VERSION 5.8 ;
BUSBITCHARS "[]" ;
DIVIDERCHAR "/" ;
UNITS
    DATABASE MICRONS 1000 ;
END UNITS

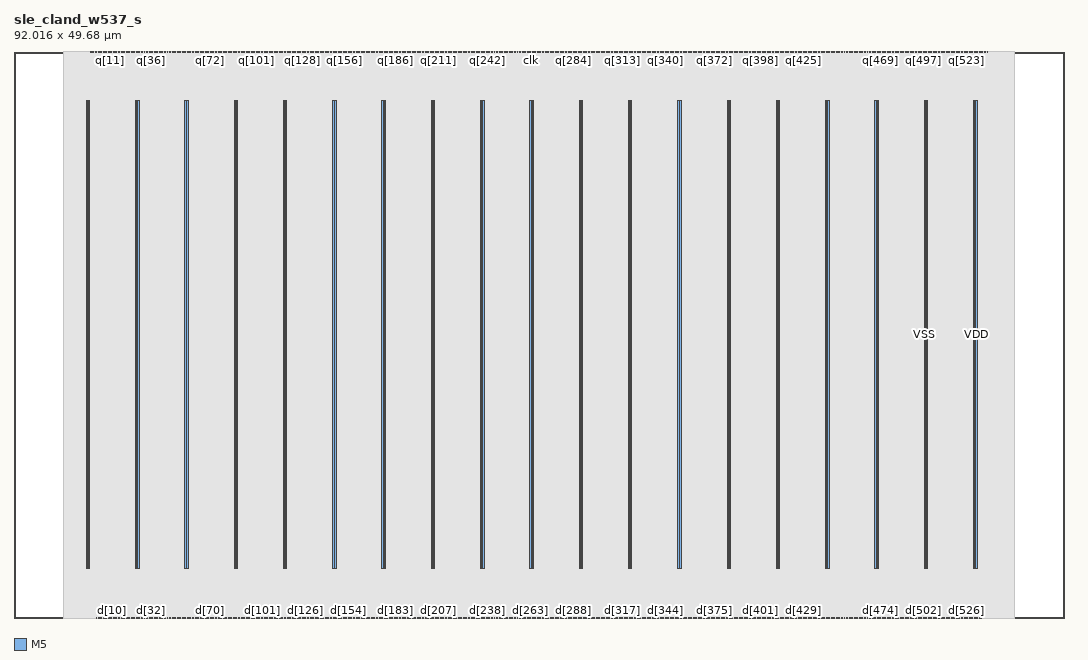
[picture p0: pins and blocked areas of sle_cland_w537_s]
MACRO sle_cland_w537_s
  FOREIGN sle_cland_w537_s 0 0 ;
  CLASS BLOCK ;
  SIZE 92.016 BY 49.68 ;
  PIN clk
    DIRECTION INPUT ;
    USE SIGNAL ;
    PORT
      LAYER M5 ;
        RECT  45.264 49.596 45.288 49.68 ;
    END
  END clk
  PIN d[0]
    DIRECTION INPUT ;
    USE SIGNAL ;
    PORT
      LAYER M5 ;
        RECT  7.248 0 7.272 0.084 ;
    END
  END d[0]
  PIN d[100]
    DIRECTION INPUT ;
    USE SIGNAL ;
    PORT
      LAYER M5 ;
        RECT  21.648 0 21.672 0.084 ;
    END
  END d[100]
  PIN d[101]
    DIRECTION INPUT ;
    USE SIGNAL ;
    PORT
      LAYER M5 ;
        RECT  21.792 0 21.816 0.084 ;
    END
  END d[101]
  PIN d[102]
    DIRECTION INPUT ;
    USE SIGNAL ;
    PORT
      LAYER M5 ;
        RECT  21.936 0 21.96 0.084 ;
    END
  END d[102]
  PIN d[103]
    DIRECTION INPUT ;
    USE SIGNAL ;
    PORT
      LAYER M5 ;
        RECT  22.224 0 22.248 0.084 ;
    END
  END d[103]
  PIN d[104]
    DIRECTION INPUT ;
    USE SIGNAL ;
    PORT
      LAYER M5 ;
        RECT  22.08 0 22.104 0.084 ;
    END
  END d[104]
  PIN d[105]
    DIRECTION INPUT ;
    USE SIGNAL ;
    PORT
      LAYER M5 ;
        RECT  22.512 0 22.536 0.084 ;
    END
  END d[105]
  PIN d[106]
    DIRECTION INPUT ;
    USE SIGNAL ;
    PORT
      LAYER M5 ;
        RECT  22.368 0 22.392 0.084 ;
    END
  END d[106]
  PIN d[107]
    DIRECTION INPUT ;
    USE SIGNAL ;
    PORT
      LAYER M5 ;
        RECT  22.8 0 22.824 0.084 ;
    END
  END d[107]
  PIN d[108]
    DIRECTION INPUT ;
    USE SIGNAL ;
    PORT
      LAYER M5 ;
        RECT  22.656 0 22.68 0.084 ;
    END
  END d[108]
  PIN d[109]
    DIRECTION INPUT ;
    USE SIGNAL ;
    PORT
      LAYER M5 ;
        RECT  23.232 0 23.256 0.084 ;
    END
  END d[109]
  PIN d[10]
    DIRECTION INPUT ;
    USE SIGNAL ;
    PORT
      LAYER M5 ;
        RECT  8.544 0 8.568 0.084 ;
    END
  END d[10]
  PIN d[110]
    DIRECTION INPUT ;
    USE SIGNAL ;
    PORT
      LAYER M5 ;
        RECT  22.944 0 22.968 0.084 ;
    END
  END d[110]
  PIN d[111]
    DIRECTION INPUT ;
    USE SIGNAL ;
    PORT
      LAYER M5 ;
        RECT  23.376 0 23.4 0.084 ;
    END
  END d[111]
  PIN d[112]
    DIRECTION INPUT ;
    USE SIGNAL ;
    PORT
      LAYER M5 ;
        RECT  23.088 0 23.112 0.084 ;
    END
  END d[112]
  PIN d[113]
    DIRECTION INPUT ;
    USE SIGNAL ;
    PORT
      LAYER M5 ;
        RECT  23.664 0 23.688 0.084 ;
    END
  END d[113]
  PIN d[114]
    DIRECTION INPUT ;
    USE SIGNAL ;
    PORT
      LAYER M5 ;
        RECT  23.52 0 23.544 0.084 ;
    END
  END d[114]
  PIN d[115]
    DIRECTION INPUT ;
    USE SIGNAL ;
    PORT
      LAYER M5 ;
        RECT  23.952 0 23.976 0.084 ;
    END
  END d[115]
  PIN d[116]
    DIRECTION INPUT ;
    USE SIGNAL ;
    PORT
      LAYER M5 ;
        RECT  23.808 0 23.832 0.084 ;
    END
  END d[116]
  PIN d[117]
    DIRECTION INPUT ;
    USE SIGNAL ;
    PORT
      LAYER M5 ;
        RECT  24.24 0 24.264 0.084 ;
    END
  END d[117]
  PIN d[118]
    DIRECTION INPUT ;
    USE SIGNAL ;
    PORT
      LAYER M5 ;
        RECT  24.096 0 24.12 0.084 ;
    END
  END d[118]
  PIN d[119]
    DIRECTION INPUT ;
    USE SIGNAL ;
    PORT
      LAYER M5 ;
        RECT  24.528 0 24.552 0.084 ;
    END
  END d[119]
  PIN d[11]
    DIRECTION INPUT ;
    USE SIGNAL ;
    PORT
      LAYER M5 ;
        RECT  8.976 0 9 0.084 ;
    END
  END d[11]
  PIN d[120]
    DIRECTION INPUT ;
    USE SIGNAL ;
    PORT
      LAYER M5 ;
        RECT  24.384 0 24.408 0.084 ;
    END
  END d[120]
  PIN d[121]
    DIRECTION INPUT ;
    USE SIGNAL ;
    PORT
      LAYER M5 ;
        RECT  24.672 0 24.696 0.084 ;
    END
  END d[121]
  PIN d[122]
    DIRECTION INPUT ;
    USE SIGNAL ;
    PORT
      LAYER M5 ;
        RECT  24.96 0 24.984 0.084 ;
    END
  END d[122]
  PIN d[123]
    DIRECTION INPUT ;
    USE SIGNAL ;
    PORT
      LAYER M5 ;
        RECT  24.816 0 24.84 0.084 ;
    END
  END d[123]
  PIN d[124]
    DIRECTION INPUT ;
    USE SIGNAL ;
    PORT
      LAYER M5 ;
        RECT  25.248 0 25.272 0.084 ;
    END
  END d[124]
  PIN d[125]
    DIRECTION INPUT ;
    USE SIGNAL ;
    PORT
      LAYER M5 ;
        RECT  25.104 0 25.128 0.084 ;
    END
  END d[125]
  PIN d[126]
    DIRECTION INPUT ;
    USE SIGNAL ;
    PORT
      LAYER M5 ;
        RECT  25.536 0 25.56 0.084 ;
    END
  END d[126]
  PIN d[127]
    DIRECTION INPUT ;
    USE SIGNAL ;
    PORT
      LAYER M5 ;
        RECT  25.392 0 25.416 0.084 ;
    END
  END d[127]
  PIN d[128]
    DIRECTION INPUT ;
    USE SIGNAL ;
    PORT
      LAYER M5 ;
        RECT  25.824 0 25.848 0.084 ;
    END
  END d[128]
  PIN d[129]
    DIRECTION INPUT ;
    USE SIGNAL ;
    PORT
      LAYER M5 ;
        RECT  25.68 0 25.704 0.084 ;
    END
  END d[129]
  PIN d[12]
    DIRECTION INPUT ;
    USE SIGNAL ;
    PORT
      LAYER M5 ;
        RECT  8.688 0 8.712 0.084 ;
    END
  END d[12]
  PIN d[130]
    DIRECTION INPUT ;
    USE SIGNAL ;
    PORT
      LAYER M5 ;
        RECT  26.112 0 26.136 0.084 ;
    END
  END d[130]
  PIN d[131]
    DIRECTION INPUT ;
    USE SIGNAL ;
    PORT
      LAYER M5 ;
        RECT  25.968 0 25.992 0.084 ;
    END
  END d[131]
  PIN d[132]
    DIRECTION INPUT ;
    USE SIGNAL ;
    PORT
      LAYER M5 ;
        RECT  26.4 0 26.424 0.084 ;
    END
  END d[132]
  PIN d[133]
    DIRECTION INPUT ;
    USE SIGNAL ;
    PORT
      LAYER M5 ;
        RECT  26.256 0 26.28 0.084 ;
    END
  END d[133]
  PIN d[134]
    DIRECTION INPUT ;
    USE SIGNAL ;
    PORT
      LAYER M5 ;
        RECT  26.544 0 26.568 0.084 ;
    END
  END d[134]
  PIN d[135]
    DIRECTION INPUT ;
    USE SIGNAL ;
    PORT
      LAYER M5 ;
        RECT  26.688 0 26.712 0.084 ;
    END
  END d[135]
  PIN d[136]
    DIRECTION INPUT ;
    USE SIGNAL ;
    PORT
      LAYER M5 ;
        RECT  26.976 0 27 0.084 ;
    END
  END d[136]
  PIN d[137]
    DIRECTION INPUT ;
    USE SIGNAL ;
    PORT
      LAYER M5 ;
        RECT  26.832 0 26.856 0.084 ;
    END
  END d[137]
  PIN d[138]
    DIRECTION INPUT ;
    USE SIGNAL ;
    PORT
      LAYER M5 ;
        RECT  27.12 0 27.144 0.084 ;
    END
  END d[138]
  PIN d[139]
    DIRECTION INPUT ;
    USE SIGNAL ;
    PORT
      LAYER M5 ;
        RECT  27.264 0 27.288 0.084 ;
    END
  END d[139]
  PIN d[13]
    DIRECTION INPUT ;
    USE SIGNAL ;
    PORT
      LAYER M5 ;
        RECT  9.264 0 9.288 0.084 ;
    END
  END d[13]
  PIN d[140]
    DIRECTION INPUT ;
    USE SIGNAL ;
    PORT
      LAYER M5 ;
        RECT  27.408 0 27.432 0.084 ;
    END
  END d[140]
  PIN d[141]
    DIRECTION INPUT ;
    USE SIGNAL ;
    PORT
      LAYER M5 ;
        RECT  27.552 0 27.576 0.084 ;
    END
  END d[141]
  PIN d[142]
    DIRECTION INPUT ;
    USE SIGNAL ;
    PORT
      LAYER M5 ;
        RECT  27.696 0 27.72 0.084 ;
    END
  END d[142]
  PIN d[143]
    DIRECTION INPUT ;
    USE SIGNAL ;
    PORT
      LAYER M5 ;
        RECT  27.84 0 27.864 0.084 ;
    END
  END d[143]
  PIN d[144]
    DIRECTION INPUT ;
    USE SIGNAL ;
    PORT
      LAYER M5 ;
        RECT  27.984 0 28.008 0.084 ;
    END
  END d[144]
  PIN d[145]
    DIRECTION INPUT ;
    USE SIGNAL ;
    PORT
      LAYER M5 ;
        RECT  28.128 0 28.152 0.084 ;
    END
  END d[145]
  PIN d[146]
    DIRECTION INPUT ;
    USE SIGNAL ;
    PORT
      LAYER M5 ;
        RECT  28.272 0 28.296 0.084 ;
    END
  END d[146]
  PIN d[147]
    DIRECTION INPUT ;
    USE SIGNAL ;
    PORT
      LAYER M5 ;
        RECT  28.416 0 28.44 0.084 ;
    END
  END d[147]
  PIN d[148]
    DIRECTION INPUT ;
    USE SIGNAL ;
    PORT
      LAYER M5 ;
        RECT  28.56 0 28.584 0.084 ;
    END
  END d[148]
  PIN d[149]
    DIRECTION INPUT ;
    USE SIGNAL ;
    PORT
      LAYER M5 ;
        RECT  28.704 0 28.728 0.084 ;
    END
  END d[149]
  PIN d[14]
    DIRECTION INPUT ;
    USE SIGNAL ;
    PORT
      LAYER M5 ;
        RECT  9.12 0 9.144 0.084 ;
    END
  END d[14]
  PIN d[150]
    DIRECTION INPUT ;
    USE SIGNAL ;
    PORT
      LAYER M5 ;
        RECT  28.848 0 28.872 0.084 ;
    END
  END d[150]
  PIN d[151]
    DIRECTION INPUT ;
    USE SIGNAL ;
    PORT
      LAYER M5 ;
        RECT  28.992 0 29.016 0.084 ;
    END
  END d[151]
  PIN d[152]
    DIRECTION INPUT ;
    USE SIGNAL ;
    PORT
      LAYER M5 ;
        RECT  29.136 0 29.16 0.084 ;
    END
  END d[152]
  PIN d[153]
    DIRECTION INPUT ;
    USE SIGNAL ;
    PORT
      LAYER M5 ;
        RECT  29.424 0 29.448 0.084 ;
    END
  END d[153]
  PIN d[154]
    DIRECTION INPUT ;
    USE SIGNAL ;
    PORT
      LAYER M5 ;
        RECT  29.28 0 29.304 0.084 ;
    END
  END d[154]
  PIN d[155]
    DIRECTION INPUT ;
    USE SIGNAL ;
    PORT
      LAYER M5 ;
        RECT  29.712 0 29.736 0.084 ;
    END
  END d[155]
  PIN d[156]
    DIRECTION INPUT ;
    USE SIGNAL ;
    PORT
      LAYER M5 ;
        RECT  29.568 0 29.592 0.084 ;
    END
  END d[156]
  PIN d[157]
    DIRECTION INPUT ;
    USE SIGNAL ;
    PORT
      LAYER M5 ;
        RECT  30 0 30.024 0.084 ;
    END
  END d[157]
  PIN d[158]
    DIRECTION INPUT ;
    USE SIGNAL ;
    PORT
      LAYER M5 ;
        RECT  29.856 0 29.88 0.084 ;
    END
  END d[158]
  PIN d[159]
    DIRECTION INPUT ;
    USE SIGNAL ;
    PORT
      LAYER M5 ;
        RECT  30.432 0 30.456 0.084 ;
    END
  END d[159]
  PIN d[15]
    DIRECTION INPUT ;
    USE SIGNAL ;
    PORT
      LAYER M5 ;
        RECT  9.552 0 9.576 0.084 ;
    END
  END d[15]
  PIN d[160]
    DIRECTION INPUT ;
    USE SIGNAL ;
    PORT
      LAYER M5 ;
        RECT  30.144 0 30.168 0.084 ;
    END
  END d[160]
  PIN d[161]
    DIRECTION INPUT ;
    USE SIGNAL ;
    PORT
      LAYER M5 ;
        RECT  30.576 0 30.6 0.084 ;
    END
  END d[161]
  PIN d[162]
    DIRECTION INPUT ;
    USE SIGNAL ;
    PORT
      LAYER M5 ;
        RECT  30.288 0 30.312 0.084 ;
    END
  END d[162]
  PIN d[163]
    DIRECTION INPUT ;
    USE SIGNAL ;
    PORT
      LAYER M5 ;
        RECT  30.864 0 30.888 0.084 ;
    END
  END d[163]
  PIN d[164]
    DIRECTION INPUT ;
    USE SIGNAL ;
    PORT
      LAYER M5 ;
        RECT  30.72 0 30.744 0.084 ;
    END
  END d[164]
  PIN d[165]
    DIRECTION INPUT ;
    USE SIGNAL ;
    PORT
      LAYER M5 ;
        RECT  31.152 0 31.176 0.084 ;
    END
  END d[165]
  PIN d[166]
    DIRECTION INPUT ;
    USE SIGNAL ;
    PORT
      LAYER M5 ;
        RECT  31.008 0 31.032 0.084 ;
    END
  END d[166]
  PIN d[167]
    DIRECTION INPUT ;
    USE SIGNAL ;
    PORT
      LAYER M5 ;
        RECT  31.44 0 31.464 0.084 ;
    END
  END d[167]
  PIN d[168]
    DIRECTION INPUT ;
    USE SIGNAL ;
    PORT
      LAYER M5 ;
        RECT  31.296 0 31.32 0.084 ;
    END
  END d[168]
  PIN d[169]
    DIRECTION INPUT ;
    USE SIGNAL ;
    PORT
      LAYER M5 ;
        RECT  31.728 0 31.752 0.084 ;
    END
  END d[169]
  PIN d[16]
    DIRECTION INPUT ;
    USE SIGNAL ;
    PORT
      LAYER M5 ;
        RECT  9.408 0 9.432 0.084 ;
    END
  END d[16]
  PIN d[170]
    DIRECTION INPUT ;
    USE SIGNAL ;
    PORT
      LAYER M5 ;
        RECT  31.584 0 31.608 0.084 ;
    END
  END d[170]
  PIN d[171]
    DIRECTION INPUT ;
    USE SIGNAL ;
    PORT
      LAYER M5 ;
        RECT  31.872 0 31.896 0.084 ;
    END
  END d[171]
  PIN d[172]
    DIRECTION INPUT ;
    USE SIGNAL ;
    PORT
      LAYER M5 ;
        RECT  32.16 0 32.184 0.084 ;
    END
  END d[172]
  PIN d[173]
    DIRECTION INPUT ;
    USE SIGNAL ;
    PORT
      LAYER M5 ;
        RECT  32.016 0 32.04 0.084 ;
    END
  END d[173]
  PIN d[174]
    DIRECTION INPUT ;
    USE SIGNAL ;
    PORT
      LAYER M5 ;
        RECT  32.448 0 32.472 0.084 ;
    END
  END d[174]
  PIN d[175]
    DIRECTION INPUT ;
    USE SIGNAL ;
    PORT
      LAYER M5 ;
        RECT  32.304 0 32.328 0.084 ;
    END
  END d[175]
  PIN d[176]
    DIRECTION INPUT ;
    USE SIGNAL ;
    PORT
      LAYER M5 ;
        RECT  32.736 0 32.76 0.084 ;
    END
  END d[176]
  PIN d[177]
    DIRECTION INPUT ;
    USE SIGNAL ;
    PORT
      LAYER M5 ;
        RECT  32.592 0 32.616 0.084 ;
    END
  END d[177]
  PIN d[178]
    DIRECTION INPUT ;
    USE SIGNAL ;
    PORT
      LAYER M5 ;
        RECT  33.024 0 33.048 0.084 ;
    END
  END d[178]
  PIN d[179]
    DIRECTION INPUT ;
    USE SIGNAL ;
    PORT
      LAYER M5 ;
        RECT  32.88 0 32.904 0.084 ;
    END
  END d[179]
  PIN d[17]
    DIRECTION INPUT ;
    USE SIGNAL ;
    PORT
      LAYER M5 ;
        RECT  9.84 0 9.864 0.084 ;
    END
  END d[17]
  PIN d[180]
    DIRECTION INPUT ;
    USE SIGNAL ;
    PORT
      LAYER M5 ;
        RECT  33.312 0 33.336 0.084 ;
    END
  END d[180]
  PIN d[181]
    DIRECTION INPUT ;
    USE SIGNAL ;
    PORT
      LAYER M5 ;
        RECT  33.168 0 33.192 0.084 ;
    END
  END d[181]
  PIN d[182]
    DIRECTION INPUT ;
    USE SIGNAL ;
    PORT
      LAYER M5 ;
        RECT  33.6 0 33.624 0.084 ;
    END
  END d[182]
  PIN d[183]
    DIRECTION INPUT ;
    USE SIGNAL ;
    PORT
      LAYER M5 ;
        RECT  33.456 0 33.48 0.084 ;
    END
  END d[183]
  PIN d[184]
    DIRECTION INPUT ;
    USE SIGNAL ;
    PORT
      LAYER M5 ;
        RECT  33.744 0 33.768 0.084 ;
    END
  END d[184]
  PIN d[185]
    DIRECTION INPUT ;
    USE SIGNAL ;
    PORT
      LAYER M5 ;
        RECT  33.888 0 33.912 0.084 ;
    END
  END d[185]
  PIN d[186]
    DIRECTION INPUT ;
    USE SIGNAL ;
    PORT
      LAYER M5 ;
        RECT  34.032 0 34.056 0.084 ;
    END
  END d[186]
  PIN d[187]
    DIRECTION INPUT ;
    USE SIGNAL ;
    PORT
      LAYER M5 ;
        RECT  34.176 0 34.2 0.084 ;
    END
  END d[187]
  PIN d[188]
    DIRECTION INPUT ;
    USE SIGNAL ;
    PORT
      LAYER M5 ;
        RECT  34.32 0 34.344 0.084 ;
    END
  END d[188]
  PIN d[189]
    DIRECTION INPUT ;
    USE SIGNAL ;
    PORT
      LAYER M5 ;
        RECT  34.464 0 34.488 0.084 ;
    END
  END d[189]
  PIN d[18]
    DIRECTION INPUT ;
    USE SIGNAL ;
    PORT
      LAYER M5 ;
        RECT  9.696 0 9.72 0.084 ;
    END
  END d[18]
  PIN d[190]
    DIRECTION INPUT ;
    USE SIGNAL ;
    PORT
      LAYER M5 ;
        RECT  34.608 0 34.632 0.084 ;
    END
  END d[190]
  PIN d[191]
    DIRECTION INPUT ;
    USE SIGNAL ;
    PORT
      LAYER M5 ;
        RECT  34.752 0 34.776 0.084 ;
    END
  END d[191]
  PIN d[192]
    DIRECTION INPUT ;
    USE SIGNAL ;
    PORT
      LAYER M5 ;
        RECT  34.896 0 34.92 0.084 ;
    END
  END d[192]
  PIN d[193]
    DIRECTION INPUT ;
    USE SIGNAL ;
    PORT
      LAYER M5 ;
        RECT  35.04 0 35.064 0.084 ;
    END
  END d[193]
  PIN d[194]
    DIRECTION INPUT ;
    USE SIGNAL ;
    PORT
      LAYER M5 ;
        RECT  35.184 0 35.208 0.084 ;
    END
  END d[194]
  PIN d[195]
    DIRECTION INPUT ;
    USE SIGNAL ;
    PORT
      LAYER M5 ;
        RECT  35.328 0 35.352 0.084 ;
    END
  END d[195]
  PIN d[196]
    DIRECTION INPUT ;
    USE SIGNAL ;
    PORT
      LAYER M5 ;
        RECT  35.472 0 35.496 0.084 ;
    END
  END d[196]
  PIN d[197]
    DIRECTION INPUT ;
    USE SIGNAL ;
    PORT
      LAYER M5 ;
        RECT  35.616 0 35.64 0.084 ;
    END
  END d[197]
  PIN d[198]
    DIRECTION INPUT ;
    USE SIGNAL ;
    PORT
      LAYER M5 ;
        RECT  35.76 0 35.784 0.084 ;
    END
  END d[198]
  PIN d[199]
    DIRECTION INPUT ;
    USE SIGNAL ;
    PORT
      LAYER M5 ;
        RECT  35.904 0 35.928 0.084 ;
    END
  END d[199]
  PIN d[19]
    DIRECTION INPUT ;
    USE SIGNAL ;
    PORT
      LAYER M5 ;
        RECT  10.128 0 10.152 0.084 ;
    END
  END d[19]
  PIN d[1]
    DIRECTION INPUT ;
    USE SIGNAL ;
    PORT
      LAYER M5 ;
        RECT  7.392 0 7.416 0.084 ;
    END
  END d[1]
  PIN d[200]
    DIRECTION INPUT ;
    USE SIGNAL ;
    PORT
      LAYER M5 ;
        RECT  36.048 0 36.072 0.084 ;
    END
  END d[200]
  PIN d[201]
    DIRECTION INPUT ;
    USE SIGNAL ;
    PORT
      LAYER M5 ;
        RECT  36.192 0 36.216 0.084 ;
    END
  END d[201]
  PIN d[202]
    DIRECTION INPUT ;
    USE SIGNAL ;
    PORT
      LAYER M5 ;
        RECT  36.336 0 36.36 0.084 ;
    END
  END d[202]
  PIN d[203]
    DIRECTION INPUT ;
    USE SIGNAL ;
    PORT
      LAYER M5 ;
        RECT  36.624 0 36.648 0.084 ;
    END
  END d[203]
  PIN d[204]
    DIRECTION INPUT ;
    USE SIGNAL ;
    PORT
      LAYER M5 ;
        RECT  36.48 0 36.504 0.084 ;
    END
  END d[204]
  PIN d[205]
    DIRECTION INPUT ;
    USE SIGNAL ;
    PORT
      LAYER M5 ;
        RECT  36.912 0 36.936 0.084 ;
    END
  END d[205]
  PIN d[206]
    DIRECTION INPUT ;
    USE SIGNAL ;
    PORT
      LAYER M5 ;
        RECT  36.768 0 36.792 0.084 ;
    END
  END d[206]
  PIN d[207]
    DIRECTION INPUT ;
    USE SIGNAL ;
    PORT
      LAYER M5 ;
        RECT  37.2 0 37.224 0.084 ;
    END
  END d[207]
  PIN d[208]
    DIRECTION INPUT ;
    USE SIGNAL ;
    PORT
      LAYER M5 ;
        RECT  37.056 0 37.08 0.084 ;
    END
  END d[208]
  PIN d[209]
    DIRECTION INPUT ;
    USE SIGNAL ;
    PORT
      LAYER M5 ;
        RECT  37.632 0 37.656 0.084 ;
    END
  END d[209]
  PIN d[20]
    DIRECTION INPUT ;
    USE SIGNAL ;
    PORT
      LAYER M5 ;
        RECT  9.984 0 10.008 0.084 ;
    END
  END d[20]
  PIN d[210]
    DIRECTION INPUT ;
    USE SIGNAL ;
    PORT
      LAYER M5 ;
        RECT  37.344 0 37.368 0.084 ;
    END
  END d[210]
  PIN d[211]
    DIRECTION INPUT ;
    USE SIGNAL ;
    PORT
      LAYER M5 ;
        RECT  37.776 0 37.8 0.084 ;
    END
  END d[211]
  PIN d[212]
    DIRECTION INPUT ;
    USE SIGNAL ;
    PORT
      LAYER M5 ;
        RECT  37.488 0 37.512 0.084 ;
    END
  END d[212]
  PIN d[213]
    DIRECTION INPUT ;
    USE SIGNAL ;
    PORT
      LAYER M5 ;
        RECT  38.064 0 38.088 0.084 ;
    END
  END d[213]
  PIN d[214]
    DIRECTION INPUT ;
    USE SIGNAL ;
    PORT
      LAYER M5 ;
        RECT  37.92 0 37.944 0.084 ;
    END
  END d[214]
  PIN d[215]
    DIRECTION INPUT ;
    USE SIGNAL ;
    PORT
      LAYER M5 ;
        RECT  38.352 0 38.376 0.084 ;
    END
  END d[215]
  PIN d[216]
    DIRECTION INPUT ;
    USE SIGNAL ;
    PORT
      LAYER M5 ;
        RECT  38.208 0 38.232 0.084 ;
    END
  END d[216]
  PIN d[217]
    DIRECTION INPUT ;
    USE SIGNAL ;
    PORT
      LAYER M5 ;
        RECT  38.64 0 38.664 0.084 ;
    END
  END d[217]
  PIN d[218]
    DIRECTION INPUT ;
    USE SIGNAL ;
    PORT
      LAYER M5 ;
        RECT  38.496 0 38.52 0.084 ;
    END
  END d[218]
  PIN d[219]
    DIRECTION INPUT ;
    USE SIGNAL ;
    PORT
      LAYER M5 ;
        RECT  39.072 0 39.096 0.084 ;
    END
  END d[219]
  PIN d[21]
    DIRECTION INPUT ;
    USE SIGNAL ;
    PORT
      LAYER M5 ;
        RECT  10.272 0 10.296 0.084 ;
    END
  END d[21]
  PIN d[220]
    DIRECTION INPUT ;
    USE SIGNAL ;
    PORT
      LAYER M5 ;
        RECT  38.784 0 38.808 0.084 ;
    END
  END d[220]
  PIN d[221]
    DIRECTION INPUT ;
    USE SIGNAL ;
    PORT
      LAYER M5 ;
        RECT  39.216 0 39.24 0.084 ;
    END
  END d[221]
  PIN d[222]
    DIRECTION INPUT ;
    USE SIGNAL ;
    PORT
      LAYER M5 ;
        RECT  38.928 0 38.952 0.084 ;
    END
  END d[222]
  PIN d[223]
    DIRECTION INPUT ;
    USE SIGNAL ;
    PORT
      LAYER M5 ;
        RECT  39.36 0 39.384 0.084 ;
    END
  END d[223]
  PIN d[224]
    DIRECTION INPUT ;
    USE SIGNAL ;
    PORT
      LAYER M5 ;
        RECT  39.648 0 39.672 0.084 ;
    END
  END d[224]
  PIN d[225]
    DIRECTION INPUT ;
    USE SIGNAL ;
    PORT
      LAYER M5 ;
        RECT  39.504 0 39.528 0.084 ;
    END
  END d[225]
  PIN d[226]
    DIRECTION INPUT ;
    USE SIGNAL ;
    PORT
      LAYER M5 ;
        RECT  39.936 0 39.96 0.084 ;
    END
  END d[226]
  PIN d[227]
    DIRECTION INPUT ;
    USE SIGNAL ;
    PORT
      LAYER M5 ;
        RECT  39.792 0 39.816 0.084 ;
    END
  END d[227]
  PIN d[228]
    DIRECTION INPUT ;
    USE SIGNAL ;
    PORT
      LAYER M5 ;
        RECT  40.224 0 40.248 0.084 ;
    END
  END d[228]
  PIN d[229]
    DIRECTION INPUT ;
    USE SIGNAL ;
    PORT
      LAYER M5 ;
        RECT  40.08 0 40.104 0.084 ;
    END
  END d[229]
  PIN d[22]
    DIRECTION INPUT ;
    USE SIGNAL ;
    PORT
      LAYER M5 ;
        RECT  10.56 0 10.584 0.084 ;
    END
  END d[22]
  PIN d[230]
    DIRECTION INPUT ;
    USE SIGNAL ;
    PORT
      LAYER M5 ;
        RECT  40.512 0 40.536 0.084 ;
    END
  END d[230]
  PIN d[231]
    DIRECTION INPUT ;
    USE SIGNAL ;
    PORT
      LAYER M5 ;
        RECT  40.368 0 40.392 0.084 ;
    END
  END d[231]
  PIN d[232]
    DIRECTION INPUT ;
    USE SIGNAL ;
    PORT
      LAYER M5 ;
        RECT  40.8 0 40.824 0.084 ;
    END
  END d[232]
  PIN d[233]
    DIRECTION INPUT ;
    USE SIGNAL ;
    PORT
      LAYER M5 ;
        RECT  40.656 0 40.68 0.084 ;
    END
  END d[233]
  PIN d[234]
    DIRECTION INPUT ;
    USE SIGNAL ;
    PORT
      LAYER M5 ;
        RECT  40.944 0 40.968 0.084 ;
    END
  END d[234]
  PIN d[235]
    DIRECTION INPUT ;
    USE SIGNAL ;
    PORT
      LAYER M5 ;
        RECT  41.088 0 41.112 0.084 ;
    END
  END d[235]
  PIN d[236]
    DIRECTION INPUT ;
    USE SIGNAL ;
    PORT
      LAYER M5 ;
        RECT  41.232 0 41.256 0.084 ;
    END
  END d[236]
  PIN d[237]
    DIRECTION INPUT ;
    USE SIGNAL ;
    PORT
      LAYER M5 ;
        RECT  41.376 0 41.4 0.084 ;
    END
  END d[237]
  PIN d[238]
    DIRECTION INPUT ;
    USE SIGNAL ;
    PORT
      LAYER M5 ;
        RECT  41.52 0 41.544 0.084 ;
    END
  END d[238]
  PIN d[239]
    DIRECTION INPUT ;
    USE SIGNAL ;
    PORT
      LAYER M5 ;
        RECT  41.664 0 41.688 0.084 ;
    END
  END d[239]
  PIN d[23]
    DIRECTION INPUT ;
    USE SIGNAL ;
    PORT
      LAYER M5 ;
        RECT  10.416 0 10.44 0.084 ;
    END
  END d[23]
  PIN d[240]
    DIRECTION INPUT ;
    USE SIGNAL ;
    PORT
      LAYER M5 ;
        RECT  41.808 0 41.832 0.084 ;
    END
  END d[240]
  PIN d[241]
    DIRECTION INPUT ;
    USE SIGNAL ;
    PORT
      LAYER M5 ;
        RECT  41.952 0 41.976 0.084 ;
    END
  END d[241]
  PIN d[242]
    DIRECTION INPUT ;
    USE SIGNAL ;
    PORT
      LAYER M5 ;
        RECT  42.096 0 42.12 0.084 ;
    END
  END d[242]
  PIN d[243]
    DIRECTION INPUT ;
    USE SIGNAL ;
    PORT
      LAYER M5 ;
        RECT  42.24 0 42.264 0.084 ;
    END
  END d[243]
  PIN d[244]
    DIRECTION INPUT ;
    USE SIGNAL ;
    PORT
      LAYER M5 ;
        RECT  42.384 0 42.408 0.084 ;
    END
  END d[244]
  PIN d[245]
    DIRECTION INPUT ;
    USE SIGNAL ;
    PORT
      LAYER M5 ;
        RECT  42.528 0 42.552 0.084 ;
    END
  END d[245]
  PIN d[246]
    DIRECTION INPUT ;
    USE SIGNAL ;
    PORT
      LAYER M5 ;
        RECT  42.672 0 42.696 0.084 ;
    END
  END d[246]
  PIN d[247]
    DIRECTION INPUT ;
    USE SIGNAL ;
    PORT
      LAYER M5 ;
        RECT  42.816 0 42.84 0.084 ;
    END
  END d[247]
  PIN d[248]
    DIRECTION INPUT ;
    USE SIGNAL ;
    PORT
      LAYER M5 ;
        RECT  42.96 0 42.984 0.084 ;
    END
  END d[248]
  PIN d[249]
    DIRECTION INPUT ;
    USE SIGNAL ;
    PORT
      LAYER M5 ;
        RECT  43.248 0 43.272 0.084 ;
    END
  END d[249]
  PIN d[24]
    DIRECTION INPUT ;
    USE SIGNAL ;
    PORT
      LAYER M5 ;
        RECT  10.848 0 10.872 0.084 ;
    END
  END d[24]
  PIN d[250]
    DIRECTION INPUT ;
    USE SIGNAL ;
    PORT
      LAYER M5 ;
        RECT  43.104 0 43.128 0.084 ;
    END
  END d[250]
  PIN d[251]
    DIRECTION INPUT ;
    USE SIGNAL ;
    PORT
      LAYER M5 ;
        RECT  43.536 0 43.56 0.084 ;
    END
  END d[251]
  PIN d[252]
    DIRECTION INPUT ;
    USE SIGNAL ;
    PORT
      LAYER M5 ;
        RECT  43.392 0 43.416 0.084 ;
    END
  END d[252]
  PIN d[253]
    DIRECTION INPUT ;
    USE SIGNAL ;
    PORT
      LAYER M5 ;
        RECT  43.824 0 43.848 0.084 ;
    END
  END d[253]
  PIN d[254]
    DIRECTION INPUT ;
    USE SIGNAL ;
    PORT
      LAYER M5 ;
        RECT  43.68 0 43.704 0.084 ;
    END
  END d[254]
  PIN d[255]
    DIRECTION INPUT ;
    USE SIGNAL ;
    PORT
      LAYER M5 ;
        RECT  44.112 0 44.136 0.084 ;
    END
  END d[255]
  PIN d[256]
    DIRECTION INPUT ;
    USE SIGNAL ;
    PORT
      LAYER M5 ;
        RECT  43.968 0 43.992 0.084 ;
    END
  END d[256]
  PIN d[257]
    DIRECTION INPUT ;
    USE SIGNAL ;
    PORT
      LAYER M5 ;
        RECT  44.4 0 44.424 0.084 ;
    END
  END d[257]
  PIN d[258]
    DIRECTION INPUT ;
    USE SIGNAL ;
    PORT
      LAYER M5 ;
        RECT  44.256 0 44.28 0.084 ;
    END
  END d[258]
  PIN d[259]
    DIRECTION INPUT ;
    USE SIGNAL ;
    PORT
      LAYER M5 ;
        RECT  44.832 0 44.856 0.084 ;
    END
  END d[259]
  PIN d[25]
    DIRECTION INPUT ;
    USE SIGNAL ;
    PORT
      LAYER M5 ;
        RECT  10.704 0 10.728 0.084 ;
    END
  END d[25]
  PIN d[260]
    DIRECTION INPUT ;
    USE SIGNAL ;
    PORT
      LAYER M5 ;
        RECT  44.544 0 44.568 0.084 ;
    END
  END d[260]
  PIN d[261]
    DIRECTION INPUT ;
    USE SIGNAL ;
    PORT
      LAYER M5 ;
        RECT  44.976 0 45 0.084 ;
    END
  END d[261]
  PIN d[262]
    DIRECTION INPUT ;
    USE SIGNAL ;
    PORT
      LAYER M5 ;
        RECT  44.688 0 44.712 0.084 ;
    END
  END d[262]
  PIN d[263]
    DIRECTION INPUT ;
    USE SIGNAL ;
    PORT
      LAYER M5 ;
        RECT  45.264 0 45.288 0.084 ;
    END
  END d[263]
  PIN d[264]
    DIRECTION INPUT ;
    USE SIGNAL ;
    PORT
      LAYER M5 ;
        RECT  45.12 0 45.144 0.084 ;
    END
  END d[264]
  PIN d[265]
    DIRECTION INPUT ;
    USE SIGNAL ;
    PORT
      LAYER M5 ;
        RECT  45.552 0 45.576 0.084 ;
    END
  END d[265]
  PIN d[266]
    DIRECTION INPUT ;
    USE SIGNAL ;
    PORT
      LAYER M5 ;
        RECT  45.408 0 45.432 0.084 ;
    END
  END d[266]
  PIN d[267]
    DIRECTION INPUT ;
    USE SIGNAL ;
    PORT
      LAYER M5 ;
        RECT  46.128 0 46.152 0.084 ;
    END
  END d[267]
  PIN d[268]
    DIRECTION INPUT ;
    USE SIGNAL ;
    PORT
      LAYER M5 ;
        RECT  45.696 0 45.72 0.084 ;
    END
  END d[268]
  PIN d[269]
    DIRECTION INPUT ;
    USE SIGNAL ;
    PORT
      LAYER M5 ;
        RECT  46.416 0 46.44 0.084 ;
    END
  END d[269]
  PIN d[26]
    DIRECTION INPUT ;
    USE SIGNAL ;
    PORT
      LAYER M5 ;
        RECT  11.136 0 11.16 0.084 ;
    END
  END d[26]
  PIN d[270]
    DIRECTION INPUT ;
    USE SIGNAL ;
    PORT
      LAYER M5 ;
        RECT  46.272 0 46.296 0.084 ;
    END
  END d[270]
  PIN d[271]
    DIRECTION INPUT ;
    USE SIGNAL ;
    PORT
      LAYER M5 ;
        RECT  46.56 0 46.584 0.084 ;
    END
  END d[271]
  PIN d[272]
    DIRECTION INPUT ;
    USE SIGNAL ;
    PORT
      LAYER M5 ;
        RECT  46.848 0 46.872 0.084 ;
    END
  END d[272]
  PIN d[273]
    DIRECTION INPUT ;
    USE SIGNAL ;
    PORT
      LAYER M5 ;
        RECT  46.704 0 46.728 0.084 ;
    END
  END d[273]
  PIN d[274]
    DIRECTION INPUT ;
    USE SIGNAL ;
    PORT
      LAYER M5 ;
        RECT  47.136 0 47.16 0.084 ;
    END
  END d[274]
  PIN d[275]
    DIRECTION INPUT ;
    USE SIGNAL ;
    PORT
      LAYER M5 ;
        RECT  46.992 0 47.016 0.084 ;
    END
  END d[275]
  PIN d[276]
    DIRECTION INPUT ;
    USE SIGNAL ;
    PORT
      LAYER M5 ;
        RECT  47.424 0 47.448 0.084 ;
    END
  END d[276]
  PIN d[277]
    DIRECTION INPUT ;
    USE SIGNAL ;
    PORT
      LAYER M5 ;
        RECT  47.28 0 47.304 0.084 ;
    END
  END d[277]
  PIN d[278]
    DIRECTION INPUT ;
    USE SIGNAL ;
    PORT
      LAYER M5 ;
        RECT  47.712 0 47.736 0.084 ;
    END
  END d[278]
  PIN d[279]
    DIRECTION INPUT ;
    USE SIGNAL ;
    PORT
      LAYER M5 ;
        RECT  47.568 0 47.592 0.084 ;
    END
  END d[279]
  PIN d[27]
    DIRECTION INPUT ;
    USE SIGNAL ;
    PORT
      LAYER M5 ;
        RECT  10.992 0 11.016 0.084 ;
    END
  END d[27]
  PIN d[280]
    DIRECTION INPUT ;
    USE SIGNAL ;
    PORT
      LAYER M5 ;
        RECT  48 0 48.024 0.084 ;
    END
  END d[280]
  PIN d[281]
    DIRECTION INPUT ;
    USE SIGNAL ;
    PORT
      LAYER M5 ;
        RECT  47.856 0 47.88 0.084 ;
    END
  END d[281]
  PIN d[282]
    DIRECTION INPUT ;
    USE SIGNAL ;
    PORT
      LAYER M5 ;
        RECT  48.288 0 48.312 0.084 ;
    END
  END d[282]
  PIN d[283]
    DIRECTION INPUT ;
    USE SIGNAL ;
    PORT
      LAYER M5 ;
        RECT  48.144 0 48.168 0.084 ;
    END
  END d[283]
  PIN d[284]
    DIRECTION INPUT ;
    USE SIGNAL ;
    PORT
      LAYER M5 ;
        RECT  48.432 0 48.456 0.084 ;
    END
  END d[284]
  PIN d[285]
    DIRECTION INPUT ;
    USE SIGNAL ;
    PORT
      LAYER M5 ;
        RECT  48.576 0 48.6 0.084 ;
    END
  END d[285]
  PIN d[286]
    DIRECTION INPUT ;
    USE SIGNAL ;
    PORT
      LAYER M5 ;
        RECT  48.864 0 48.888 0.084 ;
    END
  END d[286]
  PIN d[287]
    DIRECTION INPUT ;
    USE SIGNAL ;
    PORT
      LAYER M5 ;
        RECT  48.72 0 48.744 0.084 ;
    END
  END d[287]
  PIN d[288]
    DIRECTION INPUT ;
    USE SIGNAL ;
    PORT
      LAYER M5 ;
        RECT  49.008 0 49.032 0.084 ;
    END
  END d[288]
  PIN d[289]
    DIRECTION INPUT ;
    USE SIGNAL ;
    PORT
      LAYER M5 ;
        RECT  49.152 0 49.176 0.084 ;
    END
  END d[289]
  PIN d[28]
    DIRECTION INPUT ;
    USE SIGNAL ;
    PORT
      LAYER M5 ;
        RECT  11.424 0 11.448 0.084 ;
    END
  END d[28]
  PIN d[290]
    DIRECTION INPUT ;
    USE SIGNAL ;
    PORT
      LAYER M5 ;
        RECT  49.296 0 49.32 0.084 ;
    END
  END d[290]
  PIN d[291]
    DIRECTION INPUT ;
    USE SIGNAL ;
    PORT
      LAYER M5 ;
        RECT  49.44 0 49.464 0.084 ;
    END
  END d[291]
  PIN d[292]
    DIRECTION INPUT ;
    USE SIGNAL ;
    PORT
      LAYER M5 ;
        RECT  49.584 0 49.608 0.084 ;
    END
  END d[292]
  PIN d[293]
    DIRECTION INPUT ;
    USE SIGNAL ;
    PORT
      LAYER M5 ;
        RECT  49.728 0 49.752 0.084 ;
    END
  END d[293]
  PIN d[294]
    DIRECTION INPUT ;
    USE SIGNAL ;
    PORT
      LAYER M5 ;
        RECT  49.872 0 49.896 0.084 ;
    END
  END d[294]
  PIN d[295]
    DIRECTION INPUT ;
    USE SIGNAL ;
    PORT
      LAYER M5 ;
        RECT  50.016 0 50.04 0.084 ;
    END
  END d[295]
  PIN d[296]
    DIRECTION INPUT ;
    USE SIGNAL ;
    PORT
      LAYER M5 ;
        RECT  50.16 0 50.184 0.084 ;
    END
  END d[296]
  PIN d[297]
    DIRECTION INPUT ;
    USE SIGNAL ;
    PORT
      LAYER M5 ;
        RECT  50.304 0 50.328 0.084 ;
    END
  END d[297]
  PIN d[298]
    DIRECTION INPUT ;
    USE SIGNAL ;
    PORT
      LAYER M5 ;
        RECT  50.448 0 50.472 0.084 ;
    END
  END d[298]
  PIN d[299]
    DIRECTION INPUT ;
    USE SIGNAL ;
    PORT
      LAYER M5 ;
        RECT  50.592 0 50.616 0.084 ;
    END
  END d[299]
  PIN d[29]
    DIRECTION INPUT ;
    USE SIGNAL ;
    PORT
      LAYER M5 ;
        RECT  11.28 0 11.304 0.084 ;
    END
  END d[29]
  PIN d[2]
    DIRECTION INPUT ;
    USE SIGNAL ;
    PORT
      LAYER M5 ;
        RECT  7.536 0 7.56 0.084 ;
    END
  END d[2]
  PIN d[300]
    DIRECTION INPUT ;
    USE SIGNAL ;
    PORT
      LAYER M5 ;
        RECT  50.736 0 50.76 0.084 ;
    END
  END d[300]
  PIN d[301]
    DIRECTION INPUT ;
    USE SIGNAL ;
    PORT
      LAYER M5 ;
        RECT  50.88 0 50.904 0.084 ;
    END
  END d[301]
  PIN d[302]
    DIRECTION INPUT ;
    USE SIGNAL ;
    PORT
      LAYER M5 ;
        RECT  51.024 0 51.048 0.084 ;
    END
  END d[302]
  PIN d[303]
    DIRECTION INPUT ;
    USE SIGNAL ;
    PORT
      LAYER M5 ;
        RECT  51.312 0 51.336 0.084 ;
    END
  END d[303]
  PIN d[304]
    DIRECTION INPUT ;
    USE SIGNAL ;
    PORT
      LAYER M5 ;
        RECT  51.168 0 51.192 0.084 ;
    END
  END d[304]
  PIN d[305]
    DIRECTION INPUT ;
    USE SIGNAL ;
    PORT
      LAYER M5 ;
        RECT  51.6 0 51.624 0.084 ;
    END
  END d[305]
  PIN d[306]
    DIRECTION INPUT ;
    USE SIGNAL ;
    PORT
      LAYER M5 ;
        RECT  51.456 0 51.48 0.084 ;
    END
  END d[306]
  PIN d[307]
    DIRECTION INPUT ;
    USE SIGNAL ;
    PORT
      LAYER M5 ;
        RECT  51.888 0 51.912 0.084 ;
    END
  END d[307]
  PIN d[308]
    DIRECTION INPUT ;
    USE SIGNAL ;
    PORT
      LAYER M5 ;
        RECT  51.744 0 51.768 0.084 ;
    END
  END d[308]
  PIN d[309]
    DIRECTION INPUT ;
    USE SIGNAL ;
    PORT
      LAYER M5 ;
        RECT  52.32 0 52.344 0.084 ;
    END
  END d[309]
  PIN d[30]
    DIRECTION INPUT ;
    USE SIGNAL ;
    PORT
      LAYER M5 ;
        RECT  11.712 0 11.736 0.084 ;
    END
  END d[30]
  PIN d[310]
    DIRECTION INPUT ;
    USE SIGNAL ;
    PORT
      LAYER M5 ;
        RECT  52.032 0 52.056 0.084 ;
    END
  END d[310]
  PIN d[311]
    DIRECTION INPUT ;
    USE SIGNAL ;
    PORT
      LAYER M5 ;
        RECT  52.464 0 52.488 0.084 ;
    END
  END d[311]
  PIN d[312]
    DIRECTION INPUT ;
    USE SIGNAL ;
    PORT
      LAYER M5 ;
        RECT  52.176 0 52.2 0.084 ;
    END
  END d[312]
  PIN d[313]
    DIRECTION INPUT ;
    USE SIGNAL ;
    PORT
      LAYER M5 ;
        RECT  52.752 0 52.776 0.084 ;
    END
  END d[313]
  PIN d[314]
    DIRECTION INPUT ;
    USE SIGNAL ;
    PORT
      LAYER M5 ;
        RECT  52.608 0 52.632 0.084 ;
    END
  END d[314]
  PIN d[315]
    DIRECTION INPUT ;
    USE SIGNAL ;
    PORT
      LAYER M5 ;
        RECT  53.04 0 53.064 0.084 ;
    END
  END d[315]
  PIN d[316]
    DIRECTION INPUT ;
    USE SIGNAL ;
    PORT
      LAYER M5 ;
        RECT  52.896 0 52.92 0.084 ;
    END
  END d[316]
  PIN d[317]
    DIRECTION INPUT ;
    USE SIGNAL ;
    PORT
      LAYER M5 ;
        RECT  53.328 0 53.352 0.084 ;
    END
  END d[317]
  PIN d[318]
    DIRECTION INPUT ;
    USE SIGNAL ;
    PORT
      LAYER M5 ;
        RECT  53.184 0 53.208 0.084 ;
    END
  END d[318]
  PIN d[319]
    DIRECTION INPUT ;
    USE SIGNAL ;
    PORT
      LAYER M5 ;
        RECT  53.616 0 53.64 0.084 ;
    END
  END d[319]
  PIN d[31]
    DIRECTION INPUT ;
    USE SIGNAL ;
    PORT
      LAYER M5 ;
        RECT  11.568 0 11.592 0.084 ;
    END
  END d[31]
  PIN d[320]
    DIRECTION INPUT ;
    USE SIGNAL ;
    PORT
      LAYER M5 ;
        RECT  53.472 0 53.496 0.084 ;
    END
  END d[320]
  PIN d[321]
    DIRECTION INPUT ;
    USE SIGNAL ;
    PORT
      LAYER M5 ;
        RECT  53.76 0 53.784 0.084 ;
    END
  END d[321]
  PIN d[322]
    DIRECTION INPUT ;
    USE SIGNAL ;
    PORT
      LAYER M5 ;
        RECT  54.048 0 54.072 0.084 ;
    END
  END d[322]
  PIN d[323]
    DIRECTION INPUT ;
    USE SIGNAL ;
    PORT
      LAYER M5 ;
        RECT  53.904 0 53.928 0.084 ;
    END
  END d[323]
  PIN d[324]
    DIRECTION INPUT ;
    USE SIGNAL ;
    PORT
      LAYER M5 ;
        RECT  54.336 0 54.36 0.084 ;
    END
  END d[324]
  PIN d[325]
    DIRECTION INPUT ;
    USE SIGNAL ;
    PORT
      LAYER M5 ;
        RECT  54.192 0 54.216 0.084 ;
    END
  END d[325]
  PIN d[326]
    DIRECTION INPUT ;
    USE SIGNAL ;
    PORT
      LAYER M5 ;
        RECT  54.624 0 54.648 0.084 ;
    END
  END d[326]
  PIN d[327]
    DIRECTION INPUT ;
    USE SIGNAL ;
    PORT
      LAYER M5 ;
        RECT  54.48 0 54.504 0.084 ;
    END
  END d[327]
  PIN d[328]
    DIRECTION INPUT ;
    USE SIGNAL ;
    PORT
      LAYER M5 ;
        RECT  54.912 0 54.936 0.084 ;
    END
  END d[328]
  PIN d[329]
    DIRECTION INPUT ;
    USE SIGNAL ;
    PORT
      LAYER M5 ;
        RECT  54.768 0 54.792 0.084 ;
    END
  END d[329]
  PIN d[32]
    DIRECTION INPUT ;
    USE SIGNAL ;
    PORT
      LAYER M5 ;
        RECT  12 0 12.024 0.084 ;
    END
  END d[32]
  PIN d[330]
    DIRECTION INPUT ;
    USE SIGNAL ;
    PORT
      LAYER M5 ;
        RECT  55.2 0 55.224 0.084 ;
    END
  END d[330]
  PIN d[331]
    DIRECTION INPUT ;
    USE SIGNAL ;
    PORT
      LAYER M5 ;
        RECT  55.056 0 55.08 0.084 ;
    END
  END d[331]
  PIN d[332]
    DIRECTION INPUT ;
    USE SIGNAL ;
    PORT
      LAYER M5 ;
        RECT  55.488 0 55.512 0.084 ;
    END
  END d[332]
  PIN d[333]
    DIRECTION INPUT ;
    USE SIGNAL ;
    PORT
      LAYER M5 ;
        RECT  55.344 0 55.368 0.084 ;
    END
  END d[333]
  PIN d[334]
    DIRECTION INPUT ;
    USE SIGNAL ;
    PORT
      LAYER M5 ;
        RECT  55.632 0 55.656 0.084 ;
    END
  END d[334]
  PIN d[335]
    DIRECTION INPUT ;
    USE SIGNAL ;
    PORT
      LAYER M5 ;
        RECT  55.776 0 55.8 0.084 ;
    END
  END d[335]
  PIN d[336]
    DIRECTION INPUT ;
    USE SIGNAL ;
    PORT
      LAYER M5 ;
        RECT  55.92 0 55.944 0.084 ;
    END
  END d[336]
  PIN d[337]
    DIRECTION INPUT ;
    USE SIGNAL ;
    PORT
      LAYER M5 ;
        RECT  56.064 0 56.088 0.084 ;
    END
  END d[337]
  PIN d[338]
    DIRECTION INPUT ;
    USE SIGNAL ;
    PORT
      LAYER M5 ;
        RECT  56.208 0 56.232 0.084 ;
    END
  END d[338]
  PIN d[339]
    DIRECTION INPUT ;
    USE SIGNAL ;
    PORT
      LAYER M5 ;
        RECT  56.352 0 56.376 0.084 ;
    END
  END d[339]
  PIN d[33]
    DIRECTION INPUT ;
    USE SIGNAL ;
    PORT
      LAYER M5 ;
        RECT  11.856 0 11.88 0.084 ;
    END
  END d[33]
  PIN d[340]
    DIRECTION INPUT ;
    USE SIGNAL ;
    PORT
      LAYER M5 ;
        RECT  56.496 0 56.52 0.084 ;
    END
  END d[340]
  PIN d[341]
    DIRECTION INPUT ;
    USE SIGNAL ;
    PORT
      LAYER M5 ;
        RECT  56.64 0 56.664 0.084 ;
    END
  END d[341]
  PIN d[342]
    DIRECTION INPUT ;
    USE SIGNAL ;
    PORT
      LAYER M5 ;
        RECT  56.784 0 56.808 0.084 ;
    END
  END d[342]
  PIN d[343]
    DIRECTION INPUT ;
    USE SIGNAL ;
    PORT
      LAYER M5 ;
        RECT  56.928 0 56.952 0.084 ;
    END
  END d[343]
  PIN d[344]
    DIRECTION INPUT ;
    USE SIGNAL ;
    PORT
      LAYER M5 ;
        RECT  57.072 0 57.096 0.084 ;
    END
  END d[344]
  PIN d[345]
    DIRECTION INPUT ;
    USE SIGNAL ;
    PORT
      LAYER M5 ;
        RECT  57.216 0 57.24 0.084 ;
    END
  END d[345]
  PIN d[346]
    DIRECTION INPUT ;
    USE SIGNAL ;
    PORT
      LAYER M5 ;
        RECT  57.36 0 57.384 0.084 ;
    END
  END d[346]
  PIN d[347]
    DIRECTION INPUT ;
    USE SIGNAL ;
    PORT
      LAYER M5 ;
        RECT  57.504 0 57.528 0.084 ;
    END
  END d[347]
  PIN d[348]
    DIRECTION INPUT ;
    USE SIGNAL ;
    PORT
      LAYER M5 ;
        RECT  57.648 0 57.672 0.084 ;
    END
  END d[348]
  PIN d[349]
    DIRECTION INPUT ;
    USE SIGNAL ;
    PORT
      LAYER M5 ;
        RECT  57.792 0 57.816 0.084 ;
    END
  END d[349]
  PIN d[34]
    DIRECTION INPUT ;
    USE SIGNAL ;
    PORT
      LAYER M5 ;
        RECT  12.288 0 12.312 0.084 ;
    END
  END d[34]
  PIN d[350]
    DIRECTION INPUT ;
    USE SIGNAL ;
    PORT
      LAYER M5 ;
        RECT  57.936 0 57.96 0.084 ;
    END
  END d[350]
  PIN d[351]
    DIRECTION INPUT ;
    USE SIGNAL ;
    PORT
      LAYER M5 ;
        RECT  58.224 0 58.248 0.084 ;
    END
  END d[351]
  PIN d[352]
    DIRECTION INPUT ;
    USE SIGNAL ;
    PORT
      LAYER M5 ;
        RECT  58.08 0 58.104 0.084 ;
    END
  END d[352]
  PIN d[353]
    DIRECTION INPUT ;
    USE SIGNAL ;
    PORT
      LAYER M5 ;
        RECT  58.512 0 58.536 0.084 ;
    END
  END d[353]
  PIN d[354]
    DIRECTION INPUT ;
    USE SIGNAL ;
    PORT
      LAYER M5 ;
        RECT  58.368 0 58.392 0.084 ;
    END
  END d[354]
  PIN d[355]
    DIRECTION INPUT ;
    USE SIGNAL ;
    PORT
      LAYER M5 ;
        RECT  58.8 0 58.824 0.084 ;
    END
  END d[355]
  PIN d[356]
    DIRECTION INPUT ;
    USE SIGNAL ;
    PORT
      LAYER M5 ;
        RECT  58.656 0 58.68 0.084 ;
    END
  END d[356]
  PIN d[357]
    DIRECTION INPUT ;
    USE SIGNAL ;
    PORT
      LAYER M5 ;
        RECT  59.088 0 59.112 0.084 ;
    END
  END d[357]
  PIN d[358]
    DIRECTION INPUT ;
    USE SIGNAL ;
    PORT
      LAYER M5 ;
        RECT  58.944 0 58.968 0.084 ;
    END
  END d[358]
  PIN d[359]
    DIRECTION INPUT ;
    USE SIGNAL ;
    PORT
      LAYER M5 ;
        RECT  59.52 0 59.544 0.084 ;
    END
  END d[359]
  PIN d[35]
    DIRECTION INPUT ;
    USE SIGNAL ;
    PORT
      LAYER M5 ;
        RECT  12.144 0 12.168 0.084 ;
    END
  END d[35]
  PIN d[360]
    DIRECTION INPUT ;
    USE SIGNAL ;
    PORT
      LAYER M5 ;
        RECT  59.232 0 59.256 0.084 ;
    END
  END d[360]
  PIN d[361]
    DIRECTION INPUT ;
    USE SIGNAL ;
    PORT
      LAYER M5 ;
        RECT  59.664 0 59.688 0.084 ;
    END
  END d[361]
  PIN d[362]
    DIRECTION INPUT ;
    USE SIGNAL ;
    PORT
      LAYER M5 ;
        RECT  59.376 0 59.4 0.084 ;
    END
  END d[362]
  PIN d[363]
    DIRECTION INPUT ;
    USE SIGNAL ;
    PORT
      LAYER M5 ;
        RECT  59.952 0 59.976 0.084 ;
    END
  END d[363]
  PIN d[364]
    DIRECTION INPUT ;
    USE SIGNAL ;
    PORT
      LAYER M5 ;
        RECT  59.808 0 59.832 0.084 ;
    END
  END d[364]
  PIN d[365]
    DIRECTION INPUT ;
    USE SIGNAL ;
    PORT
      LAYER M5 ;
        RECT  60.24 0 60.264 0.084 ;
    END
  END d[365]
  PIN d[366]
    DIRECTION INPUT ;
    USE SIGNAL ;
    PORT
      LAYER M5 ;
        RECT  60.096 0 60.12 0.084 ;
    END
  END d[366]
  PIN d[367]
    DIRECTION INPUT ;
    USE SIGNAL ;
    PORT
      LAYER M5 ;
        RECT  60.672 0 60.696 0.084 ;
    END
  END d[367]
  PIN d[368]
    DIRECTION INPUT ;
    USE SIGNAL ;
    PORT
      LAYER M5 ;
        RECT  60.384 0 60.408 0.084 ;
    END
  END d[368]
  PIN d[369]
    DIRECTION INPUT ;
    USE SIGNAL ;
    PORT
      LAYER M5 ;
        RECT  60.96 0 60.984 0.084 ;
    END
  END d[369]
  PIN d[36]
    DIRECTION INPUT ;
    USE SIGNAL ;
    PORT
      LAYER M5 ;
        RECT  12.576 0 12.6 0.084 ;
    END
  END d[36]
  PIN d[370]
    DIRECTION INPUT ;
    USE SIGNAL ;
    PORT
      LAYER M5 ;
        RECT  60.528 0 60.552 0.084 ;
    END
  END d[370]
  PIN d[371]
    DIRECTION INPUT ;
    USE SIGNAL ;
    PORT
      LAYER M5 ;
        RECT  61.104 0 61.128 0.084 ;
    END
  END d[371]
  PIN d[372]
    DIRECTION INPUT ;
    USE SIGNAL ;
    PORT
      LAYER M5 ;
        RECT  60.816 0 60.84 0.084 ;
    END
  END d[372]
  PIN d[373]
    DIRECTION INPUT ;
    USE SIGNAL ;
    PORT
      LAYER M5 ;
        RECT  61.248 0 61.272 0.084 ;
    END
  END d[373]
  PIN d[374]
    DIRECTION INPUT ;
    USE SIGNAL ;
    PORT
      LAYER M5 ;
        RECT  61.536 0 61.56 0.084 ;
    END
  END d[374]
  PIN d[375]
    DIRECTION INPUT ;
    USE SIGNAL ;
    PORT
      LAYER M5 ;
        RECT  61.392 0 61.416 0.084 ;
    END
  END d[375]
  PIN d[376]
    DIRECTION INPUT ;
    USE SIGNAL ;
    PORT
      LAYER M5 ;
        RECT  61.824 0 61.848 0.084 ;
    END
  END d[376]
  PIN d[377]
    DIRECTION INPUT ;
    USE SIGNAL ;
    PORT
      LAYER M5 ;
        RECT  61.68 0 61.704 0.084 ;
    END
  END d[377]
  PIN d[378]
    DIRECTION INPUT ;
    USE SIGNAL ;
    PORT
      LAYER M5 ;
        RECT  62.112 0 62.136 0.084 ;
    END
  END d[378]
  PIN d[379]
    DIRECTION INPUT ;
    USE SIGNAL ;
    PORT
      LAYER M5 ;
        RECT  61.968 0 61.992 0.084 ;
    END
  END d[379]
  PIN d[37]
    DIRECTION INPUT ;
    USE SIGNAL ;
    PORT
      LAYER M5 ;
        RECT  12.432 0 12.456 0.084 ;
    END
  END d[37]
  PIN d[380]
    DIRECTION INPUT ;
    USE SIGNAL ;
    PORT
      LAYER M5 ;
        RECT  62.4 0 62.424 0.084 ;
    END
  END d[380]
  PIN d[381]
    DIRECTION INPUT ;
    USE SIGNAL ;
    PORT
      LAYER M5 ;
        RECT  62.256 0 62.28 0.084 ;
    END
  END d[381]
  PIN d[382]
    DIRECTION INPUT ;
    USE SIGNAL ;
    PORT
      LAYER M5 ;
        RECT  62.688 0 62.712 0.084 ;
    END
  END d[382]
  PIN d[383]
    DIRECTION INPUT ;
    USE SIGNAL ;
    PORT
      LAYER M5 ;
        RECT  62.544 0 62.568 0.084 ;
    END
  END d[383]
  PIN d[384]
    DIRECTION INPUT ;
    USE SIGNAL ;
    PORT
      LAYER M5 ;
        RECT  62.832 0 62.856 0.084 ;
    END
  END d[384]
  PIN d[385]
    DIRECTION INPUT ;
    USE SIGNAL ;
    PORT
      LAYER M5 ;
        RECT  62.976 0 63 0.084 ;
    END
  END d[385]
  PIN d[386]
    DIRECTION INPUT ;
    USE SIGNAL ;
    PORT
      LAYER M5 ;
        RECT  63.12 0 63.144 0.084 ;
    END
  END d[386]
  PIN d[387]
    DIRECTION INPUT ;
    USE SIGNAL ;
    PORT
      LAYER M5 ;
        RECT  63.264 0 63.288 0.084 ;
    END
  END d[387]
  PIN d[388]
    DIRECTION INPUT ;
    USE SIGNAL ;
    PORT
      LAYER M5 ;
        RECT  63.408 0 63.432 0.084 ;
    END
  END d[388]
  PIN d[389]
    DIRECTION INPUT ;
    USE SIGNAL ;
    PORT
      LAYER M5 ;
        RECT  63.552 0 63.576 0.084 ;
    END
  END d[389]
  PIN d[38]
    DIRECTION INPUT ;
    USE SIGNAL ;
    PORT
      LAYER M5 ;
        RECT  12.72 0 12.744 0.084 ;
    END
  END d[38]
  PIN d[390]
    DIRECTION INPUT ;
    USE SIGNAL ;
    PORT
      LAYER M5 ;
        RECT  63.696 0 63.72 0.084 ;
    END
  END d[390]
  PIN d[391]
    DIRECTION INPUT ;
    USE SIGNAL ;
    PORT
      LAYER M5 ;
        RECT  63.84 0 63.864 0.084 ;
    END
  END d[391]
  PIN d[392]
    DIRECTION INPUT ;
    USE SIGNAL ;
    PORT
      LAYER M5 ;
        RECT  63.984 0 64.008 0.084 ;
    END
  END d[392]
  PIN d[393]
    DIRECTION INPUT ;
    USE SIGNAL ;
    PORT
      LAYER M5 ;
        RECT  64.128 0 64.152 0.084 ;
    END
  END d[393]
  PIN d[394]
    DIRECTION INPUT ;
    USE SIGNAL ;
    PORT
      LAYER M5 ;
        RECT  64.272 0 64.296 0.084 ;
    END
  END d[394]
  PIN d[395]
    DIRECTION INPUT ;
    USE SIGNAL ;
    PORT
      LAYER M5 ;
        RECT  64.416 0 64.44 0.084 ;
    END
  END d[395]
  PIN d[396]
    DIRECTION INPUT ;
    USE SIGNAL ;
    PORT
      LAYER M5 ;
        RECT  64.56 0 64.584 0.084 ;
    END
  END d[396]
  PIN d[397]
    DIRECTION INPUT ;
    USE SIGNAL ;
    PORT
      LAYER M5 ;
        RECT  64.704 0 64.728 0.084 ;
    END
  END d[397]
  PIN d[398]
    DIRECTION INPUT ;
    USE SIGNAL ;
    PORT
      LAYER M5 ;
        RECT  64.848 0 64.872 0.084 ;
    END
  END d[398]
  PIN d[399]
    DIRECTION INPUT ;
    USE SIGNAL ;
    PORT
      LAYER M5 ;
        RECT  65.136 0 65.16 0.084 ;
    END
  END d[399]
  PIN d[39]
    DIRECTION INPUT ;
    USE SIGNAL ;
    PORT
      LAYER M5 ;
        RECT  12.864 0 12.888 0.084 ;
    END
  END d[39]
  PIN d[3]
    DIRECTION INPUT ;
    USE SIGNAL ;
    PORT
      LAYER M5 ;
        RECT  7.68 0 7.704 0.084 ;
    END
  END d[3]
  PIN d[400]
    DIRECTION INPUT ;
    USE SIGNAL ;
    PORT
      LAYER M5 ;
        RECT  64.992 0 65.016 0.084 ;
    END
  END d[400]
  PIN d[401]
    DIRECTION INPUT ;
    USE SIGNAL ;
    PORT
      LAYER M5 ;
        RECT  65.424 0 65.448 0.084 ;
    END
  END d[401]
  PIN d[402]
    DIRECTION INPUT ;
    USE SIGNAL ;
    PORT
      LAYER M5 ;
        RECT  65.28 0 65.304 0.084 ;
    END
  END d[402]
  PIN d[403]
    DIRECTION INPUT ;
    USE SIGNAL ;
    PORT
      LAYER M5 ;
        RECT  65.712 0 65.736 0.084 ;
    END
  END d[403]
  PIN d[404]
    DIRECTION INPUT ;
    USE SIGNAL ;
    PORT
      LAYER M5 ;
        RECT  65.568 0 65.592 0.084 ;
    END
  END d[404]
  PIN d[405]
    DIRECTION INPUT ;
    USE SIGNAL ;
    PORT
      LAYER M5 ;
        RECT  66 0 66.024 0.084 ;
    END
  END d[405]
  PIN d[406]
    DIRECTION INPUT ;
    USE SIGNAL ;
    PORT
      LAYER M5 ;
        RECT  65.856 0 65.88 0.084 ;
    END
  END d[406]
  PIN d[407]
    DIRECTION INPUT ;
    USE SIGNAL ;
    PORT
      LAYER M5 ;
        RECT  66.288 0 66.312 0.084 ;
    END
  END d[407]
  PIN d[408]
    DIRECTION INPUT ;
    USE SIGNAL ;
    PORT
      LAYER M5 ;
        RECT  66.144 0 66.168 0.084 ;
    END
  END d[408]
  PIN d[409]
    DIRECTION INPUT ;
    USE SIGNAL ;
    PORT
      LAYER M5 ;
        RECT  66.72 0 66.744 0.084 ;
    END
  END d[409]
  PIN d[40]
    DIRECTION INPUT ;
    USE SIGNAL ;
    PORT
      LAYER M5 ;
        RECT  13.008 0 13.032 0.084 ;
    END
  END d[40]
  PIN d[410]
    DIRECTION INPUT ;
    USE SIGNAL ;
    PORT
      LAYER M5 ;
        RECT  66.432 0 66.456 0.084 ;
    END
  END d[410]
  PIN d[411]
    DIRECTION INPUT ;
    USE SIGNAL ;
    PORT
      LAYER M5 ;
        RECT  66.864 0 66.888 0.084 ;
    END
  END d[411]
  PIN d[412]
    DIRECTION INPUT ;
    USE SIGNAL ;
    PORT
      LAYER M5 ;
        RECT  66.576 0 66.6 0.084 ;
    END
  END d[412]
  PIN d[413]
    DIRECTION INPUT ;
    USE SIGNAL ;
    PORT
      LAYER M5 ;
        RECT  67.296 0 67.32 0.084 ;
    END
  END d[413]
  PIN d[414]
    DIRECTION INPUT ;
    USE SIGNAL ;
    PORT
      LAYER M5 ;
        RECT  67.008 0 67.032 0.084 ;
    END
  END d[414]
  PIN d[415]
    DIRECTION INPUT ;
    USE SIGNAL ;
    PORT
      LAYER M5 ;
        RECT  67.584 0 67.608 0.084 ;
    END
  END d[415]
  PIN d[416]
    DIRECTION INPUT ;
    USE SIGNAL ;
    PORT
      LAYER M5 ;
        RECT  67.152 0 67.176 0.084 ;
    END
  END d[416]
  PIN d[417]
    DIRECTION INPUT ;
    USE SIGNAL ;
    PORT
      LAYER M5 ;
        RECT  67.872 0 67.896 0.084 ;
    END
  END d[417]
  PIN d[418]
    DIRECTION INPUT ;
    USE SIGNAL ;
    PORT
      LAYER M5 ;
        RECT  67.44 0 67.464 0.084 ;
    END
  END d[418]
  PIN d[419]
    DIRECTION INPUT ;
    USE SIGNAL ;
    PORT
      LAYER M5 ;
        RECT  68.16 0 68.184 0.084 ;
    END
  END d[419]
  PIN d[41]
    DIRECTION INPUT ;
    USE SIGNAL ;
    PORT
      LAYER M5 ;
        RECT  13.152 0 13.176 0.084 ;
    END
  END d[41]
  PIN d[420]
    DIRECTION INPUT ;
    USE SIGNAL ;
    PORT
      LAYER M5 ;
        RECT  67.728 0 67.752 0.084 ;
    END
  END d[420]
  PIN d[421]
    DIRECTION INPUT ;
    USE SIGNAL ;
    PORT
      LAYER M5 ;
        RECT  68.304 0 68.328 0.084 ;
    END
  END d[421]
  PIN d[422]
    DIRECTION INPUT ;
    USE SIGNAL ;
    PORT
      LAYER M5 ;
        RECT  68.016 0 68.04 0.084 ;
    END
  END d[422]
  PIN d[423]
    DIRECTION INPUT ;
    USE SIGNAL ;
    PORT
      LAYER M5 ;
        RECT  68.448 0 68.472 0.084 ;
    END
  END d[423]
  PIN d[424]
    DIRECTION INPUT ;
    USE SIGNAL ;
    PORT
      LAYER M5 ;
        RECT  68.736 0 68.76 0.084 ;
    END
  END d[424]
  PIN d[425]
    DIRECTION INPUT ;
    USE SIGNAL ;
    PORT
      LAYER M5 ;
        RECT  68.592 0 68.616 0.084 ;
    END
  END d[425]
  PIN d[426]
    DIRECTION INPUT ;
    USE SIGNAL ;
    PORT
      LAYER M5 ;
        RECT  69.024 0 69.048 0.084 ;
    END
  END d[426]
  PIN d[427]
    DIRECTION INPUT ;
    USE SIGNAL ;
    PORT
      LAYER M5 ;
        RECT  68.88 0 68.904 0.084 ;
    END
  END d[427]
  PIN d[428]
    DIRECTION INPUT ;
    USE SIGNAL ;
    PORT
      LAYER M5 ;
        RECT  69.312 0 69.336 0.084 ;
    END
  END d[428]
  PIN d[429]
    DIRECTION INPUT ;
    USE SIGNAL ;
    PORT
      LAYER M5 ;
        RECT  69.168 0 69.192 0.084 ;
    END
  END d[429]
  PIN d[42]
    DIRECTION INPUT ;
    USE SIGNAL ;
    PORT
      LAYER M5 ;
        RECT  13.296 0 13.32 0.084 ;
    END
  END d[42]
  PIN d[430]
    DIRECTION INPUT ;
    USE SIGNAL ;
    PORT
      LAYER M5 ;
        RECT  69.6 0 69.624 0.084 ;
    END
  END d[430]
  PIN d[431]
    DIRECTION INPUT ;
    USE SIGNAL ;
    PORT
      LAYER M5 ;
        RECT  69.456 0 69.48 0.084 ;
    END
  END d[431]
  PIN d[432]
    DIRECTION INPUT ;
    USE SIGNAL ;
    PORT
      LAYER M5 ;
        RECT  69.888 0 69.912 0.084 ;
    END
  END d[432]
  PIN d[433]
    DIRECTION INPUT ;
    USE SIGNAL ;
    PORT
      LAYER M5 ;
        RECT  69.744 0 69.768 0.084 ;
    END
  END d[433]
  PIN d[434]
    DIRECTION INPUT ;
    USE SIGNAL ;
    PORT
      LAYER M5 ;
        RECT  70.032 0 70.056 0.084 ;
    END
  END d[434]
  PIN d[435]
    DIRECTION INPUT ;
    USE SIGNAL ;
    PORT
      LAYER M5 ;
        RECT  70.176 0 70.2 0.084 ;
    END
  END d[435]
  PIN d[436]
    DIRECTION INPUT ;
    USE SIGNAL ;
    PORT
      LAYER M5 ;
        RECT  70.32 0 70.344 0.084 ;
    END
  END d[436]
  PIN d[437]
    DIRECTION INPUT ;
    USE SIGNAL ;
    PORT
      LAYER M5 ;
        RECT  70.464 0 70.488 0.084 ;
    END
  END d[437]
  PIN d[438]
    DIRECTION INPUT ;
    USE SIGNAL ;
    PORT
      LAYER M5 ;
        RECT  70.608 0 70.632 0.084 ;
    END
  END d[438]
  PIN d[439]
    DIRECTION INPUT ;
    USE SIGNAL ;
    PORT
      LAYER M5 ;
        RECT  70.752 0 70.776 0.084 ;
    END
  END d[439]
  PIN d[43]
    DIRECTION INPUT ;
    USE SIGNAL ;
    PORT
      LAYER M5 ;
        RECT  13.44 0 13.464 0.084 ;
    END
  END d[43]
  PIN d[440]
    DIRECTION INPUT ;
    USE SIGNAL ;
    PORT
      LAYER M5 ;
        RECT  70.896 0 70.92 0.084 ;
    END
  END d[440]
  PIN d[441]
    DIRECTION INPUT ;
    USE SIGNAL ;
    PORT
      LAYER M5 ;
        RECT  71.04 0 71.064 0.084 ;
    END
  END d[441]
  PIN d[442]
    DIRECTION INPUT ;
    USE SIGNAL ;
    PORT
      LAYER M5 ;
        RECT  71.184 0 71.208 0.084 ;
    END
  END d[442]
  PIN d[443]
    DIRECTION INPUT ;
    USE SIGNAL ;
    PORT
      LAYER M5 ;
        RECT  71.328 0 71.352 0.084 ;
    END
  END d[443]
  PIN d[444]
    DIRECTION INPUT ;
    USE SIGNAL ;
    PORT
      LAYER M5 ;
        RECT  71.472 0 71.496 0.084 ;
    END
  END d[444]
  PIN d[445]
    DIRECTION INPUT ;
    USE SIGNAL ;
    PORT
      LAYER M5 ;
        RECT  71.616 0 71.64 0.084 ;
    END
  END d[445]
  PIN d[446]
    DIRECTION INPUT ;
    USE SIGNAL ;
    PORT
      LAYER M5 ;
        RECT  71.76 0 71.784 0.084 ;
    END
  END d[446]
  PIN d[447]
    DIRECTION INPUT ;
    USE SIGNAL ;
    PORT
      LAYER M5 ;
        RECT  71.904 0 71.928 0.084 ;
    END
  END d[447]
  PIN d[448]
    DIRECTION INPUT ;
    USE SIGNAL ;
    PORT
      LAYER M5 ;
        RECT  72.048 0 72.072 0.084 ;
    END
  END d[448]
  PIN d[449]
    DIRECTION INPUT ;
    USE SIGNAL ;
    PORT
      LAYER M5 ;
        RECT  72.336 0 72.36 0.084 ;
    END
  END d[449]
  PIN d[44]
    DIRECTION INPUT ;
    USE SIGNAL ;
    PORT
      LAYER M5 ;
        RECT  13.584 0 13.608 0.084 ;
    END
  END d[44]
  PIN d[450]
    DIRECTION INPUT ;
    USE SIGNAL ;
    PORT
      LAYER M5 ;
        RECT  72.192 0 72.216 0.084 ;
    END
  END d[450]
  PIN d[451]
    DIRECTION INPUT ;
    USE SIGNAL ;
    PORT
      LAYER M5 ;
        RECT  72.624 0 72.648 0.084 ;
    END
  END d[451]
  PIN d[452]
    DIRECTION INPUT ;
    USE SIGNAL ;
    PORT
      LAYER M5 ;
        RECT  72.48 0 72.504 0.084 ;
    END
  END d[452]
  PIN d[453]
    DIRECTION INPUT ;
    USE SIGNAL ;
    PORT
      LAYER M5 ;
        RECT  72.912 0 72.936 0.084 ;
    END
  END d[453]
  PIN d[454]
    DIRECTION INPUT ;
    USE SIGNAL ;
    PORT
      LAYER M5 ;
        RECT  72.768 0 72.792 0.084 ;
    END
  END d[454]
  PIN d[455]
    DIRECTION INPUT ;
    USE SIGNAL ;
    PORT
      LAYER M5 ;
        RECT  73.2 0 73.224 0.084 ;
    END
  END d[455]
  PIN d[456]
    DIRECTION INPUT ;
    USE SIGNAL ;
    PORT
      LAYER M5 ;
        RECT  73.056 0 73.08 0.084 ;
    END
  END d[456]
  PIN d[457]
    DIRECTION INPUT ;
    USE SIGNAL ;
    PORT
      LAYER M5 ;
        RECT  73.488 0 73.512 0.084 ;
    END
  END d[457]
  PIN d[458]
    DIRECTION INPUT ;
    USE SIGNAL ;
    PORT
      LAYER M5 ;
        RECT  73.344 0 73.368 0.084 ;
    END
  END d[458]
  PIN d[459]
    DIRECTION INPUT ;
    USE SIGNAL ;
    PORT
      LAYER M5 ;
        RECT  73.92 0 73.944 0.084 ;
    END
  END d[459]
  PIN d[45]
    DIRECTION INPUT ;
    USE SIGNAL ;
    PORT
      LAYER M5 ;
        RECT  13.728 0 13.752 0.084 ;
    END
  END d[45]
  PIN d[460]
    DIRECTION INPUT ;
    USE SIGNAL ;
    PORT
      LAYER M5 ;
        RECT  73.632 0 73.656 0.084 ;
    END
  END d[460]
  PIN d[461]
    DIRECTION INPUT ;
    USE SIGNAL ;
    PORT
      LAYER M5 ;
        RECT  74.064 0 74.088 0.084 ;
    END
  END d[461]
  PIN d[462]
    DIRECTION INPUT ;
    USE SIGNAL ;
    PORT
      LAYER M5 ;
        RECT  73.776 0 73.8 0.084 ;
    END
  END d[462]
  PIN d[463]
    DIRECTION INPUT ;
    USE SIGNAL ;
    PORT
      LAYER M5 ;
        RECT  74.496 0 74.52 0.084 ;
    END
  END d[463]
  PIN d[464]
    DIRECTION INPUT ;
    USE SIGNAL ;
    PORT
      LAYER M5 ;
        RECT  74.208 0 74.232 0.084 ;
    END
  END d[464]
  PIN d[465]
    DIRECTION INPUT ;
    USE SIGNAL ;
    PORT
      LAYER M5 ;
        RECT  74.784 0 74.808 0.084 ;
    END
  END d[465]
  PIN d[466]
    DIRECTION INPUT ;
    USE SIGNAL ;
    PORT
      LAYER M5 ;
        RECT  74.352 0 74.376 0.084 ;
    END
  END d[466]
  PIN d[467]
    DIRECTION INPUT ;
    USE SIGNAL ;
    PORT
      LAYER M5 ;
        RECT  75.072 0 75.096 0.084 ;
    END
  END d[467]
  PIN d[468]
    DIRECTION INPUT ;
    USE SIGNAL ;
    PORT
      LAYER M5 ;
        RECT  74.64 0 74.664 0.084 ;
    END
  END d[468]
  PIN d[469]
    DIRECTION INPUT ;
    USE SIGNAL ;
    PORT
      LAYER M5 ;
        RECT  75.36 0 75.384 0.084 ;
    END
  END d[469]
  PIN d[46]
    DIRECTION INPUT ;
    USE SIGNAL ;
    PORT
      LAYER M5 ;
        RECT  13.872 0 13.896 0.084 ;
    END
  END d[46]
  PIN d[470]
    DIRECTION INPUT ;
    USE SIGNAL ;
    PORT
      LAYER M5 ;
        RECT  74.928 0 74.952 0.084 ;
    END
  END d[470]
  PIN d[471]
    DIRECTION INPUT ;
    USE SIGNAL ;
    PORT
      LAYER M5 ;
        RECT  75.504 0 75.528 0.084 ;
    END
  END d[471]
  PIN d[472]
    DIRECTION INPUT ;
    USE SIGNAL ;
    PORT
      LAYER M5 ;
        RECT  75.216 0 75.24 0.084 ;
    END
  END d[472]
  PIN d[473]
    DIRECTION INPUT ;
    USE SIGNAL ;
    PORT
      LAYER M5 ;
        RECT  75.648 0 75.672 0.084 ;
    END
  END d[473]
  PIN d[474]
    DIRECTION INPUT ;
    USE SIGNAL ;
    PORT
      LAYER M5 ;
        RECT  75.936 0 75.96 0.084 ;
    END
  END d[474]
  PIN d[475]
    DIRECTION INPUT ;
    USE SIGNAL ;
    PORT
      LAYER M5 ;
        RECT  75.792 0 75.816 0.084 ;
    END
  END d[475]
  PIN d[476]
    DIRECTION INPUT ;
    USE SIGNAL ;
    PORT
      LAYER M5 ;
        RECT  76.224 0 76.248 0.084 ;
    END
  END d[476]
  PIN d[477]
    DIRECTION INPUT ;
    USE SIGNAL ;
    PORT
      LAYER M5 ;
        RECT  76.08 0 76.104 0.084 ;
    END
  END d[477]
  PIN d[478]
    DIRECTION INPUT ;
    USE SIGNAL ;
    PORT
      LAYER M5 ;
        RECT  76.512 0 76.536 0.084 ;
    END
  END d[478]
  PIN d[479]
    DIRECTION INPUT ;
    USE SIGNAL ;
    PORT
      LAYER M5 ;
        RECT  76.368 0 76.392 0.084 ;
    END
  END d[479]
  PIN d[47]
    DIRECTION INPUT ;
    USE SIGNAL ;
    PORT
      LAYER M5 ;
        RECT  14.016 0 14.04 0.084 ;
    END
  END d[47]
  PIN d[480]
    DIRECTION INPUT ;
    USE SIGNAL ;
    PORT
      LAYER M5 ;
        RECT  76.8 0 76.824 0.084 ;
    END
  END d[480]
  PIN d[481]
    DIRECTION INPUT ;
    USE SIGNAL ;
    PORT
      LAYER M5 ;
        RECT  76.656 0 76.68 0.084 ;
    END
  END d[481]
  PIN d[482]
    DIRECTION INPUT ;
    USE SIGNAL ;
    PORT
      LAYER M5 ;
        RECT  77.088 0 77.112 0.084 ;
    END
  END d[482]
  PIN d[483]
    DIRECTION INPUT ;
    USE SIGNAL ;
    PORT
      LAYER M5 ;
        RECT  76.944 0 76.968 0.084 ;
    END
  END d[483]
  PIN d[484]
    DIRECTION INPUT ;
    USE SIGNAL ;
    PORT
      LAYER M5 ;
        RECT  77.232 0 77.256 0.084 ;
    END
  END d[484]
  PIN d[485]
    DIRECTION INPUT ;
    USE SIGNAL ;
    PORT
      LAYER M5 ;
        RECT  77.376 0 77.4 0.084 ;
    END
  END d[485]
  PIN d[486]
    DIRECTION INPUT ;
    USE SIGNAL ;
    PORT
      LAYER M5 ;
        RECT  77.52 0 77.544 0.084 ;
    END
  END d[486]
  PIN d[487]
    DIRECTION INPUT ;
    USE SIGNAL ;
    PORT
      LAYER M5 ;
        RECT  77.664 0 77.688 0.084 ;
    END
  END d[487]
  PIN d[488]
    DIRECTION INPUT ;
    USE SIGNAL ;
    PORT
      LAYER M5 ;
        RECT  77.808 0 77.832 0.084 ;
    END
  END d[488]
  PIN d[489]
    DIRECTION INPUT ;
    USE SIGNAL ;
    PORT
      LAYER M5 ;
        RECT  77.952 0 77.976 0.084 ;
    END
  END d[489]
  PIN d[48]
    DIRECTION INPUT ;
    USE SIGNAL ;
    PORT
      LAYER M5 ;
        RECT  14.16 0 14.184 0.084 ;
    END
  END d[48]
  PIN d[490]
    DIRECTION INPUT ;
    USE SIGNAL ;
    PORT
      LAYER M5 ;
        RECT  78.096 0 78.12 0.084 ;
    END
  END d[490]
  PIN d[491]
    DIRECTION INPUT ;
    USE SIGNAL ;
    PORT
      LAYER M5 ;
        RECT  78.24 0 78.264 0.084 ;
    END
  END d[491]
  PIN d[492]
    DIRECTION INPUT ;
    USE SIGNAL ;
    PORT
      LAYER M5 ;
        RECT  78.384 0 78.408 0.084 ;
    END
  END d[492]
  PIN d[493]
    DIRECTION INPUT ;
    USE SIGNAL ;
    PORT
      LAYER M5 ;
        RECT  78.528 0 78.552 0.084 ;
    END
  END d[493]
  PIN d[494]
    DIRECTION INPUT ;
    USE SIGNAL ;
    PORT
      LAYER M5 ;
        RECT  78.672 0 78.696 0.084 ;
    END
  END d[494]
  PIN d[495]
    DIRECTION INPUT ;
    USE SIGNAL ;
    PORT
      LAYER M5 ;
        RECT  78.816 0 78.84 0.084 ;
    END
  END d[495]
  PIN d[496]
    DIRECTION INPUT ;
    USE SIGNAL ;
    PORT
      LAYER M5 ;
        RECT  78.96 0 78.984 0.084 ;
    END
  END d[496]
  PIN d[497]
    DIRECTION INPUT ;
    USE SIGNAL ;
    PORT
      LAYER M5 ;
        RECT  79.104 0 79.128 0.084 ;
    END
  END d[497]
  PIN d[498]
    DIRECTION INPUT ;
    USE SIGNAL ;
    PORT
      LAYER M5 ;
        RECT  79.248 0 79.272 0.084 ;
    END
  END d[498]
  PIN d[499]
    DIRECTION INPUT ;
    USE SIGNAL ;
    PORT
      LAYER M5 ;
        RECT  79.536 0 79.56 0.084 ;
    END
  END d[499]
  PIN d[49]
    DIRECTION INPUT ;
    USE SIGNAL ;
    PORT
      LAYER M5 ;
        RECT  14.304 0 14.328 0.084 ;
    END
  END d[49]
  PIN d[4]
    DIRECTION INPUT ;
    USE SIGNAL ;
    PORT
      LAYER M5 ;
        RECT  7.824 0 7.848 0.084 ;
    END
  END d[4]
  PIN d[500]
    DIRECTION INPUT ;
    USE SIGNAL ;
    PORT
      LAYER M5 ;
        RECT  79.392 0 79.416 0.084 ;
    END
  END d[500]
  PIN d[501]
    DIRECTION INPUT ;
    USE SIGNAL ;
    PORT
      LAYER M5 ;
        RECT  79.824 0 79.848 0.084 ;
    END
  END d[501]
  PIN d[502]
    DIRECTION INPUT ;
    USE SIGNAL ;
    PORT
      LAYER M5 ;
        RECT  79.68 0 79.704 0.084 ;
    END
  END d[502]
  PIN d[503]
    DIRECTION INPUT ;
    USE SIGNAL ;
    PORT
      LAYER M5 ;
        RECT  80.112 0 80.136 0.084 ;
    END
  END d[503]
  PIN d[504]
    DIRECTION INPUT ;
    USE SIGNAL ;
    PORT
      LAYER M5 ;
        RECT  79.968 0 79.992 0.084 ;
    END
  END d[504]
  PIN d[505]
    DIRECTION INPUT ;
    USE SIGNAL ;
    PORT
      LAYER M5 ;
        RECT  80.4 0 80.424 0.084 ;
    END
  END d[505]
  PIN d[506]
    DIRECTION INPUT ;
    USE SIGNAL ;
    PORT
      LAYER M5 ;
        RECT  80.256 0 80.28 0.084 ;
    END
  END d[506]
  PIN d[507]
    DIRECTION INPUT ;
    USE SIGNAL ;
    PORT
      LAYER M5 ;
        RECT  80.688 0 80.712 0.084 ;
    END
  END d[507]
  PIN d[508]
    DIRECTION INPUT ;
    USE SIGNAL ;
    PORT
      LAYER M5 ;
        RECT  80.544 0 80.568 0.084 ;
    END
  END d[508]
  PIN d[509]
    DIRECTION INPUT ;
    USE SIGNAL ;
    PORT
      LAYER M5 ;
        RECT  81.12 0 81.144 0.084 ;
    END
  END d[509]
  PIN d[50]
    DIRECTION INPUT ;
    USE SIGNAL ;
    PORT
      LAYER M5 ;
        RECT  14.448 0 14.472 0.084 ;
    END
  END d[50]
  PIN d[510]
    DIRECTION INPUT ;
    USE SIGNAL ;
    PORT
      LAYER M5 ;
        RECT  80.832 0 80.856 0.084 ;
    END
  END d[510]
  PIN d[511]
    DIRECTION INPUT ;
    USE SIGNAL ;
    PORT
      LAYER M5 ;
        RECT  81.264 0 81.288 0.084 ;
    END
  END d[511]
  PIN d[512]
    DIRECTION INPUT ;
    USE SIGNAL ;
    PORT
      LAYER M5 ;
        RECT  80.976 0 81 0.084 ;
    END
  END d[512]
  PIN d[513]
    DIRECTION INPUT ;
    USE SIGNAL ;
    PORT
      LAYER M5 ;
        RECT  81.696 0 81.72 0.084 ;
    END
  END d[513]
  PIN d[514]
    DIRECTION INPUT ;
    USE SIGNAL ;
    PORT
      LAYER M5 ;
        RECT  81.408 0 81.432 0.084 ;
    END
  END d[514]
  PIN d[515]
    DIRECTION INPUT ;
    USE SIGNAL ;
    PORT
      LAYER M5 ;
        RECT  81.984 0 82.008 0.084 ;
    END
  END d[515]
  PIN d[516]
    DIRECTION INPUT ;
    USE SIGNAL ;
    PORT
      LAYER M5 ;
        RECT  81.552 0 81.576 0.084 ;
    END
  END d[516]
  PIN d[517]
    DIRECTION INPUT ;
    USE SIGNAL ;
    PORT
      LAYER M5 ;
        RECT  82.272 0 82.296 0.084 ;
    END
  END d[517]
  PIN d[518]
    DIRECTION INPUT ;
    USE SIGNAL ;
    PORT
      LAYER M5 ;
        RECT  81.84 0 81.864 0.084 ;
    END
  END d[518]
  PIN d[519]
    DIRECTION INPUT ;
    USE SIGNAL ;
    PORT
      LAYER M5 ;
        RECT  82.56 0 82.584 0.084 ;
    END
  END d[519]
  PIN d[51]
    DIRECTION INPUT ;
    USE SIGNAL ;
    PORT
      LAYER M5 ;
        RECT  14.592 0 14.616 0.084 ;
    END
  END d[51]
  PIN d[520]
    DIRECTION INPUT ;
    USE SIGNAL ;
    PORT
      LAYER M5 ;
        RECT  82.128 0 82.152 0.084 ;
    END
  END d[520]
  PIN d[521]
    DIRECTION INPUT ;
    USE SIGNAL ;
    PORT
      LAYER M5 ;
        RECT  82.704 0 82.728 0.084 ;
    END
  END d[521]
  PIN d[522]
    DIRECTION INPUT ;
    USE SIGNAL ;
    PORT
      LAYER M5 ;
        RECT  82.416 0 82.44 0.084 ;
    END
  END d[522]
  PIN d[523]
    DIRECTION INPUT ;
    USE SIGNAL ;
    PORT
      LAYER M5 ;
        RECT  82.848 0 82.872 0.084 ;
    END
  END d[523]
  PIN d[524]
    DIRECTION INPUT ;
    USE SIGNAL ;
    PORT
      LAYER M5 ;
        RECT  83.136 0 83.16 0.084 ;
    END
  END d[524]
  PIN d[525]
    DIRECTION INPUT ;
    USE SIGNAL ;
    PORT
      LAYER M5 ;
        RECT  82.992 0 83.016 0.084 ;
    END
  END d[525]
  PIN d[526]
    DIRECTION INPUT ;
    USE SIGNAL ;
    PORT
      LAYER M5 ;
        RECT  83.424 0 83.448 0.084 ;
    END
  END d[526]
  PIN d[527]
    DIRECTION INPUT ;
    USE SIGNAL ;
    PORT
      LAYER M5 ;
        RECT  83.28 0 83.304 0.084 ;
    END
  END d[527]
  PIN d[528]
    DIRECTION INPUT ;
    USE SIGNAL ;
    PORT
      LAYER M5 ;
        RECT  83.568 0 83.592 0.084 ;
    END
  END d[528]
  PIN d[529]
    DIRECTION INPUT ;
    USE SIGNAL ;
    PORT
      LAYER M5 ;
        RECT  83.712 0 83.736 0.084 ;
    END
  END d[529]
  PIN d[52]
    DIRECTION INPUT ;
    USE SIGNAL ;
    PORT
      LAYER M5 ;
        RECT  14.736 0 14.76 0.084 ;
    END
  END d[52]
  PIN d[530]
    DIRECTION INPUT ;
    USE SIGNAL ;
    PORT
      LAYER M5 ;
        RECT  83.856 0 83.88 0.084 ;
    END
  END d[530]
  PIN d[531]
    DIRECTION INPUT ;
    USE SIGNAL ;
    PORT
      LAYER M5 ;
        RECT  84 0 84.024 0.084 ;
    END
  END d[531]
  PIN d[532]
    DIRECTION INPUT ;
    USE SIGNAL ;
    PORT
      LAYER M5 ;
        RECT  84.288 0 84.312 0.084 ;
    END
  END d[532]
  PIN d[533]
    DIRECTION INPUT ;
    USE SIGNAL ;
    PORT
      LAYER M5 ;
        RECT  84.144 0 84.168 0.084 ;
    END
  END d[533]
  PIN d[534]
    DIRECTION INPUT ;
    USE SIGNAL ;
    PORT
      LAYER M5 ;
        RECT  84.432 0 84.456 0.084 ;
    END
  END d[534]
  PIN d[535]
    DIRECTION INPUT ;
    USE SIGNAL ;
    PORT
      LAYER M5 ;
        RECT  84.576 0 84.6 0.084 ;
    END
  END d[535]
  PIN d[536]
    DIRECTION INPUT ;
    USE SIGNAL ;
    PORT
      LAYER M5 ;
        RECT  84.72 0 84.744 0.084 ;
    END
  END d[536]
  PIN d[53]
    DIRECTION INPUT ;
    USE SIGNAL ;
    PORT
      LAYER M5 ;
        RECT  14.88 0 14.904 0.084 ;
    END
  END d[53]
  PIN d[54]
    DIRECTION INPUT ;
    USE SIGNAL ;
    PORT
      LAYER M5 ;
        RECT  15.024 0 15.048 0.084 ;
    END
  END d[54]
  PIN d[55]
    DIRECTION INPUT ;
    USE SIGNAL ;
    PORT
      LAYER M5 ;
        RECT  15.312 0 15.336 0.084 ;
    END
  END d[55]
  PIN d[56]
    DIRECTION INPUT ;
    USE SIGNAL ;
    PORT
      LAYER M5 ;
        RECT  15.168 0 15.192 0.084 ;
    END
  END d[56]
  PIN d[57]
    DIRECTION INPUT ;
    USE SIGNAL ;
    PORT
      LAYER M5 ;
        RECT  15.6 0 15.624 0.084 ;
    END
  END d[57]
  PIN d[58]
    DIRECTION INPUT ;
    USE SIGNAL ;
    PORT
      LAYER M5 ;
        RECT  15.456 0 15.48 0.084 ;
    END
  END d[58]
  PIN d[59]
    DIRECTION INPUT ;
    USE SIGNAL ;
    PORT
      LAYER M5 ;
        RECT  16.032 0 16.056 0.084 ;
    END
  END d[59]
  PIN d[5]
    DIRECTION INPUT ;
    USE SIGNAL ;
    PORT
      LAYER M5 ;
        RECT  7.968 0 7.992 0.084 ;
    END
  END d[5]
  PIN d[60]
    DIRECTION INPUT ;
    USE SIGNAL ;
    PORT
      LAYER M5 ;
        RECT  15.744 0 15.768 0.084 ;
    END
  END d[60]
  PIN d[61]
    DIRECTION INPUT ;
    USE SIGNAL ;
    PORT
      LAYER M5 ;
        RECT  16.176 0 16.2 0.084 ;
    END
  END d[61]
  PIN d[62]
    DIRECTION INPUT ;
    USE SIGNAL ;
    PORT
      LAYER M5 ;
        RECT  15.888 0 15.912 0.084 ;
    END
  END d[62]
  PIN d[63]
    DIRECTION INPUT ;
    USE SIGNAL ;
    PORT
      LAYER M5 ;
        RECT  16.464 0 16.488 0.084 ;
    END
  END d[63]
  PIN d[64]
    DIRECTION INPUT ;
    USE SIGNAL ;
    PORT
      LAYER M5 ;
        RECT  16.32 0 16.344 0.084 ;
    END
  END d[64]
  PIN d[65]
    DIRECTION INPUT ;
    USE SIGNAL ;
    PORT
      LAYER M5 ;
        RECT  16.752 0 16.776 0.084 ;
    END
  END d[65]
  PIN d[66]
    DIRECTION INPUT ;
    USE SIGNAL ;
    PORT
      LAYER M5 ;
        RECT  16.608 0 16.632 0.084 ;
    END
  END d[66]
  PIN d[67]
    DIRECTION INPUT ;
    USE SIGNAL ;
    PORT
      LAYER M5 ;
        RECT  17.04 0 17.064 0.084 ;
    END
  END d[67]
  PIN d[68]
    DIRECTION INPUT ;
    USE SIGNAL ;
    PORT
      LAYER M5 ;
        RECT  16.896 0 16.92 0.084 ;
    END
  END d[68]
  PIN d[69]
    DIRECTION INPUT ;
    USE SIGNAL ;
    PORT
      LAYER M5 ;
        RECT  17.328 0 17.352 0.084 ;
    END
  END d[69]
  PIN d[6]
    DIRECTION INPUT ;
    USE SIGNAL ;
    PORT
      LAYER M5 ;
        RECT  8.112 0 8.136 0.084 ;
    END
  END d[6]
  PIN d[70]
    DIRECTION INPUT ;
    USE SIGNAL ;
    PORT
      LAYER M5 ;
        RECT  17.184 0 17.208 0.084 ;
    END
  END d[70]
  PIN d[71]
    DIRECTION INPUT ;
    USE SIGNAL ;
    PORT
      LAYER M5 ;
        RECT  17.472 0 17.496 0.084 ;
    END
  END d[71]
  PIN d[72]
    DIRECTION INPUT ;
    USE SIGNAL ;
    PORT
      LAYER M5 ;
        RECT  17.76 0 17.784 0.084 ;
    END
  END d[72]
  PIN d[73]
    DIRECTION INPUT ;
    USE SIGNAL ;
    PORT
      LAYER M5 ;
        RECT  17.616 0 17.64 0.084 ;
    END
  END d[73]
  PIN d[74]
    DIRECTION INPUT ;
    USE SIGNAL ;
    PORT
      LAYER M5 ;
        RECT  18.048 0 18.072 0.084 ;
    END
  END d[74]
  PIN d[75]
    DIRECTION INPUT ;
    USE SIGNAL ;
    PORT
      LAYER M5 ;
        RECT  17.904 0 17.928 0.084 ;
    END
  END d[75]
  PIN d[76]
    DIRECTION INPUT ;
    USE SIGNAL ;
    PORT
      LAYER M5 ;
        RECT  18.336 0 18.36 0.084 ;
    END
  END d[76]
  PIN d[77]
    DIRECTION INPUT ;
    USE SIGNAL ;
    PORT
      LAYER M5 ;
        RECT  18.192 0 18.216 0.084 ;
    END
  END d[77]
  PIN d[78]
    DIRECTION INPUT ;
    USE SIGNAL ;
    PORT
      LAYER M5 ;
        RECT  18.624 0 18.648 0.084 ;
    END
  END d[78]
  PIN d[79]
    DIRECTION INPUT ;
    USE SIGNAL ;
    PORT
      LAYER M5 ;
        RECT  18.48 0 18.504 0.084 ;
    END
  END d[79]
  PIN d[7]
    DIRECTION INPUT ;
    USE SIGNAL ;
    PORT
      LAYER M5 ;
        RECT  8.256 0 8.28 0.084 ;
    END
  END d[7]
  PIN d[80]
    DIRECTION INPUT ;
    USE SIGNAL ;
    PORT
      LAYER M5 ;
        RECT  18.912 0 18.936 0.084 ;
    END
  END d[80]
  PIN d[81]
    DIRECTION INPUT ;
    USE SIGNAL ;
    PORT
      LAYER M5 ;
        RECT  18.768 0 18.792 0.084 ;
    END
  END d[81]
  PIN d[82]
    DIRECTION INPUT ;
    USE SIGNAL ;
    PORT
      LAYER M5 ;
        RECT  19.2 0 19.224 0.084 ;
    END
  END d[82]
  PIN d[83]
    DIRECTION INPUT ;
    USE SIGNAL ;
    PORT
      LAYER M5 ;
        RECT  19.056 0 19.08 0.084 ;
    END
  END d[83]
  PIN d[84]
    DIRECTION INPUT ;
    USE SIGNAL ;
    PORT
      LAYER M5 ;
        RECT  19.344 0 19.368 0.084 ;
    END
  END d[84]
  PIN d[85]
    DIRECTION INPUT ;
    USE SIGNAL ;
    PORT
      LAYER M5 ;
        RECT  19.488 0 19.512 0.084 ;
    END
  END d[85]
  PIN d[86]
    DIRECTION INPUT ;
    USE SIGNAL ;
    PORT
      LAYER M5 ;
        RECT  19.776 0 19.8 0.084 ;
    END
  END d[86]
  PIN d[87]
    DIRECTION INPUT ;
    USE SIGNAL ;
    PORT
      LAYER M5 ;
        RECT  19.632 0 19.656 0.084 ;
    END
  END d[87]
  PIN d[88]
    DIRECTION INPUT ;
    USE SIGNAL ;
    PORT
      LAYER M5 ;
        RECT  19.92 0 19.944 0.084 ;
    END
  END d[88]
  PIN d[89]
    DIRECTION INPUT ;
    USE SIGNAL ;
    PORT
      LAYER M5 ;
        RECT  20.064 0 20.088 0.084 ;
    END
  END d[89]
  PIN d[8]
    DIRECTION INPUT ;
    USE SIGNAL ;
    PORT
      LAYER M5 ;
        RECT  8.4 0 8.424 0.084 ;
    END
  END d[8]
  PIN d[90]
    DIRECTION INPUT ;
    USE SIGNAL ;
    PORT
      LAYER M5 ;
        RECT  20.208 0 20.232 0.084 ;
    END
  END d[90]
  PIN d[91]
    DIRECTION INPUT ;
    USE SIGNAL ;
    PORT
      LAYER M5 ;
        RECT  20.352 0 20.376 0.084 ;
    END
  END d[91]
  PIN d[92]
    DIRECTION INPUT ;
    USE SIGNAL ;
    PORT
      LAYER M5 ;
        RECT  20.496 0 20.52 0.084 ;
    END
  END d[92]
  PIN d[93]
    DIRECTION INPUT ;
    USE SIGNAL ;
    PORT
      LAYER M5 ;
        RECT  20.64 0 20.664 0.084 ;
    END
  END d[93]
  PIN d[94]
    DIRECTION INPUT ;
    USE SIGNAL ;
    PORT
      LAYER M5 ;
        RECT  20.784 0 20.808 0.084 ;
    END
  END d[94]
  PIN d[95]
    DIRECTION INPUT ;
    USE SIGNAL ;
    PORT
      LAYER M5 ;
        RECT  20.928 0 20.952 0.084 ;
    END
  END d[95]
  PIN d[96]
    DIRECTION INPUT ;
    USE SIGNAL ;
    PORT
      LAYER M5 ;
        RECT  21.072 0 21.096 0.084 ;
    END
  END d[96]
  PIN d[97]
    DIRECTION INPUT ;
    USE SIGNAL ;
    PORT
      LAYER M5 ;
        RECT  21.216 0 21.24 0.084 ;
    END
  END d[97]
  PIN d[98]
    DIRECTION INPUT ;
    USE SIGNAL ;
    PORT
      LAYER M5 ;
        RECT  21.36 0 21.384 0.084 ;
    END
  END d[98]
  PIN d[99]
    DIRECTION INPUT ;
    USE SIGNAL ;
    PORT
      LAYER M5 ;
        RECT  21.504 0 21.528 0.084 ;
    END
  END d[99]
  PIN d[9]
    DIRECTION INPUT ;
    USE SIGNAL ;
    PORT
      LAYER M5 ;
        RECT  8.832 0 8.856 0.084 ;
    END
  END d[9]
  PIN fault
    DIRECTION OUTPUT ;
    USE SIGNAL ;
    PORT
      LAYER M5 ;
        RECT  45.696 49.596 45.72 49.68 ;
    END
  END fault
  PIN fclk
    DIRECTION INPUT ;
    USE SIGNAL ;
    PORT
      LAYER M5 ;
        RECT  45.84 0 45.864 0.084 ;
    END
  END fclk
  PIN q[0]
    DIRECTION OUTPUT ;
    USE SIGNAL ;
    PORT
      LAYER M5 ;
        RECT  6.672 49.596 6.696 49.68 ;
    END
  END q[0]
  PIN q[100]
    DIRECTION OUTPUT ;
    USE SIGNAL ;
    PORT
      LAYER M5 ;
        RECT  21.072 49.596 21.096 49.68 ;
    END
  END q[100]
  PIN q[101]
    DIRECTION OUTPUT ;
    USE SIGNAL ;
    PORT
      LAYER M5 ;
        RECT  21.216 49.596 21.24 49.68 ;
    END
  END q[101]
  PIN q[102]
    DIRECTION OUTPUT ;
    USE SIGNAL ;
    PORT
      LAYER M5 ;
        RECT  21.36 49.596 21.384 49.68 ;
    END
  END q[102]
  PIN q[103]
    DIRECTION OUTPUT ;
    USE SIGNAL ;
    PORT
      LAYER M5 ;
        RECT  21.648 49.596 21.672 49.68 ;
    END
  END q[103]
  PIN q[104]
    DIRECTION OUTPUT ;
    USE SIGNAL ;
    PORT
      LAYER M5 ;
        RECT  21.504 49.596 21.528 49.68 ;
    END
  END q[104]
  PIN q[105]
    DIRECTION OUTPUT ;
    USE SIGNAL ;
    PORT
      LAYER M5 ;
        RECT  21.936 49.596 21.96 49.68 ;
    END
  END q[105]
  PIN q[106]
    DIRECTION OUTPUT ;
    USE SIGNAL ;
    PORT
      LAYER M5 ;
        RECT  21.792 49.596 21.816 49.68 ;
    END
  END q[106]
  PIN q[107]
    DIRECTION OUTPUT ;
    USE SIGNAL ;
    PORT
      LAYER M5 ;
        RECT  22.224 49.596 22.248 49.68 ;
    END
  END q[107]
  PIN q[108]
    DIRECTION OUTPUT ;
    USE SIGNAL ;
    PORT
      LAYER M5 ;
        RECT  22.08 49.596 22.104 49.68 ;
    END
  END q[108]
  PIN q[109]
    DIRECTION OUTPUT ;
    USE SIGNAL ;
    PORT
      LAYER M5 ;
        RECT  22.656 49.596 22.68 49.68 ;
    END
  END q[109]
  PIN q[10]
    DIRECTION OUTPUT ;
    USE SIGNAL ;
    PORT
      LAYER M5 ;
        RECT  7.968 49.596 7.992 49.68 ;
    END
  END q[10]
  PIN q[110]
    DIRECTION OUTPUT ;
    USE SIGNAL ;
    PORT
      LAYER M5 ;
        RECT  22.368 49.596 22.392 49.68 ;
    END
  END q[110]
  PIN q[111]
    DIRECTION OUTPUT ;
    USE SIGNAL ;
    PORT
      LAYER M5 ;
        RECT  22.8 49.596 22.824 49.68 ;
    END
  END q[111]
  PIN q[112]
    DIRECTION OUTPUT ;
    USE SIGNAL ;
    PORT
      LAYER M5 ;
        RECT  22.512 49.596 22.536 49.68 ;
    END
  END q[112]
  PIN q[113]
    DIRECTION OUTPUT ;
    USE SIGNAL ;
    PORT
      LAYER M5 ;
        RECT  23.088 49.596 23.112 49.68 ;
    END
  END q[113]
  PIN q[114]
    DIRECTION OUTPUT ;
    USE SIGNAL ;
    PORT
      LAYER M5 ;
        RECT  22.944 49.596 22.968 49.68 ;
    END
  END q[114]
  PIN q[115]
    DIRECTION OUTPUT ;
    USE SIGNAL ;
    PORT
      LAYER M5 ;
        RECT  23.376 49.596 23.4 49.68 ;
    END
  END q[115]
  PIN q[116]
    DIRECTION OUTPUT ;
    USE SIGNAL ;
    PORT
      LAYER M5 ;
        RECT  23.232 49.596 23.256 49.68 ;
    END
  END q[116]
  PIN q[117]
    DIRECTION OUTPUT ;
    USE SIGNAL ;
    PORT
      LAYER M5 ;
        RECT  23.664 49.596 23.688 49.68 ;
    END
  END q[117]
  PIN q[118]
    DIRECTION OUTPUT ;
    USE SIGNAL ;
    PORT
      LAYER M5 ;
        RECT  23.52 49.596 23.544 49.68 ;
    END
  END q[118]
  PIN q[119]
    DIRECTION OUTPUT ;
    USE SIGNAL ;
    PORT
      LAYER M5 ;
        RECT  23.952 49.596 23.976 49.68 ;
    END
  END q[119]
  PIN q[11]
    DIRECTION OUTPUT ;
    USE SIGNAL ;
    PORT
      LAYER M5 ;
        RECT  8.4 49.596 8.424 49.68 ;
    END
  END q[11]
  PIN q[120]
    DIRECTION OUTPUT ;
    USE SIGNAL ;
    PORT
      LAYER M5 ;
        RECT  23.808 49.596 23.832 49.68 ;
    END
  END q[120]
  PIN q[121]
    DIRECTION OUTPUT ;
    USE SIGNAL ;
    PORT
      LAYER M5 ;
        RECT  24.096 49.596 24.12 49.68 ;
    END
  END q[121]
  PIN q[122]
    DIRECTION OUTPUT ;
    USE SIGNAL ;
    PORT
      LAYER M5 ;
        RECT  24.384 49.596 24.408 49.68 ;
    END
  END q[122]
  PIN q[123]
    DIRECTION OUTPUT ;
    USE SIGNAL ;
    PORT
      LAYER M5 ;
        RECT  24.24 49.596 24.264 49.68 ;
    END
  END q[123]
  PIN q[124]
    DIRECTION OUTPUT ;
    USE SIGNAL ;
    PORT
      LAYER M5 ;
        RECT  24.672 49.596 24.696 49.68 ;
    END
  END q[124]
  PIN q[125]
    DIRECTION OUTPUT ;
    USE SIGNAL ;
    PORT
      LAYER M5 ;
        RECT  24.528 49.596 24.552 49.68 ;
    END
  END q[125]
  PIN q[126]
    DIRECTION OUTPUT ;
    USE SIGNAL ;
    PORT
      LAYER M5 ;
        RECT  24.96 49.596 24.984 49.68 ;
    END
  END q[126]
  PIN q[127]
    DIRECTION OUTPUT ;
    USE SIGNAL ;
    PORT
      LAYER M5 ;
        RECT  24.816 49.596 24.84 49.68 ;
    END
  END q[127]
  PIN q[128]
    DIRECTION OUTPUT ;
    USE SIGNAL ;
    PORT
      LAYER M5 ;
        RECT  25.248 49.596 25.272 49.68 ;
    END
  END q[128]
  PIN q[129]
    DIRECTION OUTPUT ;
    USE SIGNAL ;
    PORT
      LAYER M5 ;
        RECT  25.104 49.596 25.128 49.68 ;
    END
  END q[129]
  PIN q[12]
    DIRECTION OUTPUT ;
    USE SIGNAL ;
    PORT
      LAYER M5 ;
        RECT  8.112 49.596 8.136 49.68 ;
    END
  END q[12]
  PIN q[130]
    DIRECTION OUTPUT ;
    USE SIGNAL ;
    PORT
      LAYER M5 ;
        RECT  25.536 49.596 25.56 49.68 ;
    END
  END q[130]
  PIN q[131]
    DIRECTION OUTPUT ;
    USE SIGNAL ;
    PORT
      LAYER M5 ;
        RECT  25.392 49.596 25.416 49.68 ;
    END
  END q[131]
  PIN q[132]
    DIRECTION OUTPUT ;
    USE SIGNAL ;
    PORT
      LAYER M5 ;
        RECT  25.824 49.596 25.848 49.68 ;
    END
  END q[132]
  PIN q[133]
    DIRECTION OUTPUT ;
    USE SIGNAL ;
    PORT
      LAYER M5 ;
        RECT  25.68 49.596 25.704 49.68 ;
    END
  END q[133]
  PIN q[134]
    DIRECTION OUTPUT ;
    USE SIGNAL ;
    PORT
      LAYER M5 ;
        RECT  25.968 49.596 25.992 49.68 ;
    END
  END q[134]
  PIN q[135]
    DIRECTION OUTPUT ;
    USE SIGNAL ;
    PORT
      LAYER M5 ;
        RECT  26.112 49.596 26.136 49.68 ;
    END
  END q[135]
  PIN q[136]
    DIRECTION OUTPUT ;
    USE SIGNAL ;
    PORT
      LAYER M5 ;
        RECT  26.4 49.596 26.424 49.68 ;
    END
  END q[136]
  PIN q[137]
    DIRECTION OUTPUT ;
    USE SIGNAL ;
    PORT
      LAYER M5 ;
        RECT  26.256 49.596 26.28 49.68 ;
    END
  END q[137]
  PIN q[138]
    DIRECTION OUTPUT ;
    USE SIGNAL ;
    PORT
      LAYER M5 ;
        RECT  26.544 49.596 26.568 49.68 ;
    END
  END q[138]
  PIN q[139]
    DIRECTION OUTPUT ;
    USE SIGNAL ;
    PORT
      LAYER M5 ;
        RECT  26.688 49.596 26.712 49.68 ;
    END
  END q[139]
  PIN q[13]
    DIRECTION OUTPUT ;
    USE SIGNAL ;
    PORT
      LAYER M5 ;
        RECT  8.688 49.596 8.712 49.68 ;
    END
  END q[13]
  PIN q[140]
    DIRECTION OUTPUT ;
    USE SIGNAL ;
    PORT
      LAYER M5 ;
        RECT  26.832 49.596 26.856 49.68 ;
    END
  END q[140]
  PIN q[141]
    DIRECTION OUTPUT ;
    USE SIGNAL ;
    PORT
      LAYER M5 ;
        RECT  26.976 49.596 27 49.68 ;
    END
  END q[141]
  PIN q[142]
    DIRECTION OUTPUT ;
    USE SIGNAL ;
    PORT
      LAYER M5 ;
        RECT  27.12 49.596 27.144 49.68 ;
    END
  END q[142]
  PIN q[143]
    DIRECTION OUTPUT ;
    USE SIGNAL ;
    PORT
      LAYER M5 ;
        RECT  27.264 49.596 27.288 49.68 ;
    END
  END q[143]
  PIN q[144]
    DIRECTION OUTPUT ;
    USE SIGNAL ;
    PORT
      LAYER M5 ;
        RECT  27.408 49.596 27.432 49.68 ;
    END
  END q[144]
  PIN q[145]
    DIRECTION OUTPUT ;
    USE SIGNAL ;
    PORT
      LAYER M5 ;
        RECT  27.552 49.596 27.576 49.68 ;
    END
  END q[145]
  PIN q[146]
    DIRECTION OUTPUT ;
    USE SIGNAL ;
    PORT
      LAYER M5 ;
        RECT  27.696 49.596 27.72 49.68 ;
    END
  END q[146]
  PIN q[147]
    DIRECTION OUTPUT ;
    USE SIGNAL ;
    PORT
      LAYER M5 ;
        RECT  27.84 49.596 27.864 49.68 ;
    END
  END q[147]
  PIN q[148]
    DIRECTION OUTPUT ;
    USE SIGNAL ;
    PORT
      LAYER M5 ;
        RECT  27.984 49.596 28.008 49.68 ;
    END
  END q[148]
  PIN q[149]
    DIRECTION OUTPUT ;
    USE SIGNAL ;
    PORT
      LAYER M5 ;
        RECT  28.128 49.596 28.152 49.68 ;
    END
  END q[149]
  PIN q[14]
    DIRECTION OUTPUT ;
    USE SIGNAL ;
    PORT
      LAYER M5 ;
        RECT  8.544 49.596 8.568 49.68 ;
    END
  END q[14]
  PIN q[150]
    DIRECTION OUTPUT ;
    USE SIGNAL ;
    PORT
      LAYER M5 ;
        RECT  28.272 49.596 28.296 49.68 ;
    END
  END q[150]
  PIN q[151]
    DIRECTION OUTPUT ;
    USE SIGNAL ;
    PORT
      LAYER M5 ;
        RECT  28.416 49.596 28.44 49.68 ;
    END
  END q[151]
  PIN q[152]
    DIRECTION OUTPUT ;
    USE SIGNAL ;
    PORT
      LAYER M5 ;
        RECT  28.56 49.596 28.584 49.68 ;
    END
  END q[152]
  PIN q[153]
    DIRECTION OUTPUT ;
    USE SIGNAL ;
    PORT
      LAYER M5 ;
        RECT  28.848 49.596 28.872 49.68 ;
    END
  END q[153]
  PIN q[154]
    DIRECTION OUTPUT ;
    USE SIGNAL ;
    PORT
      LAYER M5 ;
        RECT  28.704 49.596 28.728 49.68 ;
    END
  END q[154]
  PIN q[155]
    DIRECTION OUTPUT ;
    USE SIGNAL ;
    PORT
      LAYER M5 ;
        RECT  29.136 49.596 29.16 49.68 ;
    END
  END q[155]
  PIN q[156]
    DIRECTION OUTPUT ;
    USE SIGNAL ;
    PORT
      LAYER M5 ;
        RECT  28.992 49.596 29.016 49.68 ;
    END
  END q[156]
  PIN q[157]
    DIRECTION OUTPUT ;
    USE SIGNAL ;
    PORT
      LAYER M5 ;
        RECT  29.424 49.596 29.448 49.68 ;
    END
  END q[157]
  PIN q[158]
    DIRECTION OUTPUT ;
    USE SIGNAL ;
    PORT
      LAYER M5 ;
        RECT  29.28 49.596 29.304 49.68 ;
    END
  END q[158]
  PIN q[159]
    DIRECTION OUTPUT ;
    USE SIGNAL ;
    PORT
      LAYER M5 ;
        RECT  29.856 49.596 29.88 49.68 ;
    END
  END q[159]
  PIN q[15]
    DIRECTION OUTPUT ;
    USE SIGNAL ;
    PORT
      LAYER M5 ;
        RECT  8.976 49.596 9 49.68 ;
    END
  END q[15]
  PIN q[160]
    DIRECTION OUTPUT ;
    USE SIGNAL ;
    PORT
      LAYER M5 ;
        RECT  29.568 49.596 29.592 49.68 ;
    END
  END q[160]
  PIN q[161]
    DIRECTION OUTPUT ;
    USE SIGNAL ;
    PORT
      LAYER M5 ;
        RECT  30 49.596 30.024 49.68 ;
    END
  END q[161]
  PIN q[162]
    DIRECTION OUTPUT ;
    USE SIGNAL ;
    PORT
      LAYER M5 ;
        RECT  29.712 49.596 29.736 49.68 ;
    END
  END q[162]
  PIN q[163]
    DIRECTION OUTPUT ;
    USE SIGNAL ;
    PORT
      LAYER M5 ;
        RECT  30.288 49.596 30.312 49.68 ;
    END
  END q[163]
  PIN q[164]
    DIRECTION OUTPUT ;
    USE SIGNAL ;
    PORT
      LAYER M5 ;
        RECT  30.144 49.596 30.168 49.68 ;
    END
  END q[164]
  PIN q[165]
    DIRECTION OUTPUT ;
    USE SIGNAL ;
    PORT
      LAYER M5 ;
        RECT  30.576 49.596 30.6 49.68 ;
    END
  END q[165]
  PIN q[166]
    DIRECTION OUTPUT ;
    USE SIGNAL ;
    PORT
      LAYER M5 ;
        RECT  30.432 49.596 30.456 49.68 ;
    END
  END q[166]
  PIN q[167]
    DIRECTION OUTPUT ;
    USE SIGNAL ;
    PORT
      LAYER M5 ;
        RECT  30.864 49.596 30.888 49.68 ;
    END
  END q[167]
  PIN q[168]
    DIRECTION OUTPUT ;
    USE SIGNAL ;
    PORT
      LAYER M5 ;
        RECT  30.72 49.596 30.744 49.68 ;
    END
  END q[168]
  PIN q[169]
    DIRECTION OUTPUT ;
    USE SIGNAL ;
    PORT
      LAYER M5 ;
        RECT  31.152 49.596 31.176 49.68 ;
    END
  END q[169]
  PIN q[16]
    DIRECTION OUTPUT ;
    USE SIGNAL ;
    PORT
      LAYER M5 ;
        RECT  8.832 49.596 8.856 49.68 ;
    END
  END q[16]
  PIN q[170]
    DIRECTION OUTPUT ;
    USE SIGNAL ;
    PORT
      LAYER M5 ;
        RECT  31.008 49.596 31.032 49.68 ;
    END
  END q[170]
  PIN q[171]
    DIRECTION OUTPUT ;
    USE SIGNAL ;
    PORT
      LAYER M5 ;
        RECT  31.296 49.596 31.32 49.68 ;
    END
  END q[171]
  PIN q[172]
    DIRECTION OUTPUT ;
    USE SIGNAL ;
    PORT
      LAYER M5 ;
        RECT  31.584 49.596 31.608 49.68 ;
    END
  END q[172]
  PIN q[173]
    DIRECTION OUTPUT ;
    USE SIGNAL ;
    PORT
      LAYER M5 ;
        RECT  31.44 49.596 31.464 49.68 ;
    END
  END q[173]
  PIN q[174]
    DIRECTION OUTPUT ;
    USE SIGNAL ;
    PORT
      LAYER M5 ;
        RECT  31.872 49.596 31.896 49.68 ;
    END
  END q[174]
  PIN q[175]
    DIRECTION OUTPUT ;
    USE SIGNAL ;
    PORT
      LAYER M5 ;
        RECT  31.728 49.596 31.752 49.68 ;
    END
  END q[175]
  PIN q[176]
    DIRECTION OUTPUT ;
    USE SIGNAL ;
    PORT
      LAYER M5 ;
        RECT  32.16 49.596 32.184 49.68 ;
    END
  END q[176]
  PIN q[177]
    DIRECTION OUTPUT ;
    USE SIGNAL ;
    PORT
      LAYER M5 ;
        RECT  32.016 49.596 32.04 49.68 ;
    END
  END q[177]
  PIN q[178]
    DIRECTION OUTPUT ;
    USE SIGNAL ;
    PORT
      LAYER M5 ;
        RECT  32.448 49.596 32.472 49.68 ;
    END
  END q[178]
  PIN q[179]
    DIRECTION OUTPUT ;
    USE SIGNAL ;
    PORT
      LAYER M5 ;
        RECT  32.304 49.596 32.328 49.68 ;
    END
  END q[179]
  PIN q[17]
    DIRECTION OUTPUT ;
    USE SIGNAL ;
    PORT
      LAYER M5 ;
        RECT  9.264 49.596 9.288 49.68 ;
    END
  END q[17]
  PIN q[180]
    DIRECTION OUTPUT ;
    USE SIGNAL ;
    PORT
      LAYER M5 ;
        RECT  32.736 49.596 32.76 49.68 ;
    END
  END q[180]
  PIN q[181]
    DIRECTION OUTPUT ;
    USE SIGNAL ;
    PORT
      LAYER M5 ;
        RECT  32.592 49.596 32.616 49.68 ;
    END
  END q[181]
  PIN q[182]
    DIRECTION OUTPUT ;
    USE SIGNAL ;
    PORT
      LAYER M5 ;
        RECT  33.024 49.596 33.048 49.68 ;
    END
  END q[182]
  PIN q[183]
    DIRECTION OUTPUT ;
    USE SIGNAL ;
    PORT
      LAYER M5 ;
        RECT  32.88 49.596 32.904 49.68 ;
    END
  END q[183]
  PIN q[184]
    DIRECTION OUTPUT ;
    USE SIGNAL ;
    PORT
      LAYER M5 ;
        RECT  33.168 49.596 33.192 49.68 ;
    END
  END q[184]
  PIN q[185]
    DIRECTION OUTPUT ;
    USE SIGNAL ;
    PORT
      LAYER M5 ;
        RECT  33.312 49.596 33.336 49.68 ;
    END
  END q[185]
  PIN q[186]
    DIRECTION OUTPUT ;
    USE SIGNAL ;
    PORT
      LAYER M5 ;
        RECT  33.456 49.596 33.48 49.68 ;
    END
  END q[186]
  PIN q[187]
    DIRECTION OUTPUT ;
    USE SIGNAL ;
    PORT
      LAYER M5 ;
        RECT  33.6 49.596 33.624 49.68 ;
    END
  END q[187]
  PIN q[188]
    DIRECTION OUTPUT ;
    USE SIGNAL ;
    PORT
      LAYER M5 ;
        RECT  33.744 49.596 33.768 49.68 ;
    END
  END q[188]
  PIN q[189]
    DIRECTION OUTPUT ;
    USE SIGNAL ;
    PORT
      LAYER M5 ;
        RECT  33.888 49.596 33.912 49.68 ;
    END
  END q[189]
  PIN q[18]
    DIRECTION OUTPUT ;
    USE SIGNAL ;
    PORT
      LAYER M5 ;
        RECT  9.12 49.596 9.144 49.68 ;
    END
  END q[18]
  PIN q[190]
    DIRECTION OUTPUT ;
    USE SIGNAL ;
    PORT
      LAYER M5 ;
        RECT  34.032 49.596 34.056 49.68 ;
    END
  END q[190]
  PIN q[191]
    DIRECTION OUTPUT ;
    USE SIGNAL ;
    PORT
      LAYER M5 ;
        RECT  34.176 49.596 34.2 49.68 ;
    END
  END q[191]
  PIN q[192]
    DIRECTION OUTPUT ;
    USE SIGNAL ;
    PORT
      LAYER M5 ;
        RECT  34.32 49.596 34.344 49.68 ;
    END
  END q[192]
  PIN q[193]
    DIRECTION OUTPUT ;
    USE SIGNAL ;
    PORT
      LAYER M5 ;
        RECT  34.464 49.596 34.488 49.68 ;
    END
  END q[193]
  PIN q[194]
    DIRECTION OUTPUT ;
    USE SIGNAL ;
    PORT
      LAYER M5 ;
        RECT  34.608 49.596 34.632 49.68 ;
    END
  END q[194]
  PIN q[195]
    DIRECTION OUTPUT ;
    USE SIGNAL ;
    PORT
      LAYER M5 ;
        RECT  34.752 49.596 34.776 49.68 ;
    END
  END q[195]
  PIN q[196]
    DIRECTION OUTPUT ;
    USE SIGNAL ;
    PORT
      LAYER M5 ;
        RECT  34.896 49.596 34.92 49.68 ;
    END
  END q[196]
  PIN q[197]
    DIRECTION OUTPUT ;
    USE SIGNAL ;
    PORT
      LAYER M5 ;
        RECT  35.04 49.596 35.064 49.68 ;
    END
  END q[197]
  PIN q[198]
    DIRECTION OUTPUT ;
    USE SIGNAL ;
    PORT
      LAYER M5 ;
        RECT  35.184 49.596 35.208 49.68 ;
    END
  END q[198]
  PIN q[199]
    DIRECTION OUTPUT ;
    USE SIGNAL ;
    PORT
      LAYER M5 ;
        RECT  35.328 49.596 35.352 49.68 ;
    END
  END q[199]
  PIN q[19]
    DIRECTION OUTPUT ;
    USE SIGNAL ;
    PORT
      LAYER M5 ;
        RECT  9.552 49.596 9.576 49.68 ;
    END
  END q[19]
  PIN q[1]
    DIRECTION OUTPUT ;
    USE SIGNAL ;
    PORT
      LAYER M5 ;
        RECT  6.816 49.596 6.84 49.68 ;
    END
  END q[1]
  PIN q[200]
    DIRECTION OUTPUT ;
    USE SIGNAL ;
    PORT
      LAYER M5 ;
        RECT  35.472 49.596 35.496 49.68 ;
    END
  END q[200]
  PIN q[201]
    DIRECTION OUTPUT ;
    USE SIGNAL ;
    PORT
      LAYER M5 ;
        RECT  35.616 49.596 35.64 49.68 ;
    END
  END q[201]
  PIN q[202]
    DIRECTION OUTPUT ;
    USE SIGNAL ;
    PORT
      LAYER M5 ;
        RECT  35.76 49.596 35.784 49.68 ;
    END
  END q[202]
  PIN q[203]
    DIRECTION OUTPUT ;
    USE SIGNAL ;
    PORT
      LAYER M5 ;
        RECT  36.048 49.596 36.072 49.68 ;
    END
  END q[203]
  PIN q[204]
    DIRECTION OUTPUT ;
    USE SIGNAL ;
    PORT
      LAYER M5 ;
        RECT  35.904 49.596 35.928 49.68 ;
    END
  END q[204]
  PIN q[205]
    DIRECTION OUTPUT ;
    USE SIGNAL ;
    PORT
      LAYER M5 ;
        RECT  36.336 49.596 36.36 49.68 ;
    END
  END q[205]
  PIN q[206]
    DIRECTION OUTPUT ;
    USE SIGNAL ;
    PORT
      LAYER M5 ;
        RECT  36.192 49.596 36.216 49.68 ;
    END
  END q[206]
  PIN q[207]
    DIRECTION OUTPUT ;
    USE SIGNAL ;
    PORT
      LAYER M5 ;
        RECT  36.624 49.596 36.648 49.68 ;
    END
  END q[207]
  PIN q[208]
    DIRECTION OUTPUT ;
    USE SIGNAL ;
    PORT
      LAYER M5 ;
        RECT  36.48 49.596 36.504 49.68 ;
    END
  END q[208]
  PIN q[209]
    DIRECTION OUTPUT ;
    USE SIGNAL ;
    PORT
      LAYER M5 ;
        RECT  37.056 49.596 37.08 49.68 ;
    END
  END q[209]
  PIN q[20]
    DIRECTION OUTPUT ;
    USE SIGNAL ;
    PORT
      LAYER M5 ;
        RECT  9.408 49.596 9.432 49.68 ;
    END
  END q[20]
  PIN q[210]
    DIRECTION OUTPUT ;
    USE SIGNAL ;
    PORT
      LAYER M5 ;
        RECT  36.768 49.596 36.792 49.68 ;
    END
  END q[210]
  PIN q[211]
    DIRECTION OUTPUT ;
    USE SIGNAL ;
    PORT
      LAYER M5 ;
        RECT  37.2 49.596 37.224 49.68 ;
    END
  END q[211]
  PIN q[212]
    DIRECTION OUTPUT ;
    USE SIGNAL ;
    PORT
      LAYER M5 ;
        RECT  36.912 49.596 36.936 49.68 ;
    END
  END q[212]
  PIN q[213]
    DIRECTION OUTPUT ;
    USE SIGNAL ;
    PORT
      LAYER M5 ;
        RECT  37.488 49.596 37.512 49.68 ;
    END
  END q[213]
  PIN q[214]
    DIRECTION OUTPUT ;
    USE SIGNAL ;
    PORT
      LAYER M5 ;
        RECT  37.344 49.596 37.368 49.68 ;
    END
  END q[214]
  PIN q[215]
    DIRECTION OUTPUT ;
    USE SIGNAL ;
    PORT
      LAYER M5 ;
        RECT  37.776 49.596 37.8 49.68 ;
    END
  END q[215]
  PIN q[216]
    DIRECTION OUTPUT ;
    USE SIGNAL ;
    PORT
      LAYER M5 ;
        RECT  37.632 49.596 37.656 49.68 ;
    END
  END q[216]
  PIN q[217]
    DIRECTION OUTPUT ;
    USE SIGNAL ;
    PORT
      LAYER M5 ;
        RECT  38.064 49.596 38.088 49.68 ;
    END
  END q[217]
  PIN q[218]
    DIRECTION OUTPUT ;
    USE SIGNAL ;
    PORT
      LAYER M5 ;
        RECT  37.92 49.596 37.944 49.68 ;
    END
  END q[218]
  PIN q[219]
    DIRECTION OUTPUT ;
    USE SIGNAL ;
    PORT
      LAYER M5 ;
        RECT  38.496 49.596 38.52 49.68 ;
    END
  END q[219]
  PIN q[21]
    DIRECTION OUTPUT ;
    USE SIGNAL ;
    PORT
      LAYER M5 ;
        RECT  9.696 49.596 9.72 49.68 ;
    END
  END q[21]
  PIN q[220]
    DIRECTION OUTPUT ;
    USE SIGNAL ;
    PORT
      LAYER M5 ;
        RECT  38.208 49.596 38.232 49.68 ;
    END
  END q[220]
  PIN q[221]
    DIRECTION OUTPUT ;
    USE SIGNAL ;
    PORT
      LAYER M5 ;
        RECT  38.64 49.596 38.664 49.68 ;
    END
  END q[221]
  PIN q[222]
    DIRECTION OUTPUT ;
    USE SIGNAL ;
    PORT
      LAYER M5 ;
        RECT  38.352 49.596 38.376 49.68 ;
    END
  END q[222]
  PIN q[223]
    DIRECTION OUTPUT ;
    USE SIGNAL ;
    PORT
      LAYER M5 ;
        RECT  38.784 49.596 38.808 49.68 ;
    END
  END q[223]
  PIN q[224]
    DIRECTION OUTPUT ;
    USE SIGNAL ;
    PORT
      LAYER M5 ;
        RECT  39.072 49.596 39.096 49.68 ;
    END
  END q[224]
  PIN q[225]
    DIRECTION OUTPUT ;
    USE SIGNAL ;
    PORT
      LAYER M5 ;
        RECT  38.928 49.596 38.952 49.68 ;
    END
  END q[225]
  PIN q[226]
    DIRECTION OUTPUT ;
    USE SIGNAL ;
    PORT
      LAYER M5 ;
        RECT  39.36 49.596 39.384 49.68 ;
    END
  END q[226]
  PIN q[227]
    DIRECTION OUTPUT ;
    USE SIGNAL ;
    PORT
      LAYER M5 ;
        RECT  39.216 49.596 39.24 49.68 ;
    END
  END q[227]
  PIN q[228]
    DIRECTION OUTPUT ;
    USE SIGNAL ;
    PORT
      LAYER M5 ;
        RECT  39.648 49.596 39.672 49.68 ;
    END
  END q[228]
  PIN q[229]
    DIRECTION OUTPUT ;
    USE SIGNAL ;
    PORT
      LAYER M5 ;
        RECT  39.504 49.596 39.528 49.68 ;
    END
  END q[229]
  PIN q[22]
    DIRECTION OUTPUT ;
    USE SIGNAL ;
    PORT
      LAYER M5 ;
        RECT  9.984 49.596 10.008 49.68 ;
    END
  END q[22]
  PIN q[230]
    DIRECTION OUTPUT ;
    USE SIGNAL ;
    PORT
      LAYER M5 ;
        RECT  39.936 49.596 39.96 49.68 ;
    END
  END q[230]
  PIN q[231]
    DIRECTION OUTPUT ;
    USE SIGNAL ;
    PORT
      LAYER M5 ;
        RECT  39.792 49.596 39.816 49.68 ;
    END
  END q[231]
  PIN q[232]
    DIRECTION OUTPUT ;
    USE SIGNAL ;
    PORT
      LAYER M5 ;
        RECT  40.224 49.596 40.248 49.68 ;
    END
  END q[232]
  PIN q[233]
    DIRECTION OUTPUT ;
    USE SIGNAL ;
    PORT
      LAYER M5 ;
        RECT  40.08 49.596 40.104 49.68 ;
    END
  END q[233]
  PIN q[234]
    DIRECTION OUTPUT ;
    USE SIGNAL ;
    PORT
      LAYER M5 ;
        RECT  40.368 49.596 40.392 49.68 ;
    END
  END q[234]
  PIN q[235]
    DIRECTION OUTPUT ;
    USE SIGNAL ;
    PORT
      LAYER M5 ;
        RECT  40.512 49.596 40.536 49.68 ;
    END
  END q[235]
  PIN q[236]
    DIRECTION OUTPUT ;
    USE SIGNAL ;
    PORT
      LAYER M5 ;
        RECT  40.656 49.596 40.68 49.68 ;
    END
  END q[236]
  PIN q[237]
    DIRECTION OUTPUT ;
    USE SIGNAL ;
    PORT
      LAYER M5 ;
        RECT  40.8 49.596 40.824 49.68 ;
    END
  END q[237]
  PIN q[238]
    DIRECTION OUTPUT ;
    USE SIGNAL ;
    PORT
      LAYER M5 ;
        RECT  40.944 49.596 40.968 49.68 ;
    END
  END q[238]
  PIN q[239]
    DIRECTION OUTPUT ;
    USE SIGNAL ;
    PORT
      LAYER M5 ;
        RECT  41.088 49.596 41.112 49.68 ;
    END
  END q[239]
  PIN q[23]
    DIRECTION OUTPUT ;
    USE SIGNAL ;
    PORT
      LAYER M5 ;
        RECT  9.84 49.596 9.864 49.68 ;
    END
  END q[23]
  PIN q[240]
    DIRECTION OUTPUT ;
    USE SIGNAL ;
    PORT
      LAYER M5 ;
        RECT  41.232 49.596 41.256 49.68 ;
    END
  END q[240]
  PIN q[241]
    DIRECTION OUTPUT ;
    USE SIGNAL ;
    PORT
      LAYER M5 ;
        RECT  41.376 49.596 41.4 49.68 ;
    END
  END q[241]
  PIN q[242]
    DIRECTION OUTPUT ;
    USE SIGNAL ;
    PORT
      LAYER M5 ;
        RECT  41.52 49.596 41.544 49.68 ;
    END
  END q[242]
  PIN q[243]
    DIRECTION OUTPUT ;
    USE SIGNAL ;
    PORT
      LAYER M5 ;
        RECT  41.664 49.596 41.688 49.68 ;
    END
  END q[243]
  PIN q[244]
    DIRECTION OUTPUT ;
    USE SIGNAL ;
    PORT
      LAYER M5 ;
        RECT  41.808 49.596 41.832 49.68 ;
    END
  END q[244]
  PIN q[245]
    DIRECTION OUTPUT ;
    USE SIGNAL ;
    PORT
      LAYER M5 ;
        RECT  41.952 49.596 41.976 49.68 ;
    END
  END q[245]
  PIN q[246]
    DIRECTION OUTPUT ;
    USE SIGNAL ;
    PORT
      LAYER M5 ;
        RECT  42.096 49.596 42.12 49.68 ;
    END
  END q[246]
  PIN q[247]
    DIRECTION OUTPUT ;
    USE SIGNAL ;
    PORT
      LAYER M5 ;
        RECT  42.24 49.596 42.264 49.68 ;
    END
  END q[247]
  PIN q[248]
    DIRECTION OUTPUT ;
    USE SIGNAL ;
    PORT
      LAYER M5 ;
        RECT  42.384 49.596 42.408 49.68 ;
    END
  END q[248]
  PIN q[249]
    DIRECTION OUTPUT ;
    USE SIGNAL ;
    PORT
      LAYER M5 ;
        RECT  42.672 49.596 42.696 49.68 ;
    END
  END q[249]
  PIN q[24]
    DIRECTION OUTPUT ;
    USE SIGNAL ;
    PORT
      LAYER M5 ;
        RECT  10.272 49.596 10.296 49.68 ;
    END
  END q[24]
  PIN q[250]
    DIRECTION OUTPUT ;
    USE SIGNAL ;
    PORT
      LAYER M5 ;
        RECT  42.528 49.596 42.552 49.68 ;
    END
  END q[250]
  PIN q[251]
    DIRECTION OUTPUT ;
    USE SIGNAL ;
    PORT
      LAYER M5 ;
        RECT  42.96 49.596 42.984 49.68 ;
    END
  END q[251]
  PIN q[252]
    DIRECTION OUTPUT ;
    USE SIGNAL ;
    PORT
      LAYER M5 ;
        RECT  42.816 49.596 42.84 49.68 ;
    END
  END q[252]
  PIN q[253]
    DIRECTION OUTPUT ;
    USE SIGNAL ;
    PORT
      LAYER M5 ;
        RECT  43.248 49.596 43.272 49.68 ;
    END
  END q[253]
  PIN q[254]
    DIRECTION OUTPUT ;
    USE SIGNAL ;
    PORT
      LAYER M5 ;
        RECT  43.104 49.596 43.128 49.68 ;
    END
  END q[254]
  PIN q[255]
    DIRECTION OUTPUT ;
    USE SIGNAL ;
    PORT
      LAYER M5 ;
        RECT  43.536 49.596 43.56 49.68 ;
    END
  END q[255]
  PIN q[256]
    DIRECTION OUTPUT ;
    USE SIGNAL ;
    PORT
      LAYER M5 ;
        RECT  43.392 49.596 43.416 49.68 ;
    END
  END q[256]
  PIN q[257]
    DIRECTION OUTPUT ;
    USE SIGNAL ;
    PORT
      LAYER M5 ;
        RECT  43.824 49.596 43.848 49.68 ;
    END
  END q[257]
  PIN q[258]
    DIRECTION OUTPUT ;
    USE SIGNAL ;
    PORT
      LAYER M5 ;
        RECT  43.68 49.596 43.704 49.68 ;
    END
  END q[258]
  PIN q[259]
    DIRECTION OUTPUT ;
    USE SIGNAL ;
    PORT
      LAYER M5 ;
        RECT  44.256 49.596 44.28 49.68 ;
    END
  END q[259]
  PIN q[25]
    DIRECTION OUTPUT ;
    USE SIGNAL ;
    PORT
      LAYER M5 ;
        RECT  10.128 49.596 10.152 49.68 ;
    END
  END q[25]
  PIN q[260]
    DIRECTION OUTPUT ;
    USE SIGNAL ;
    PORT
      LAYER M5 ;
        RECT  43.968 49.596 43.992 49.68 ;
    END
  END q[260]
  PIN q[261]
    DIRECTION OUTPUT ;
    USE SIGNAL ;
    PORT
      LAYER M5 ;
        RECT  44.4 49.596 44.424 49.68 ;
    END
  END q[261]
  PIN q[262]
    DIRECTION OUTPUT ;
    USE SIGNAL ;
    PORT
      LAYER M5 ;
        RECT  44.112 49.596 44.136 49.68 ;
    END
  END q[262]
  PIN q[263]
    DIRECTION OUTPUT ;
    USE SIGNAL ;
    PORT
      LAYER M5 ;
        RECT  44.688 49.596 44.712 49.68 ;
    END
  END q[263]
  PIN q[264]
    DIRECTION OUTPUT ;
    USE SIGNAL ;
    PORT
      LAYER M5 ;
        RECT  44.544 49.596 44.568 49.68 ;
    END
  END q[264]
  PIN q[265]
    DIRECTION OUTPUT ;
    USE SIGNAL ;
    PORT
      LAYER M5 ;
        RECT  44.976 49.596 45 49.68 ;
    END
  END q[265]
  PIN q[266]
    DIRECTION OUTPUT ;
    USE SIGNAL ;
    PORT
      LAYER M5 ;
        RECT  44.832 49.596 44.856 49.68 ;
    END
  END q[266]
  PIN q[267]
    DIRECTION OUTPUT ;
    USE SIGNAL ;
    PORT
      LAYER M5 ;
        RECT  46.704 49.596 46.728 49.68 ;
    END
  END q[267]
  PIN q[268]
    DIRECTION OUTPUT ;
    USE SIGNAL ;
    PORT
      LAYER M5 ;
        RECT  45.12 49.596 45.144 49.68 ;
    END
  END q[268]
  PIN q[269]
    DIRECTION OUTPUT ;
    USE SIGNAL ;
    PORT
      LAYER M5 ;
        RECT  46.992 49.596 47.016 49.68 ;
    END
  END q[269]
  PIN q[26]
    DIRECTION OUTPUT ;
    USE SIGNAL ;
    PORT
      LAYER M5 ;
        RECT  10.56 49.596 10.584 49.68 ;
    END
  END q[26]
  PIN q[270]
    DIRECTION OUTPUT ;
    USE SIGNAL ;
    PORT
      LAYER M5 ;
        RECT  46.848 49.596 46.872 49.68 ;
    END
  END q[270]
  PIN q[271]
    DIRECTION OUTPUT ;
    USE SIGNAL ;
    PORT
      LAYER M5 ;
        RECT  47.136 49.596 47.16 49.68 ;
    END
  END q[271]
  PIN q[272]
    DIRECTION OUTPUT ;
    USE SIGNAL ;
    PORT
      LAYER M5 ;
        RECT  47.424 49.596 47.448 49.68 ;
    END
  END q[272]
  PIN q[273]
    DIRECTION OUTPUT ;
    USE SIGNAL ;
    PORT
      LAYER M5 ;
        RECT  47.28 49.596 47.304 49.68 ;
    END
  END q[273]
  PIN q[274]
    DIRECTION OUTPUT ;
    USE SIGNAL ;
    PORT
      LAYER M5 ;
        RECT  47.712 49.596 47.736 49.68 ;
    END
  END q[274]
  PIN q[275]
    DIRECTION OUTPUT ;
    USE SIGNAL ;
    PORT
      LAYER M5 ;
        RECT  47.568 49.596 47.592 49.68 ;
    END
  END q[275]
  PIN q[276]
    DIRECTION OUTPUT ;
    USE SIGNAL ;
    PORT
      LAYER M5 ;
        RECT  48 49.596 48.024 49.68 ;
    END
  END q[276]
  PIN q[277]
    DIRECTION OUTPUT ;
    USE SIGNAL ;
    PORT
      LAYER M5 ;
        RECT  47.856 49.596 47.88 49.68 ;
    END
  END q[277]
  PIN q[278]
    DIRECTION OUTPUT ;
    USE SIGNAL ;
    PORT
      LAYER M5 ;
        RECT  48.288 49.596 48.312 49.68 ;
    END
  END q[278]
  PIN q[279]
    DIRECTION OUTPUT ;
    USE SIGNAL ;
    PORT
      LAYER M5 ;
        RECT  48.144 49.596 48.168 49.68 ;
    END
  END q[279]
  PIN q[27]
    DIRECTION OUTPUT ;
    USE SIGNAL ;
    PORT
      LAYER M5 ;
        RECT  10.416 49.596 10.44 49.68 ;
    END
  END q[27]
  PIN q[280]
    DIRECTION OUTPUT ;
    USE SIGNAL ;
    PORT
      LAYER M5 ;
        RECT  48.576 49.596 48.6 49.68 ;
    END
  END q[280]
  PIN q[281]
    DIRECTION OUTPUT ;
    USE SIGNAL ;
    PORT
      LAYER M5 ;
        RECT  48.432 49.596 48.456 49.68 ;
    END
  END q[281]
  PIN q[282]
    DIRECTION OUTPUT ;
    USE SIGNAL ;
    PORT
      LAYER M5 ;
        RECT  48.864 49.596 48.888 49.68 ;
    END
  END q[282]
  PIN q[283]
    DIRECTION OUTPUT ;
    USE SIGNAL ;
    PORT
      LAYER M5 ;
        RECT  48.72 49.596 48.744 49.68 ;
    END
  END q[283]
  PIN q[284]
    DIRECTION OUTPUT ;
    USE SIGNAL ;
    PORT
      LAYER M5 ;
        RECT  49.008 49.596 49.032 49.68 ;
    END
  END q[284]
  PIN q[285]
    DIRECTION OUTPUT ;
    USE SIGNAL ;
    PORT
      LAYER M5 ;
        RECT  49.152 49.596 49.176 49.68 ;
    END
  END q[285]
  PIN q[286]
    DIRECTION OUTPUT ;
    USE SIGNAL ;
    PORT
      LAYER M5 ;
        RECT  49.44 49.596 49.464 49.68 ;
    END
  END q[286]
  PIN q[287]
    DIRECTION OUTPUT ;
    USE SIGNAL ;
    PORT
      LAYER M5 ;
        RECT  49.296 49.596 49.32 49.68 ;
    END
  END q[287]
  PIN q[288]
    DIRECTION OUTPUT ;
    USE SIGNAL ;
    PORT
      LAYER M5 ;
        RECT  49.584 49.596 49.608 49.68 ;
    END
  END q[288]
  PIN q[289]
    DIRECTION OUTPUT ;
    USE SIGNAL ;
    PORT
      LAYER M5 ;
        RECT  49.728 49.596 49.752 49.68 ;
    END
  END q[289]
  PIN q[28]
    DIRECTION OUTPUT ;
    USE SIGNAL ;
    PORT
      LAYER M5 ;
        RECT  10.848 49.596 10.872 49.68 ;
    END
  END q[28]
  PIN q[290]
    DIRECTION OUTPUT ;
    USE SIGNAL ;
    PORT
      LAYER M5 ;
        RECT  49.872 49.596 49.896 49.68 ;
    END
  END q[290]
  PIN q[291]
    DIRECTION OUTPUT ;
    USE SIGNAL ;
    PORT
      LAYER M5 ;
        RECT  50.016 49.596 50.04 49.68 ;
    END
  END q[291]
  PIN q[292]
    DIRECTION OUTPUT ;
    USE SIGNAL ;
    PORT
      LAYER M5 ;
        RECT  50.16 49.596 50.184 49.68 ;
    END
  END q[292]
  PIN q[293]
    DIRECTION OUTPUT ;
    USE SIGNAL ;
    PORT
      LAYER M5 ;
        RECT  50.304 49.596 50.328 49.68 ;
    END
  END q[293]
  PIN q[294]
    DIRECTION OUTPUT ;
    USE SIGNAL ;
    PORT
      LAYER M5 ;
        RECT  50.448 49.596 50.472 49.68 ;
    END
  END q[294]
  PIN q[295]
    DIRECTION OUTPUT ;
    USE SIGNAL ;
    PORT
      LAYER M5 ;
        RECT  50.592 49.596 50.616 49.68 ;
    END
  END q[295]
  PIN q[296]
    DIRECTION OUTPUT ;
    USE SIGNAL ;
    PORT
      LAYER M5 ;
        RECT  50.736 49.596 50.76 49.68 ;
    END
  END q[296]
  PIN q[297]
    DIRECTION OUTPUT ;
    USE SIGNAL ;
    PORT
      LAYER M5 ;
        RECT  50.88 49.596 50.904 49.68 ;
    END
  END q[297]
  PIN q[298]
    DIRECTION OUTPUT ;
    USE SIGNAL ;
    PORT
      LAYER M5 ;
        RECT  51.024 49.596 51.048 49.68 ;
    END
  END q[298]
  PIN q[299]
    DIRECTION OUTPUT ;
    USE SIGNAL ;
    PORT
      LAYER M5 ;
        RECT  51.168 49.596 51.192 49.68 ;
    END
  END q[299]
  PIN q[29]
    DIRECTION OUTPUT ;
    USE SIGNAL ;
    PORT
      LAYER M5 ;
        RECT  10.704 49.596 10.728 49.68 ;
    END
  END q[29]
  PIN q[2]
    DIRECTION OUTPUT ;
    USE SIGNAL ;
    PORT
      LAYER M5 ;
        RECT  6.96 49.596 6.984 49.68 ;
    END
  END q[2]
  PIN q[300]
    DIRECTION OUTPUT ;
    USE SIGNAL ;
    PORT
      LAYER M5 ;
        RECT  51.312 49.596 51.336 49.68 ;
    END
  END q[300]
  PIN q[301]
    DIRECTION OUTPUT ;
    USE SIGNAL ;
    PORT
      LAYER M5 ;
        RECT  51.456 49.596 51.48 49.68 ;
    END
  END q[301]
  PIN q[302]
    DIRECTION OUTPUT ;
    USE SIGNAL ;
    PORT
      LAYER M5 ;
        RECT  51.6 49.596 51.624 49.68 ;
    END
  END q[302]
  PIN q[303]
    DIRECTION OUTPUT ;
    USE SIGNAL ;
    PORT
      LAYER M5 ;
        RECT  51.888 49.596 51.912 49.68 ;
    END
  END q[303]
  PIN q[304]
    DIRECTION OUTPUT ;
    USE SIGNAL ;
    PORT
      LAYER M5 ;
        RECT  51.744 49.596 51.768 49.68 ;
    END
  END q[304]
  PIN q[305]
    DIRECTION OUTPUT ;
    USE SIGNAL ;
    PORT
      LAYER M5 ;
        RECT  52.176 49.596 52.2 49.68 ;
    END
  END q[305]
  PIN q[306]
    DIRECTION OUTPUT ;
    USE SIGNAL ;
    PORT
      LAYER M5 ;
        RECT  52.032 49.596 52.056 49.68 ;
    END
  END q[306]
  PIN q[307]
    DIRECTION OUTPUT ;
    USE SIGNAL ;
    PORT
      LAYER M5 ;
        RECT  52.464 49.596 52.488 49.68 ;
    END
  END q[307]
  PIN q[308]
    DIRECTION OUTPUT ;
    USE SIGNAL ;
    PORT
      LAYER M5 ;
        RECT  52.32 49.596 52.344 49.68 ;
    END
  END q[308]
  PIN q[309]
    DIRECTION OUTPUT ;
    USE SIGNAL ;
    PORT
      LAYER M5 ;
        RECT  52.896 49.596 52.92 49.68 ;
    END
  END q[309]
  PIN q[30]
    DIRECTION OUTPUT ;
    USE SIGNAL ;
    PORT
      LAYER M5 ;
        RECT  11.136 49.596 11.16 49.68 ;
    END
  END q[30]
  PIN q[310]
    DIRECTION OUTPUT ;
    USE SIGNAL ;
    PORT
      LAYER M5 ;
        RECT  52.608 49.596 52.632 49.68 ;
    END
  END q[310]
  PIN q[311]
    DIRECTION OUTPUT ;
    USE SIGNAL ;
    PORT
      LAYER M5 ;
        RECT  53.04 49.596 53.064 49.68 ;
    END
  END q[311]
  PIN q[312]
    DIRECTION OUTPUT ;
    USE SIGNAL ;
    PORT
      LAYER M5 ;
        RECT  52.752 49.596 52.776 49.68 ;
    END
  END q[312]
  PIN q[313]
    DIRECTION OUTPUT ;
    USE SIGNAL ;
    PORT
      LAYER M5 ;
        RECT  53.328 49.596 53.352 49.68 ;
    END
  END q[313]
  PIN q[314]
    DIRECTION OUTPUT ;
    USE SIGNAL ;
    PORT
      LAYER M5 ;
        RECT  53.184 49.596 53.208 49.68 ;
    END
  END q[314]
  PIN q[315]
    DIRECTION OUTPUT ;
    USE SIGNAL ;
    PORT
      LAYER M5 ;
        RECT  53.616 49.596 53.64 49.68 ;
    END
  END q[315]
  PIN q[316]
    DIRECTION OUTPUT ;
    USE SIGNAL ;
    PORT
      LAYER M5 ;
        RECT  53.472 49.596 53.496 49.68 ;
    END
  END q[316]
  PIN q[317]
    DIRECTION OUTPUT ;
    USE SIGNAL ;
    PORT
      LAYER M5 ;
        RECT  53.904 49.596 53.928 49.68 ;
    END
  END q[317]
  PIN q[318]
    DIRECTION OUTPUT ;
    USE SIGNAL ;
    PORT
      LAYER M5 ;
        RECT  53.76 49.596 53.784 49.68 ;
    END
  END q[318]
  PIN q[319]
    DIRECTION OUTPUT ;
    USE SIGNAL ;
    PORT
      LAYER M5 ;
        RECT  54.192 49.596 54.216 49.68 ;
    END
  END q[319]
  PIN q[31]
    DIRECTION OUTPUT ;
    USE SIGNAL ;
    PORT
      LAYER M5 ;
        RECT  10.992 49.596 11.016 49.68 ;
    END
  END q[31]
  PIN q[320]
    DIRECTION OUTPUT ;
    USE SIGNAL ;
    PORT
      LAYER M5 ;
        RECT  54.048 49.596 54.072 49.68 ;
    END
  END q[320]
  PIN q[321]
    DIRECTION OUTPUT ;
    USE SIGNAL ;
    PORT
      LAYER M5 ;
        RECT  54.336 49.596 54.36 49.68 ;
    END
  END q[321]
  PIN q[322]
    DIRECTION OUTPUT ;
    USE SIGNAL ;
    PORT
      LAYER M5 ;
        RECT  54.624 49.596 54.648 49.68 ;
    END
  END q[322]
  PIN q[323]
    DIRECTION OUTPUT ;
    USE SIGNAL ;
    PORT
      LAYER M5 ;
        RECT  54.48 49.596 54.504 49.68 ;
    END
  END q[323]
  PIN q[324]
    DIRECTION OUTPUT ;
    USE SIGNAL ;
    PORT
      LAYER M5 ;
        RECT  54.912 49.596 54.936 49.68 ;
    END
  END q[324]
  PIN q[325]
    DIRECTION OUTPUT ;
    USE SIGNAL ;
    PORT
      LAYER M5 ;
        RECT  54.768 49.596 54.792 49.68 ;
    END
  END q[325]
  PIN q[326]
    DIRECTION OUTPUT ;
    USE SIGNAL ;
    PORT
      LAYER M5 ;
        RECT  55.2 49.596 55.224 49.68 ;
    END
  END q[326]
  PIN q[327]
    DIRECTION OUTPUT ;
    USE SIGNAL ;
    PORT
      LAYER M5 ;
        RECT  55.056 49.596 55.08 49.68 ;
    END
  END q[327]
  PIN q[328]
    DIRECTION OUTPUT ;
    USE SIGNAL ;
    PORT
      LAYER M5 ;
        RECT  55.488 49.596 55.512 49.68 ;
    END
  END q[328]
  PIN q[329]
    DIRECTION OUTPUT ;
    USE SIGNAL ;
    PORT
      LAYER M5 ;
        RECT  55.344 49.596 55.368 49.68 ;
    END
  END q[329]
  PIN q[32]
    DIRECTION OUTPUT ;
    USE SIGNAL ;
    PORT
      LAYER M5 ;
        RECT  11.424 49.596 11.448 49.68 ;
    END
  END q[32]
  PIN q[330]
    DIRECTION OUTPUT ;
    USE SIGNAL ;
    PORT
      LAYER M5 ;
        RECT  55.776 49.596 55.8 49.68 ;
    END
  END q[330]
  PIN q[331]
    DIRECTION OUTPUT ;
    USE SIGNAL ;
    PORT
      LAYER M5 ;
        RECT  55.632 49.596 55.656 49.68 ;
    END
  END q[331]
  PIN q[332]
    DIRECTION OUTPUT ;
    USE SIGNAL ;
    PORT
      LAYER M5 ;
        RECT  56.064 49.596 56.088 49.68 ;
    END
  END q[332]
  PIN q[333]
    DIRECTION OUTPUT ;
    USE SIGNAL ;
    PORT
      LAYER M5 ;
        RECT  55.92 49.596 55.944 49.68 ;
    END
  END q[333]
  PIN q[334]
    DIRECTION OUTPUT ;
    USE SIGNAL ;
    PORT
      LAYER M5 ;
        RECT  56.208 49.596 56.232 49.68 ;
    END
  END q[334]
  PIN q[335]
    DIRECTION OUTPUT ;
    USE SIGNAL ;
    PORT
      LAYER M5 ;
        RECT  56.352 49.596 56.376 49.68 ;
    END
  END q[335]
  PIN q[336]
    DIRECTION OUTPUT ;
    USE SIGNAL ;
    PORT
      LAYER M5 ;
        RECT  56.496 49.596 56.52 49.68 ;
    END
  END q[336]
  PIN q[337]
    DIRECTION OUTPUT ;
    USE SIGNAL ;
    PORT
      LAYER M5 ;
        RECT  56.64 49.596 56.664 49.68 ;
    END
  END q[337]
  PIN q[338]
    DIRECTION OUTPUT ;
    USE SIGNAL ;
    PORT
      LAYER M5 ;
        RECT  56.784 49.596 56.808 49.68 ;
    END
  END q[338]
  PIN q[339]
    DIRECTION OUTPUT ;
    USE SIGNAL ;
    PORT
      LAYER M5 ;
        RECT  56.928 49.596 56.952 49.68 ;
    END
  END q[339]
  PIN q[33]
    DIRECTION OUTPUT ;
    USE SIGNAL ;
    PORT
      LAYER M5 ;
        RECT  11.28 49.596 11.304 49.68 ;
    END
  END q[33]
  PIN q[340]
    DIRECTION OUTPUT ;
    USE SIGNAL ;
    PORT
      LAYER M5 ;
        RECT  57.072 49.596 57.096 49.68 ;
    END
  END q[340]
  PIN q[341]
    DIRECTION OUTPUT ;
    USE SIGNAL ;
    PORT
      LAYER M5 ;
        RECT  57.216 49.596 57.24 49.68 ;
    END
  END q[341]
  PIN q[342]
    DIRECTION OUTPUT ;
    USE SIGNAL ;
    PORT
      LAYER M5 ;
        RECT  57.36 49.596 57.384 49.68 ;
    END
  END q[342]
  PIN q[343]
    DIRECTION OUTPUT ;
    USE SIGNAL ;
    PORT
      LAYER M5 ;
        RECT  57.504 49.596 57.528 49.68 ;
    END
  END q[343]
  PIN q[344]
    DIRECTION OUTPUT ;
    USE SIGNAL ;
    PORT
      LAYER M5 ;
        RECT  57.648 49.596 57.672 49.68 ;
    END
  END q[344]
  PIN q[345]
    DIRECTION OUTPUT ;
    USE SIGNAL ;
    PORT
      LAYER M5 ;
        RECT  57.792 49.596 57.816 49.68 ;
    END
  END q[345]
  PIN q[346]
    DIRECTION OUTPUT ;
    USE SIGNAL ;
    PORT
      LAYER M5 ;
        RECT  57.936 49.596 57.96 49.68 ;
    END
  END q[346]
  PIN q[347]
    DIRECTION OUTPUT ;
    USE SIGNAL ;
    PORT
      LAYER M5 ;
        RECT  58.08 49.596 58.104 49.68 ;
    END
  END q[347]
  PIN q[348]
    DIRECTION OUTPUT ;
    USE SIGNAL ;
    PORT
      LAYER M5 ;
        RECT  58.224 49.596 58.248 49.68 ;
    END
  END q[348]
  PIN q[349]
    DIRECTION OUTPUT ;
    USE SIGNAL ;
    PORT
      LAYER M5 ;
        RECT  58.368 49.596 58.392 49.68 ;
    END
  END q[349]
  PIN q[34]
    DIRECTION OUTPUT ;
    USE SIGNAL ;
    PORT
      LAYER M5 ;
        RECT  11.712 49.596 11.736 49.68 ;
    END
  END q[34]
  PIN q[350]
    DIRECTION OUTPUT ;
    USE SIGNAL ;
    PORT
      LAYER M5 ;
        RECT  58.512 49.596 58.536 49.68 ;
    END
  END q[350]
  PIN q[351]
    DIRECTION OUTPUT ;
    USE SIGNAL ;
    PORT
      LAYER M5 ;
        RECT  58.8 49.596 58.824 49.68 ;
    END
  END q[351]
  PIN q[352]
    DIRECTION OUTPUT ;
    USE SIGNAL ;
    PORT
      LAYER M5 ;
        RECT  58.656 49.596 58.68 49.68 ;
    END
  END q[352]
  PIN q[353]
    DIRECTION OUTPUT ;
    USE SIGNAL ;
    PORT
      LAYER M5 ;
        RECT  59.088 49.596 59.112 49.68 ;
    END
  END q[353]
  PIN q[354]
    DIRECTION OUTPUT ;
    USE SIGNAL ;
    PORT
      LAYER M5 ;
        RECT  58.944 49.596 58.968 49.68 ;
    END
  END q[354]
  PIN q[355]
    DIRECTION OUTPUT ;
    USE SIGNAL ;
    PORT
      LAYER M5 ;
        RECT  59.376 49.596 59.4 49.68 ;
    END
  END q[355]
  PIN q[356]
    DIRECTION OUTPUT ;
    USE SIGNAL ;
    PORT
      LAYER M5 ;
        RECT  59.232 49.596 59.256 49.68 ;
    END
  END q[356]
  PIN q[357]
    DIRECTION OUTPUT ;
    USE SIGNAL ;
    PORT
      LAYER M5 ;
        RECT  59.664 49.596 59.688 49.68 ;
    END
  END q[357]
  PIN q[358]
    DIRECTION OUTPUT ;
    USE SIGNAL ;
    PORT
      LAYER M5 ;
        RECT  59.52 49.596 59.544 49.68 ;
    END
  END q[358]
  PIN q[359]
    DIRECTION OUTPUT ;
    USE SIGNAL ;
    PORT
      LAYER M5 ;
        RECT  60.096 49.596 60.12 49.68 ;
    END
  END q[359]
  PIN q[35]
    DIRECTION OUTPUT ;
    USE SIGNAL ;
    PORT
      LAYER M5 ;
        RECT  11.568 49.596 11.592 49.68 ;
    END
  END q[35]
  PIN q[360]
    DIRECTION OUTPUT ;
    USE SIGNAL ;
    PORT
      LAYER M5 ;
        RECT  59.808 49.596 59.832 49.68 ;
    END
  END q[360]
  PIN q[361]
    DIRECTION OUTPUT ;
    USE SIGNAL ;
    PORT
      LAYER M5 ;
        RECT  60.24 49.596 60.264 49.68 ;
    END
  END q[361]
  PIN q[362]
    DIRECTION OUTPUT ;
    USE SIGNAL ;
    PORT
      LAYER M5 ;
        RECT  59.952 49.596 59.976 49.68 ;
    END
  END q[362]
  PIN q[363]
    DIRECTION OUTPUT ;
    USE SIGNAL ;
    PORT
      LAYER M5 ;
        RECT  60.528 49.596 60.552 49.68 ;
    END
  END q[363]
  PIN q[364]
    DIRECTION OUTPUT ;
    USE SIGNAL ;
    PORT
      LAYER M5 ;
        RECT  60.384 49.596 60.408 49.68 ;
    END
  END q[364]
  PIN q[365]
    DIRECTION OUTPUT ;
    USE SIGNAL ;
    PORT
      LAYER M5 ;
        RECT  60.816 49.596 60.84 49.68 ;
    END
  END q[365]
  PIN q[366]
    DIRECTION OUTPUT ;
    USE SIGNAL ;
    PORT
      LAYER M5 ;
        RECT  60.672 49.596 60.696 49.68 ;
    END
  END q[366]
  PIN q[367]
    DIRECTION OUTPUT ;
    USE SIGNAL ;
    PORT
      LAYER M5 ;
        RECT  61.248 49.596 61.272 49.68 ;
    END
  END q[367]
  PIN q[368]
    DIRECTION OUTPUT ;
    USE SIGNAL ;
    PORT
      LAYER M5 ;
        RECT  60.96 49.596 60.984 49.68 ;
    END
  END q[368]
  PIN q[369]
    DIRECTION OUTPUT ;
    USE SIGNAL ;
    PORT
      LAYER M5 ;
        RECT  61.536 49.596 61.56 49.68 ;
    END
  END q[369]
  PIN q[36]
    DIRECTION OUTPUT ;
    USE SIGNAL ;
    PORT
      LAYER M5 ;
        RECT  12 49.596 12.024 49.68 ;
    END
  END q[36]
  PIN q[370]
    DIRECTION OUTPUT ;
    USE SIGNAL ;
    PORT
      LAYER M5 ;
        RECT  61.104 49.596 61.128 49.68 ;
    END
  END q[370]
  PIN q[371]
    DIRECTION OUTPUT ;
    USE SIGNAL ;
    PORT
      LAYER M5 ;
        RECT  61.68 49.596 61.704 49.68 ;
    END
  END q[371]
  PIN q[372]
    DIRECTION OUTPUT ;
    USE SIGNAL ;
    PORT
      LAYER M5 ;
        RECT  61.392 49.596 61.416 49.68 ;
    END
  END q[372]
  PIN q[373]
    DIRECTION OUTPUT ;
    USE SIGNAL ;
    PORT
      LAYER M5 ;
        RECT  61.824 49.596 61.848 49.68 ;
    END
  END q[373]
  PIN q[374]
    DIRECTION OUTPUT ;
    USE SIGNAL ;
    PORT
      LAYER M5 ;
        RECT  62.112 49.596 62.136 49.68 ;
    END
  END q[374]
  PIN q[375]
    DIRECTION OUTPUT ;
    USE SIGNAL ;
    PORT
      LAYER M5 ;
        RECT  61.968 49.596 61.992 49.68 ;
    END
  END q[375]
  PIN q[376]
    DIRECTION OUTPUT ;
    USE SIGNAL ;
    PORT
      LAYER M5 ;
        RECT  62.4 49.596 62.424 49.68 ;
    END
  END q[376]
  PIN q[377]
    DIRECTION OUTPUT ;
    USE SIGNAL ;
    PORT
      LAYER M5 ;
        RECT  62.256 49.596 62.28 49.68 ;
    END
  END q[377]
  PIN q[378]
    DIRECTION OUTPUT ;
    USE SIGNAL ;
    PORT
      LAYER M5 ;
        RECT  62.688 49.596 62.712 49.68 ;
    END
  END q[378]
  PIN q[379]
    DIRECTION OUTPUT ;
    USE SIGNAL ;
    PORT
      LAYER M5 ;
        RECT  62.544 49.596 62.568 49.68 ;
    END
  END q[379]
  PIN q[37]
    DIRECTION OUTPUT ;
    USE SIGNAL ;
    PORT
      LAYER M5 ;
        RECT  11.856 49.596 11.88 49.68 ;
    END
  END q[37]
  PIN q[380]
    DIRECTION OUTPUT ;
    USE SIGNAL ;
    PORT
      LAYER M5 ;
        RECT  62.976 49.596 63 49.68 ;
    END
  END q[380]
  PIN q[381]
    DIRECTION OUTPUT ;
    USE SIGNAL ;
    PORT
      LAYER M5 ;
        RECT  62.832 49.596 62.856 49.68 ;
    END
  END q[381]
  PIN q[382]
    DIRECTION OUTPUT ;
    USE SIGNAL ;
    PORT
      LAYER M5 ;
        RECT  63.264 49.596 63.288 49.68 ;
    END
  END q[382]
  PIN q[383]
    DIRECTION OUTPUT ;
    USE SIGNAL ;
    PORT
      LAYER M5 ;
        RECT  63.12 49.596 63.144 49.68 ;
    END
  END q[383]
  PIN q[384]
    DIRECTION OUTPUT ;
    USE SIGNAL ;
    PORT
      LAYER M5 ;
        RECT  63.408 49.596 63.432 49.68 ;
    END
  END q[384]
  PIN q[385]
    DIRECTION OUTPUT ;
    USE SIGNAL ;
    PORT
      LAYER M5 ;
        RECT  63.552 49.596 63.576 49.68 ;
    END
  END q[385]
  PIN q[386]
    DIRECTION OUTPUT ;
    USE SIGNAL ;
    PORT
      LAYER M5 ;
        RECT  63.696 49.596 63.72 49.68 ;
    END
  END q[386]
  PIN q[387]
    DIRECTION OUTPUT ;
    USE SIGNAL ;
    PORT
      LAYER M5 ;
        RECT  63.84 49.596 63.864 49.68 ;
    END
  END q[387]
  PIN q[388]
    DIRECTION OUTPUT ;
    USE SIGNAL ;
    PORT
      LAYER M5 ;
        RECT  63.984 49.596 64.008 49.68 ;
    END
  END q[388]
  PIN q[389]
    DIRECTION OUTPUT ;
    USE SIGNAL ;
    PORT
      LAYER M5 ;
        RECT  64.128 49.596 64.152 49.68 ;
    END
  END q[389]
  PIN q[38]
    DIRECTION OUTPUT ;
    USE SIGNAL ;
    PORT
      LAYER M5 ;
        RECT  12.144 49.596 12.168 49.68 ;
    END
  END q[38]
  PIN q[390]
    DIRECTION OUTPUT ;
    USE SIGNAL ;
    PORT
      LAYER M5 ;
        RECT  64.272 49.596 64.296 49.68 ;
    END
  END q[390]
  PIN q[391]
    DIRECTION OUTPUT ;
    USE SIGNAL ;
    PORT
      LAYER M5 ;
        RECT  64.416 49.596 64.44 49.68 ;
    END
  END q[391]
  PIN q[392]
    DIRECTION OUTPUT ;
    USE SIGNAL ;
    PORT
      LAYER M5 ;
        RECT  64.56 49.596 64.584 49.68 ;
    END
  END q[392]
  PIN q[393]
    DIRECTION OUTPUT ;
    USE SIGNAL ;
    PORT
      LAYER M5 ;
        RECT  64.704 49.596 64.728 49.68 ;
    END
  END q[393]
  PIN q[394]
    DIRECTION OUTPUT ;
    USE SIGNAL ;
    PORT
      LAYER M5 ;
        RECT  64.848 49.596 64.872 49.68 ;
    END
  END q[394]
  PIN q[395]
    DIRECTION OUTPUT ;
    USE SIGNAL ;
    PORT
      LAYER M5 ;
        RECT  64.992 49.596 65.016 49.68 ;
    END
  END q[395]
  PIN q[396]
    DIRECTION OUTPUT ;
    USE SIGNAL ;
    PORT
      LAYER M5 ;
        RECT  65.136 49.596 65.16 49.68 ;
    END
  END q[396]
  PIN q[397]
    DIRECTION OUTPUT ;
    USE SIGNAL ;
    PORT
      LAYER M5 ;
        RECT  65.28 49.596 65.304 49.68 ;
    END
  END q[397]
  PIN q[398]
    DIRECTION OUTPUT ;
    USE SIGNAL ;
    PORT
      LAYER M5 ;
        RECT  65.424 49.596 65.448 49.68 ;
    END
  END q[398]
  PIN q[399]
    DIRECTION OUTPUT ;
    USE SIGNAL ;
    PORT
      LAYER M5 ;
        RECT  65.712 49.596 65.736 49.68 ;
    END
  END q[399]
  PIN q[39]
    DIRECTION OUTPUT ;
    USE SIGNAL ;
    PORT
      LAYER M5 ;
        RECT  12.288 49.596 12.312 49.68 ;
    END
  END q[39]
  PIN q[3]
    DIRECTION OUTPUT ;
    USE SIGNAL ;
    PORT
      LAYER M5 ;
        RECT  7.104 49.596 7.128 49.68 ;
    END
  END q[3]
  PIN q[400]
    DIRECTION OUTPUT ;
    USE SIGNAL ;
    PORT
      LAYER M5 ;
        RECT  65.568 49.596 65.592 49.68 ;
    END
  END q[400]
  PIN q[401]
    DIRECTION OUTPUT ;
    USE SIGNAL ;
    PORT
      LAYER M5 ;
        RECT  66 49.596 66.024 49.68 ;
    END
  END q[401]
  PIN q[402]
    DIRECTION OUTPUT ;
    USE SIGNAL ;
    PORT
      LAYER M5 ;
        RECT  65.856 49.596 65.88 49.68 ;
    END
  END q[402]
  PIN q[403]
    DIRECTION OUTPUT ;
    USE SIGNAL ;
    PORT
      LAYER M5 ;
        RECT  66.288 49.596 66.312 49.68 ;
    END
  END q[403]
  PIN q[404]
    DIRECTION OUTPUT ;
    USE SIGNAL ;
    PORT
      LAYER M5 ;
        RECT  66.144 49.596 66.168 49.68 ;
    END
  END q[404]
  PIN q[405]
    DIRECTION OUTPUT ;
    USE SIGNAL ;
    PORT
      LAYER M5 ;
        RECT  66.576 49.596 66.6 49.68 ;
    END
  END q[405]
  PIN q[406]
    DIRECTION OUTPUT ;
    USE SIGNAL ;
    PORT
      LAYER M5 ;
        RECT  66.432 49.596 66.456 49.68 ;
    END
  END q[406]
  PIN q[407]
    DIRECTION OUTPUT ;
    USE SIGNAL ;
    PORT
      LAYER M5 ;
        RECT  66.864 49.596 66.888 49.68 ;
    END
  END q[407]
  PIN q[408]
    DIRECTION OUTPUT ;
    USE SIGNAL ;
    PORT
      LAYER M5 ;
        RECT  66.72 49.596 66.744 49.68 ;
    END
  END q[408]
  PIN q[409]
    DIRECTION OUTPUT ;
    USE SIGNAL ;
    PORT
      LAYER M5 ;
        RECT  67.296 49.596 67.32 49.68 ;
    END
  END q[409]
  PIN q[40]
    DIRECTION OUTPUT ;
    USE SIGNAL ;
    PORT
      LAYER M5 ;
        RECT  12.432 49.596 12.456 49.68 ;
    END
  END q[40]
  PIN q[410]
    DIRECTION OUTPUT ;
    USE SIGNAL ;
    PORT
      LAYER M5 ;
        RECT  67.008 49.596 67.032 49.68 ;
    END
  END q[410]
  PIN q[411]
    DIRECTION OUTPUT ;
    USE SIGNAL ;
    PORT
      LAYER M5 ;
        RECT  67.44 49.596 67.464 49.68 ;
    END
  END q[411]
  PIN q[412]
    DIRECTION OUTPUT ;
    USE SIGNAL ;
    PORT
      LAYER M5 ;
        RECT  67.152 49.596 67.176 49.68 ;
    END
  END q[412]
  PIN q[413]
    DIRECTION OUTPUT ;
    USE SIGNAL ;
    PORT
      LAYER M5 ;
        RECT  67.872 49.596 67.896 49.68 ;
    END
  END q[413]
  PIN q[414]
    DIRECTION OUTPUT ;
    USE SIGNAL ;
    PORT
      LAYER M5 ;
        RECT  67.584 49.596 67.608 49.68 ;
    END
  END q[414]
  PIN q[415]
    DIRECTION OUTPUT ;
    USE SIGNAL ;
    PORT
      LAYER M5 ;
        RECT  68.16 49.596 68.184 49.68 ;
    END
  END q[415]
  PIN q[416]
    DIRECTION OUTPUT ;
    USE SIGNAL ;
    PORT
      LAYER M5 ;
        RECT  67.728 49.596 67.752 49.68 ;
    END
  END q[416]
  PIN q[417]
    DIRECTION OUTPUT ;
    USE SIGNAL ;
    PORT
      LAYER M5 ;
        RECT  68.448 49.596 68.472 49.68 ;
    END
  END q[417]
  PIN q[418]
    DIRECTION OUTPUT ;
    USE SIGNAL ;
    PORT
      LAYER M5 ;
        RECT  68.016 49.596 68.04 49.68 ;
    END
  END q[418]
  PIN q[419]
    DIRECTION OUTPUT ;
    USE SIGNAL ;
    PORT
      LAYER M5 ;
        RECT  68.736 49.596 68.76 49.68 ;
    END
  END q[419]
  PIN q[41]
    DIRECTION OUTPUT ;
    USE SIGNAL ;
    PORT
      LAYER M5 ;
        RECT  12.576 49.596 12.6 49.68 ;
    END
  END q[41]
  PIN q[420]
    DIRECTION OUTPUT ;
    USE SIGNAL ;
    PORT
      LAYER M5 ;
        RECT  68.304 49.596 68.328 49.68 ;
    END
  END q[420]
  PIN q[421]
    DIRECTION OUTPUT ;
    USE SIGNAL ;
    PORT
      LAYER M5 ;
        RECT  68.88 49.596 68.904 49.68 ;
    END
  END q[421]
  PIN q[422]
    DIRECTION OUTPUT ;
    USE SIGNAL ;
    PORT
      LAYER M5 ;
        RECT  68.592 49.596 68.616 49.68 ;
    END
  END q[422]
  PIN q[423]
    DIRECTION OUTPUT ;
    USE SIGNAL ;
    PORT
      LAYER M5 ;
        RECT  69.024 49.596 69.048 49.68 ;
    END
  END q[423]
  PIN q[424]
    DIRECTION OUTPUT ;
    USE SIGNAL ;
    PORT
      LAYER M5 ;
        RECT  69.312 49.596 69.336 49.68 ;
    END
  END q[424]
  PIN q[425]
    DIRECTION OUTPUT ;
    USE SIGNAL ;
    PORT
      LAYER M5 ;
        RECT  69.168 49.596 69.192 49.68 ;
    END
  END q[425]
  PIN q[426]
    DIRECTION OUTPUT ;
    USE SIGNAL ;
    PORT
      LAYER M5 ;
        RECT  69.6 49.596 69.624 49.68 ;
    END
  END q[426]
  PIN q[427]
    DIRECTION OUTPUT ;
    USE SIGNAL ;
    PORT
      LAYER M5 ;
        RECT  69.456 49.596 69.48 49.68 ;
    END
  END q[427]
  PIN q[428]
    DIRECTION OUTPUT ;
    USE SIGNAL ;
    PORT
      LAYER M5 ;
        RECT  69.888 49.596 69.912 49.68 ;
    END
  END q[428]
  PIN q[429]
    DIRECTION OUTPUT ;
    USE SIGNAL ;
    PORT
      LAYER M5 ;
        RECT  69.744 49.596 69.768 49.68 ;
    END
  END q[429]
  PIN q[42]
    DIRECTION OUTPUT ;
    USE SIGNAL ;
    PORT
      LAYER M5 ;
        RECT  12.72 49.596 12.744 49.68 ;
    END
  END q[42]
  PIN q[430]
    DIRECTION OUTPUT ;
    USE SIGNAL ;
    PORT
      LAYER M5 ;
        RECT  70.176 49.596 70.2 49.68 ;
    END
  END q[430]
  PIN q[431]
    DIRECTION OUTPUT ;
    USE SIGNAL ;
    PORT
      LAYER M5 ;
        RECT  70.032 49.596 70.056 49.68 ;
    END
  END q[431]
  PIN q[432]
    DIRECTION OUTPUT ;
    USE SIGNAL ;
    PORT
      LAYER M5 ;
        RECT  70.464 49.596 70.488 49.68 ;
    END
  END q[432]
  PIN q[433]
    DIRECTION OUTPUT ;
    USE SIGNAL ;
    PORT
      LAYER M5 ;
        RECT  70.32 49.596 70.344 49.68 ;
    END
  END q[433]
  PIN q[434]
    DIRECTION OUTPUT ;
    USE SIGNAL ;
    PORT
      LAYER M5 ;
        RECT  70.608 49.596 70.632 49.68 ;
    END
  END q[434]
  PIN q[435]
    DIRECTION OUTPUT ;
    USE SIGNAL ;
    PORT
      LAYER M5 ;
        RECT  70.752 49.596 70.776 49.68 ;
    END
  END q[435]
  PIN q[436]
    DIRECTION OUTPUT ;
    USE SIGNAL ;
    PORT
      LAYER M5 ;
        RECT  70.896 49.596 70.92 49.68 ;
    END
  END q[436]
  PIN q[437]
    DIRECTION OUTPUT ;
    USE SIGNAL ;
    PORT
      LAYER M5 ;
        RECT  71.04 49.596 71.064 49.68 ;
    END
  END q[437]
  PIN q[438]
    DIRECTION OUTPUT ;
    USE SIGNAL ;
    PORT
      LAYER M5 ;
        RECT  71.184 49.596 71.208 49.68 ;
    END
  END q[438]
  PIN q[439]
    DIRECTION OUTPUT ;
    USE SIGNAL ;
    PORT
      LAYER M5 ;
        RECT  71.328 49.596 71.352 49.68 ;
    END
  END q[439]
  PIN q[43]
    DIRECTION OUTPUT ;
    USE SIGNAL ;
    PORT
      LAYER M5 ;
        RECT  12.864 49.596 12.888 49.68 ;
    END
  END q[43]
  PIN q[440]
    DIRECTION OUTPUT ;
    USE SIGNAL ;
    PORT
      LAYER M5 ;
        RECT  71.472 49.596 71.496 49.68 ;
    END
  END q[440]
  PIN q[441]
    DIRECTION OUTPUT ;
    USE SIGNAL ;
    PORT
      LAYER M5 ;
        RECT  71.616 49.596 71.64 49.68 ;
    END
  END q[441]
  PIN q[442]
    DIRECTION OUTPUT ;
    USE SIGNAL ;
    PORT
      LAYER M5 ;
        RECT  71.76 49.596 71.784 49.68 ;
    END
  END q[442]
  PIN q[443]
    DIRECTION OUTPUT ;
    USE SIGNAL ;
    PORT
      LAYER M5 ;
        RECT  71.904 49.596 71.928 49.68 ;
    END
  END q[443]
  PIN q[444]
    DIRECTION OUTPUT ;
    USE SIGNAL ;
    PORT
      LAYER M5 ;
        RECT  72.048 49.596 72.072 49.68 ;
    END
  END q[444]
  PIN q[445]
    DIRECTION OUTPUT ;
    USE SIGNAL ;
    PORT
      LAYER M5 ;
        RECT  72.192 49.596 72.216 49.68 ;
    END
  END q[445]
  PIN q[446]
    DIRECTION OUTPUT ;
    USE SIGNAL ;
    PORT
      LAYER M5 ;
        RECT  72.336 49.596 72.36 49.68 ;
    END
  END q[446]
  PIN q[447]
    DIRECTION OUTPUT ;
    USE SIGNAL ;
    PORT
      LAYER M5 ;
        RECT  72.48 49.596 72.504 49.68 ;
    END
  END q[447]
  PIN q[448]
    DIRECTION OUTPUT ;
    USE SIGNAL ;
    PORT
      LAYER M5 ;
        RECT  72.624 49.596 72.648 49.68 ;
    END
  END q[448]
  PIN q[449]
    DIRECTION OUTPUT ;
    USE SIGNAL ;
    PORT
      LAYER M5 ;
        RECT  72.912 49.596 72.936 49.68 ;
    END
  END q[449]
  PIN q[44]
    DIRECTION OUTPUT ;
    USE SIGNAL ;
    PORT
      LAYER M5 ;
        RECT  13.008 49.596 13.032 49.68 ;
    END
  END q[44]
  PIN q[450]
    DIRECTION OUTPUT ;
    USE SIGNAL ;
    PORT
      LAYER M5 ;
        RECT  72.768 49.596 72.792 49.68 ;
    END
  END q[450]
  PIN q[451]
    DIRECTION OUTPUT ;
    USE SIGNAL ;
    PORT
      LAYER M5 ;
        RECT  73.2 49.596 73.224 49.68 ;
    END
  END q[451]
  PIN q[452]
    DIRECTION OUTPUT ;
    USE SIGNAL ;
    PORT
      LAYER M5 ;
        RECT  73.056 49.596 73.08 49.68 ;
    END
  END q[452]
  PIN q[453]
    DIRECTION OUTPUT ;
    USE SIGNAL ;
    PORT
      LAYER M5 ;
        RECT  73.488 49.596 73.512 49.68 ;
    END
  END q[453]
  PIN q[454]
    DIRECTION OUTPUT ;
    USE SIGNAL ;
    PORT
      LAYER M5 ;
        RECT  73.344 49.596 73.368 49.68 ;
    END
  END q[454]
  PIN q[455]
    DIRECTION OUTPUT ;
    USE SIGNAL ;
    PORT
      LAYER M5 ;
        RECT  73.776 49.596 73.8 49.68 ;
    END
  END q[455]
  PIN q[456]
    DIRECTION OUTPUT ;
    USE SIGNAL ;
    PORT
      LAYER M5 ;
        RECT  73.632 49.596 73.656 49.68 ;
    END
  END q[456]
  PIN q[457]
    DIRECTION OUTPUT ;
    USE SIGNAL ;
    PORT
      LAYER M5 ;
        RECT  74.064 49.596 74.088 49.68 ;
    END
  END q[457]
  PIN q[458]
    DIRECTION OUTPUT ;
    USE SIGNAL ;
    PORT
      LAYER M5 ;
        RECT  73.92 49.596 73.944 49.68 ;
    END
  END q[458]
  PIN q[459]
    DIRECTION OUTPUT ;
    USE SIGNAL ;
    PORT
      LAYER M5 ;
        RECT  74.496 49.596 74.52 49.68 ;
    END
  END q[459]
  PIN q[45]
    DIRECTION OUTPUT ;
    USE SIGNAL ;
    PORT
      LAYER M5 ;
        RECT  13.152 49.596 13.176 49.68 ;
    END
  END q[45]
  PIN q[460]
    DIRECTION OUTPUT ;
    USE SIGNAL ;
    PORT
      LAYER M5 ;
        RECT  74.208 49.596 74.232 49.68 ;
    END
  END q[460]
  PIN q[461]
    DIRECTION OUTPUT ;
    USE SIGNAL ;
    PORT
      LAYER M5 ;
        RECT  74.64 49.596 74.664 49.68 ;
    END
  END q[461]
  PIN q[462]
    DIRECTION OUTPUT ;
    USE SIGNAL ;
    PORT
      LAYER M5 ;
        RECT  74.352 49.596 74.376 49.68 ;
    END
  END q[462]
  PIN q[463]
    DIRECTION OUTPUT ;
    USE SIGNAL ;
    PORT
      LAYER M5 ;
        RECT  75.072 49.596 75.096 49.68 ;
    END
  END q[463]
  PIN q[464]
    DIRECTION OUTPUT ;
    USE SIGNAL ;
    PORT
      LAYER M5 ;
        RECT  74.784 49.596 74.808 49.68 ;
    END
  END q[464]
  PIN q[465]
    DIRECTION OUTPUT ;
    USE SIGNAL ;
    PORT
      LAYER M5 ;
        RECT  75.36 49.596 75.384 49.68 ;
    END
  END q[465]
  PIN q[466]
    DIRECTION OUTPUT ;
    USE SIGNAL ;
    PORT
      LAYER M5 ;
        RECT  74.928 49.596 74.952 49.68 ;
    END
  END q[466]
  PIN q[467]
    DIRECTION OUTPUT ;
    USE SIGNAL ;
    PORT
      LAYER M5 ;
        RECT  75.648 49.596 75.672 49.68 ;
    END
  END q[467]
  PIN q[468]
    DIRECTION OUTPUT ;
    USE SIGNAL ;
    PORT
      LAYER M5 ;
        RECT  75.216 49.596 75.24 49.68 ;
    END
  END q[468]
  PIN q[469]
    DIRECTION OUTPUT ;
    USE SIGNAL ;
    PORT
      LAYER M5 ;
        RECT  75.936 49.596 75.96 49.68 ;
    END
  END q[469]
  PIN q[46]
    DIRECTION OUTPUT ;
    USE SIGNAL ;
    PORT
      LAYER M5 ;
        RECT  13.296 49.596 13.32 49.68 ;
    END
  END q[46]
  PIN q[470]
    DIRECTION OUTPUT ;
    USE SIGNAL ;
    PORT
      LAYER M5 ;
        RECT  75.504 49.596 75.528 49.68 ;
    END
  END q[470]
  PIN q[471]
    DIRECTION OUTPUT ;
    USE SIGNAL ;
    PORT
      LAYER M5 ;
        RECT  76.08 49.596 76.104 49.68 ;
    END
  END q[471]
  PIN q[472]
    DIRECTION OUTPUT ;
    USE SIGNAL ;
    PORT
      LAYER M5 ;
        RECT  75.792 49.596 75.816 49.68 ;
    END
  END q[472]
  PIN q[473]
    DIRECTION OUTPUT ;
    USE SIGNAL ;
    PORT
      LAYER M5 ;
        RECT  76.224 49.596 76.248 49.68 ;
    END
  END q[473]
  PIN q[474]
    DIRECTION OUTPUT ;
    USE SIGNAL ;
    PORT
      LAYER M5 ;
        RECT  76.512 49.596 76.536 49.68 ;
    END
  END q[474]
  PIN q[475]
    DIRECTION OUTPUT ;
    USE SIGNAL ;
    PORT
      LAYER M5 ;
        RECT  76.368 49.596 76.392 49.68 ;
    END
  END q[475]
  PIN q[476]
    DIRECTION OUTPUT ;
    USE SIGNAL ;
    PORT
      LAYER M5 ;
        RECT  76.8 49.596 76.824 49.68 ;
    END
  END q[476]
  PIN q[477]
    DIRECTION OUTPUT ;
    USE SIGNAL ;
    PORT
      LAYER M5 ;
        RECT  76.656 49.596 76.68 49.68 ;
    END
  END q[477]
  PIN q[478]
    DIRECTION OUTPUT ;
    USE SIGNAL ;
    PORT
      LAYER M5 ;
        RECT  77.088 49.596 77.112 49.68 ;
    END
  END q[478]
  PIN q[479]
    DIRECTION OUTPUT ;
    USE SIGNAL ;
    PORT
      LAYER M5 ;
        RECT  76.944 49.596 76.968 49.68 ;
    END
  END q[479]
  PIN q[47]
    DIRECTION OUTPUT ;
    USE SIGNAL ;
    PORT
      LAYER M5 ;
        RECT  13.44 49.596 13.464 49.68 ;
    END
  END q[47]
  PIN q[480]
    DIRECTION OUTPUT ;
    USE SIGNAL ;
    PORT
      LAYER M5 ;
        RECT  77.376 49.596 77.4 49.68 ;
    END
  END q[480]
  PIN q[481]
    DIRECTION OUTPUT ;
    USE SIGNAL ;
    PORT
      LAYER M5 ;
        RECT  77.232 49.596 77.256 49.68 ;
    END
  END q[481]
  PIN q[482]
    DIRECTION OUTPUT ;
    USE SIGNAL ;
    PORT
      LAYER M5 ;
        RECT  77.664 49.596 77.688 49.68 ;
    END
  END q[482]
  PIN q[483]
    DIRECTION OUTPUT ;
    USE SIGNAL ;
    PORT
      LAYER M5 ;
        RECT  77.52 49.596 77.544 49.68 ;
    END
  END q[483]
  PIN q[484]
    DIRECTION OUTPUT ;
    USE SIGNAL ;
    PORT
      LAYER M5 ;
        RECT  77.808 49.596 77.832 49.68 ;
    END
  END q[484]
  PIN q[485]
    DIRECTION OUTPUT ;
    USE SIGNAL ;
    PORT
      LAYER M5 ;
        RECT  77.952 49.596 77.976 49.68 ;
    END
  END q[485]
  PIN q[486]
    DIRECTION OUTPUT ;
    USE SIGNAL ;
    PORT
      LAYER M5 ;
        RECT  78.096 49.596 78.12 49.68 ;
    END
  END q[486]
  PIN q[487]
    DIRECTION OUTPUT ;
    USE SIGNAL ;
    PORT
      LAYER M5 ;
        RECT  78.24 49.596 78.264 49.68 ;
    END
  END q[487]
  PIN q[488]
    DIRECTION OUTPUT ;
    USE SIGNAL ;
    PORT
      LAYER M5 ;
        RECT  78.384 49.596 78.408 49.68 ;
    END
  END q[488]
  PIN q[489]
    DIRECTION OUTPUT ;
    USE SIGNAL ;
    PORT
      LAYER M5 ;
        RECT  78.528 49.596 78.552 49.68 ;
    END
  END q[489]
  PIN q[48]
    DIRECTION OUTPUT ;
    USE SIGNAL ;
    PORT
      LAYER M5 ;
        RECT  13.584 49.596 13.608 49.68 ;
    END
  END q[48]
  PIN q[490]
    DIRECTION OUTPUT ;
    USE SIGNAL ;
    PORT
      LAYER M5 ;
        RECT  78.672 49.596 78.696 49.68 ;
    END
  END q[490]
  PIN q[491]
    DIRECTION OUTPUT ;
    USE SIGNAL ;
    PORT
      LAYER M5 ;
        RECT  78.816 49.596 78.84 49.68 ;
    END
  END q[491]
  PIN q[492]
    DIRECTION OUTPUT ;
    USE SIGNAL ;
    PORT
      LAYER M5 ;
        RECT  78.96 49.596 78.984 49.68 ;
    END
  END q[492]
  PIN q[493]
    DIRECTION OUTPUT ;
    USE SIGNAL ;
    PORT
      LAYER M5 ;
        RECT  79.104 49.596 79.128 49.68 ;
    END
  END q[493]
  PIN q[494]
    DIRECTION OUTPUT ;
    USE SIGNAL ;
    PORT
      LAYER M5 ;
        RECT  79.248 49.596 79.272 49.68 ;
    END
  END q[494]
  PIN q[495]
    DIRECTION OUTPUT ;
    USE SIGNAL ;
    PORT
      LAYER M5 ;
        RECT  79.392 49.596 79.416 49.68 ;
    END
  END q[495]
  PIN q[496]
    DIRECTION OUTPUT ;
    USE SIGNAL ;
    PORT
      LAYER M5 ;
        RECT  79.536 49.596 79.56 49.68 ;
    END
  END q[496]
  PIN q[497]
    DIRECTION OUTPUT ;
    USE SIGNAL ;
    PORT
      LAYER M5 ;
        RECT  79.68 49.596 79.704 49.68 ;
    END
  END q[497]
  PIN q[498]
    DIRECTION OUTPUT ;
    USE SIGNAL ;
    PORT
      LAYER M5 ;
        RECT  79.824 49.596 79.848 49.68 ;
    END
  END q[498]
  PIN q[499]
    DIRECTION OUTPUT ;
    USE SIGNAL ;
    PORT
      LAYER M5 ;
        RECT  80.112 49.596 80.136 49.68 ;
    END
  END q[499]
  PIN q[49]
    DIRECTION OUTPUT ;
    USE SIGNAL ;
    PORT
      LAYER M5 ;
        RECT  13.728 49.596 13.752 49.68 ;
    END
  END q[49]
  PIN q[4]
    DIRECTION OUTPUT ;
    USE SIGNAL ;
    PORT
      LAYER M5 ;
        RECT  7.248 49.596 7.272 49.68 ;
    END
  END q[4]
  PIN q[500]
    DIRECTION OUTPUT ;
    USE SIGNAL ;
    PORT
      LAYER M5 ;
        RECT  79.968 49.596 79.992 49.68 ;
    END
  END q[500]
  PIN q[501]
    DIRECTION OUTPUT ;
    USE SIGNAL ;
    PORT
      LAYER M5 ;
        RECT  80.4 49.596 80.424 49.68 ;
    END
  END q[501]
  PIN q[502]
    DIRECTION OUTPUT ;
    USE SIGNAL ;
    PORT
      LAYER M5 ;
        RECT  80.256 49.596 80.28 49.68 ;
    END
  END q[502]
  PIN q[503]
    DIRECTION OUTPUT ;
    USE SIGNAL ;
    PORT
      LAYER M5 ;
        RECT  80.688 49.596 80.712 49.68 ;
    END
  END q[503]
  PIN q[504]
    DIRECTION OUTPUT ;
    USE SIGNAL ;
    PORT
      LAYER M5 ;
        RECT  80.544 49.596 80.568 49.68 ;
    END
  END q[504]
  PIN q[505]
    DIRECTION OUTPUT ;
    USE SIGNAL ;
    PORT
      LAYER M5 ;
        RECT  80.976 49.596 81 49.68 ;
    END
  END q[505]
  PIN q[506]
    DIRECTION OUTPUT ;
    USE SIGNAL ;
    PORT
      LAYER M5 ;
        RECT  80.832 49.596 80.856 49.68 ;
    END
  END q[506]
  PIN q[507]
    DIRECTION OUTPUT ;
    USE SIGNAL ;
    PORT
      LAYER M5 ;
        RECT  81.264 49.596 81.288 49.68 ;
    END
  END q[507]
  PIN q[508]
    DIRECTION OUTPUT ;
    USE SIGNAL ;
    PORT
      LAYER M5 ;
        RECT  81.12 49.596 81.144 49.68 ;
    END
  END q[508]
  PIN q[509]
    DIRECTION OUTPUT ;
    USE SIGNAL ;
    PORT
      LAYER M5 ;
        RECT  81.696 49.596 81.72 49.68 ;
    END
  END q[509]
  PIN q[50]
    DIRECTION OUTPUT ;
    USE SIGNAL ;
    PORT
      LAYER M5 ;
        RECT  13.872 49.596 13.896 49.68 ;
    END
  END q[50]
  PIN q[510]
    DIRECTION OUTPUT ;
    USE SIGNAL ;
    PORT
      LAYER M5 ;
        RECT  81.408 49.596 81.432 49.68 ;
    END
  END q[510]
  PIN q[511]
    DIRECTION OUTPUT ;
    USE SIGNAL ;
    PORT
      LAYER M5 ;
        RECT  81.84 49.596 81.864 49.68 ;
    END
  END q[511]
  PIN q[512]
    DIRECTION OUTPUT ;
    USE SIGNAL ;
    PORT
      LAYER M5 ;
        RECT  81.552 49.596 81.576 49.68 ;
    END
  END q[512]
  PIN q[513]
    DIRECTION OUTPUT ;
    USE SIGNAL ;
    PORT
      LAYER M5 ;
        RECT  82.272 49.596 82.296 49.68 ;
    END
  END q[513]
  PIN q[514]
    DIRECTION OUTPUT ;
    USE SIGNAL ;
    PORT
      LAYER M5 ;
        RECT  81.984 49.596 82.008 49.68 ;
    END
  END q[514]
  PIN q[515]
    DIRECTION OUTPUT ;
    USE SIGNAL ;
    PORT
      LAYER M5 ;
        RECT  82.56 49.596 82.584 49.68 ;
    END
  END q[515]
  PIN q[516]
    DIRECTION OUTPUT ;
    USE SIGNAL ;
    PORT
      LAYER M5 ;
        RECT  82.128 49.596 82.152 49.68 ;
    END
  END q[516]
  PIN q[517]
    DIRECTION OUTPUT ;
    USE SIGNAL ;
    PORT
      LAYER M5 ;
        RECT  82.848 49.596 82.872 49.68 ;
    END
  END q[517]
  PIN q[518]
    DIRECTION OUTPUT ;
    USE SIGNAL ;
    PORT
      LAYER M5 ;
        RECT  82.416 49.596 82.44 49.68 ;
    END
  END q[518]
  PIN q[519]
    DIRECTION OUTPUT ;
    USE SIGNAL ;
    PORT
      LAYER M5 ;
        RECT  83.136 49.596 83.16 49.68 ;
    END
  END q[519]
  PIN q[51]
    DIRECTION OUTPUT ;
    USE SIGNAL ;
    PORT
      LAYER M5 ;
        RECT  14.016 49.596 14.04 49.68 ;
    END
  END q[51]
  PIN q[520]
    DIRECTION OUTPUT ;
    USE SIGNAL ;
    PORT
      LAYER M5 ;
        RECT  82.704 49.596 82.728 49.68 ;
    END
  END q[520]
  PIN q[521]
    DIRECTION OUTPUT ;
    USE SIGNAL ;
    PORT
      LAYER M5 ;
        RECT  83.28 49.596 83.304 49.68 ;
    END
  END q[521]
  PIN q[522]
    DIRECTION OUTPUT ;
    USE SIGNAL ;
    PORT
      LAYER M5 ;
        RECT  82.992 49.596 83.016 49.68 ;
    END
  END q[522]
  PIN q[523]
    DIRECTION OUTPUT ;
    USE SIGNAL ;
    PORT
      LAYER M5 ;
        RECT  83.424 49.596 83.448 49.68 ;
    END
  END q[523]
  PIN q[524]
    DIRECTION OUTPUT ;
    USE SIGNAL ;
    PORT
      LAYER M5 ;
        RECT  83.712 49.596 83.736 49.68 ;
    END
  END q[524]
  PIN q[525]
    DIRECTION OUTPUT ;
    USE SIGNAL ;
    PORT
      LAYER M5 ;
        RECT  83.568 49.596 83.592 49.68 ;
    END
  END q[525]
  PIN q[526]
    DIRECTION OUTPUT ;
    USE SIGNAL ;
    PORT
      LAYER M5 ;
        RECT  84 49.596 84.024 49.68 ;
    END
  END q[526]
  PIN q[527]
    DIRECTION OUTPUT ;
    USE SIGNAL ;
    PORT
      LAYER M5 ;
        RECT  83.856 49.596 83.88 49.68 ;
    END
  END q[527]
  PIN q[528]
    DIRECTION OUTPUT ;
    USE SIGNAL ;
    PORT
      LAYER M5 ;
        RECT  84.144 49.596 84.168 49.68 ;
    END
  END q[528]
  PIN q[529]
    DIRECTION OUTPUT ;
    USE SIGNAL ;
    PORT
      LAYER M5 ;
        RECT  84.288 49.596 84.312 49.68 ;
    END
  END q[529]
  PIN q[52]
    DIRECTION OUTPUT ;
    USE SIGNAL ;
    PORT
      LAYER M5 ;
        RECT  14.16 49.596 14.184 49.68 ;
    END
  END q[52]
  PIN q[530]
    DIRECTION OUTPUT ;
    USE SIGNAL ;
    PORT
      LAYER M5 ;
        RECT  84.432 49.596 84.456 49.68 ;
    END
  END q[530]
  PIN q[531]
    DIRECTION OUTPUT ;
    USE SIGNAL ;
    PORT
      LAYER M5 ;
        RECT  84.576 49.596 84.6 49.68 ;
    END
  END q[531]
  PIN q[532]
    DIRECTION OUTPUT ;
    USE SIGNAL ;
    PORT
      LAYER M5 ;
        RECT  84.864 49.596 84.888 49.68 ;
    END
  END q[532]
  PIN q[533]
    DIRECTION OUTPUT ;
    USE SIGNAL ;
    PORT
      LAYER M5 ;
        RECT  84.72 49.596 84.744 49.68 ;
    END
  END q[533]
  PIN q[534]
    DIRECTION OUTPUT ;
    USE SIGNAL ;
    PORT
      LAYER M5 ;
        RECT  85.008 49.596 85.032 49.68 ;
    END
  END q[534]
  PIN q[535]
    DIRECTION OUTPUT ;
    USE SIGNAL ;
    PORT
      LAYER M5 ;
        RECT  85.152 49.596 85.176 49.68 ;
    END
  END q[535]
  PIN q[536]
    DIRECTION OUTPUT ;
    USE SIGNAL ;
    PORT
      LAYER M5 ;
        RECT  85.296 49.596 85.32 49.68 ;
    END
  END q[536]
  PIN q[53]
    DIRECTION OUTPUT ;
    USE SIGNAL ;
    PORT
      LAYER M5 ;
        RECT  14.304 49.596 14.328 49.68 ;
    END
  END q[53]
  PIN q[54]
    DIRECTION OUTPUT ;
    USE SIGNAL ;
    PORT
      LAYER M5 ;
        RECT  14.448 49.596 14.472 49.68 ;
    END
  END q[54]
  PIN q[55]
    DIRECTION OUTPUT ;
    USE SIGNAL ;
    PORT
      LAYER M5 ;
        RECT  14.736 49.596 14.76 49.68 ;
    END
  END q[55]
  PIN q[56]
    DIRECTION OUTPUT ;
    USE SIGNAL ;
    PORT
      LAYER M5 ;
        RECT  14.592 49.596 14.616 49.68 ;
    END
  END q[56]
  PIN q[57]
    DIRECTION OUTPUT ;
    USE SIGNAL ;
    PORT
      LAYER M5 ;
        RECT  15.024 49.596 15.048 49.68 ;
    END
  END q[57]
  PIN q[58]
    DIRECTION OUTPUT ;
    USE SIGNAL ;
    PORT
      LAYER M5 ;
        RECT  14.88 49.596 14.904 49.68 ;
    END
  END q[58]
  PIN q[59]
    DIRECTION OUTPUT ;
    USE SIGNAL ;
    PORT
      LAYER M5 ;
        RECT  15.456 49.596 15.48 49.68 ;
    END
  END q[59]
  PIN q[5]
    DIRECTION OUTPUT ;
    USE SIGNAL ;
    PORT
      LAYER M5 ;
        RECT  7.392 49.596 7.416 49.68 ;
    END
  END q[5]
  PIN q[60]
    DIRECTION OUTPUT ;
    USE SIGNAL ;
    PORT
      LAYER M5 ;
        RECT  15.168 49.596 15.192 49.68 ;
    END
  END q[60]
  PIN q[61]
    DIRECTION OUTPUT ;
    USE SIGNAL ;
    PORT
      LAYER M5 ;
        RECT  15.6 49.596 15.624 49.68 ;
    END
  END q[61]
  PIN q[62]
    DIRECTION OUTPUT ;
    USE SIGNAL ;
    PORT
      LAYER M5 ;
        RECT  15.312 49.596 15.336 49.68 ;
    END
  END q[62]
  PIN q[63]
    DIRECTION OUTPUT ;
    USE SIGNAL ;
    PORT
      LAYER M5 ;
        RECT  15.888 49.596 15.912 49.68 ;
    END
  END q[63]
  PIN q[64]
    DIRECTION OUTPUT ;
    USE SIGNAL ;
    PORT
      LAYER M5 ;
        RECT  15.744 49.596 15.768 49.68 ;
    END
  END q[64]
  PIN q[65]
    DIRECTION OUTPUT ;
    USE SIGNAL ;
    PORT
      LAYER M5 ;
        RECT  16.176 49.596 16.2 49.68 ;
    END
  END q[65]
  PIN q[66]
    DIRECTION OUTPUT ;
    USE SIGNAL ;
    PORT
      LAYER M5 ;
        RECT  16.032 49.596 16.056 49.68 ;
    END
  END q[66]
  PIN q[67]
    DIRECTION OUTPUT ;
    USE SIGNAL ;
    PORT
      LAYER M5 ;
        RECT  16.464 49.596 16.488 49.68 ;
    END
  END q[67]
  PIN q[68]
    DIRECTION OUTPUT ;
    USE SIGNAL ;
    PORT
      LAYER M5 ;
        RECT  16.32 49.596 16.344 49.68 ;
    END
  END q[68]
  PIN q[69]
    DIRECTION OUTPUT ;
    USE SIGNAL ;
    PORT
      LAYER M5 ;
        RECT  16.752 49.596 16.776 49.68 ;
    END
  END q[69]
  PIN q[6]
    DIRECTION OUTPUT ;
    USE SIGNAL ;
    PORT
      LAYER M5 ;
        RECT  7.536 49.596 7.56 49.68 ;
    END
  END q[6]
  PIN q[70]
    DIRECTION OUTPUT ;
    USE SIGNAL ;
    PORT
      LAYER M5 ;
        RECT  16.608 49.596 16.632 49.68 ;
    END
  END q[70]
  PIN q[71]
    DIRECTION OUTPUT ;
    USE SIGNAL ;
    PORT
      LAYER M5 ;
        RECT  16.896 49.596 16.92 49.68 ;
    END
  END q[71]
  PIN q[72]
    DIRECTION OUTPUT ;
    USE SIGNAL ;
    PORT
      LAYER M5 ;
        RECT  17.184 49.596 17.208 49.68 ;
    END
  END q[72]
  PIN q[73]
    DIRECTION OUTPUT ;
    USE SIGNAL ;
    PORT
      LAYER M5 ;
        RECT  17.04 49.596 17.064 49.68 ;
    END
  END q[73]
  PIN q[74]
    DIRECTION OUTPUT ;
    USE SIGNAL ;
    PORT
      LAYER M5 ;
        RECT  17.472 49.596 17.496 49.68 ;
    END
  END q[74]
  PIN q[75]
    DIRECTION OUTPUT ;
    USE SIGNAL ;
    PORT
      LAYER M5 ;
        RECT  17.328 49.596 17.352 49.68 ;
    END
  END q[75]
  PIN q[76]
    DIRECTION OUTPUT ;
    USE SIGNAL ;
    PORT
      LAYER M5 ;
        RECT  17.76 49.596 17.784 49.68 ;
    END
  END q[76]
  PIN q[77]
    DIRECTION OUTPUT ;
    USE SIGNAL ;
    PORT
      LAYER M5 ;
        RECT  17.616 49.596 17.64 49.68 ;
    END
  END q[77]
  PIN q[78]
    DIRECTION OUTPUT ;
    USE SIGNAL ;
    PORT
      LAYER M5 ;
        RECT  18.048 49.596 18.072 49.68 ;
    END
  END q[78]
  PIN q[79]
    DIRECTION OUTPUT ;
    USE SIGNAL ;
    PORT
      LAYER M5 ;
        RECT  17.904 49.596 17.928 49.68 ;
    END
  END q[79]
  PIN q[7]
    DIRECTION OUTPUT ;
    USE SIGNAL ;
    PORT
      LAYER M5 ;
        RECT  7.68 49.596 7.704 49.68 ;
    END
  END q[7]
  PIN q[80]
    DIRECTION OUTPUT ;
    USE SIGNAL ;
    PORT
      LAYER M5 ;
        RECT  18.336 49.596 18.36 49.68 ;
    END
  END q[80]
  PIN q[81]
    DIRECTION OUTPUT ;
    USE SIGNAL ;
    PORT
      LAYER M5 ;
        RECT  18.192 49.596 18.216 49.68 ;
    END
  END q[81]
  PIN q[82]
    DIRECTION OUTPUT ;
    USE SIGNAL ;
    PORT
      LAYER M5 ;
        RECT  18.624 49.596 18.648 49.68 ;
    END
  END q[82]
  PIN q[83]
    DIRECTION OUTPUT ;
    USE SIGNAL ;
    PORT
      LAYER M5 ;
        RECT  18.48 49.596 18.504 49.68 ;
    END
  END q[83]
  PIN q[84]
    DIRECTION OUTPUT ;
    USE SIGNAL ;
    PORT
      LAYER M5 ;
        RECT  18.768 49.596 18.792 49.68 ;
    END
  END q[84]
  PIN q[85]
    DIRECTION OUTPUT ;
    USE SIGNAL ;
    PORT
      LAYER M5 ;
        RECT  18.912 49.596 18.936 49.68 ;
    END
  END q[85]
  PIN q[86]
    DIRECTION OUTPUT ;
    USE SIGNAL ;
    PORT
      LAYER M5 ;
        RECT  19.2 49.596 19.224 49.68 ;
    END
  END q[86]
  PIN q[87]
    DIRECTION OUTPUT ;
    USE SIGNAL ;
    PORT
      LAYER M5 ;
        RECT  19.056 49.596 19.08 49.68 ;
    END
  END q[87]
  PIN q[88]
    DIRECTION OUTPUT ;
    USE SIGNAL ;
    PORT
      LAYER M5 ;
        RECT  19.344 49.596 19.368 49.68 ;
    END
  END q[88]
  PIN q[89]
    DIRECTION OUTPUT ;
    USE SIGNAL ;
    PORT
      LAYER M5 ;
        RECT  19.488 49.596 19.512 49.68 ;
    END
  END q[89]
  PIN q[8]
    DIRECTION OUTPUT ;
    USE SIGNAL ;
    PORT
      LAYER M5 ;
        RECT  7.824 49.596 7.848 49.68 ;
    END
  END q[8]
  PIN q[90]
    DIRECTION OUTPUT ;
    USE SIGNAL ;
    PORT
      LAYER M5 ;
        RECT  19.632 49.596 19.656 49.68 ;
    END
  END q[90]
  PIN q[91]
    DIRECTION OUTPUT ;
    USE SIGNAL ;
    PORT
      LAYER M5 ;
        RECT  19.776 49.596 19.8 49.68 ;
    END
  END q[91]
  PIN q[92]
    DIRECTION OUTPUT ;
    USE SIGNAL ;
    PORT
      LAYER M5 ;
        RECT  19.92 49.596 19.944 49.68 ;
    END
  END q[92]
  PIN q[93]
    DIRECTION OUTPUT ;
    USE SIGNAL ;
    PORT
      LAYER M5 ;
        RECT  20.064 49.596 20.088 49.68 ;
    END
  END q[93]
  PIN q[94]
    DIRECTION OUTPUT ;
    USE SIGNAL ;
    PORT
      LAYER M5 ;
        RECT  20.208 49.596 20.232 49.68 ;
    END
  END q[94]
  PIN q[95]
    DIRECTION OUTPUT ;
    USE SIGNAL ;
    PORT
      LAYER M5 ;
        RECT  20.352 49.596 20.376 49.68 ;
    END
  END q[95]
  PIN q[96]
    DIRECTION OUTPUT ;
    USE SIGNAL ;
    PORT
      LAYER M5 ;
        RECT  20.496 49.596 20.52 49.68 ;
    END
  END q[96]
  PIN q[97]
    DIRECTION OUTPUT ;
    USE SIGNAL ;
    PORT
      LAYER M5 ;
        RECT  20.64 49.596 20.664 49.68 ;
    END
  END q[97]
  PIN q[98]
    DIRECTION OUTPUT ;
    USE SIGNAL ;
    PORT
      LAYER M5 ;
        RECT  20.784 49.596 20.808 49.68 ;
    END
  END q[98]
  PIN q[99]
    DIRECTION OUTPUT ;
    USE SIGNAL ;
    PORT
      LAYER M5 ;
        RECT  20.928 49.596 20.952 49.68 ;
    END
  END q[99]
  PIN q[9]
    DIRECTION OUTPUT ;
    USE SIGNAL ;
    PORT
      LAYER M5 ;
        RECT  8.256 49.596 8.28 49.68 ;
    END
  END q[9]
  PIN ready
    DIRECTION OUTPUT ;
    USE SIGNAL ;
    PORT
      LAYER M5 ;
        RECT  45.552 49.596 45.576 49.68 ;
    END
  END ready
  PIN rst_n
    DIRECTION INPUT ;
    USE SIGNAL ;
    PORT
      LAYER M5 ;
        RECT  45.408 49.596 45.432 49.68 ;
    END
  END rst_n
  PIN strap_k[0]
    DIRECTION INPUT ;
    USE SIGNAL ;
    PORT
      LAYER M5 ;
        RECT  45.84 49.596 45.864 49.68 ;
    END
  END strap_k[0]
  PIN strap_k[1]
    DIRECTION INPUT ;
    USE SIGNAL ;
    PORT
      LAYER M5 ;
        RECT  45.984 49.596 46.008 49.68 ;
    END
  END strap_k[1]
  PIN strap_k[2]
    DIRECTION INPUT ;
    USE SIGNAL ;
    PORT
      LAYER M5 ;
        RECT  46.128 49.596 46.152 49.68 ;
    END
  END strap_k[2]
  PIN strap_k[3]
    DIRECTION INPUT ;
    USE SIGNAL ;
    PORT
      LAYER M5 ;
        RECT  46.272 49.596 46.296 49.68 ;
    END
  END strap_k[3]
  PIN strap_k[4]
    DIRECTION INPUT ;
    USE SIGNAL ;
    PORT
      LAYER M5 ;
        RECT  46.416 49.596 46.44 49.68 ;
    END
  END strap_k[4]
  PIN strap_k[5]
    DIRECTION INPUT ;
    USE SIGNAL ;
    PORT
      LAYER M5 ;
        RECT  46.56 49.596 46.584 49.68 ;
    END
  END strap_k[5]
  PIN t_rst_n
    DIRECTION INPUT ;
    USE SIGNAL ;
    PORT
      LAYER M5 ;
        RECT  45.984 0 46.008 0.084 ;
    END
  END t_rst_n
  PIN VDD
    DIRECTION INOUT ;
    USE POWER ;
    PORT
      LAYER M5 ;
        RECT  84.276 4.311 84.396 45.369 ;
        RECT  79.956 4.311 80.076 45.369 ;
        RECT  75.636 4.311 75.756 45.369 ;
        RECT  71.316 4.311 71.436 45.369 ;
        RECT  66.996 4.311 67.116 45.369 ;
        RECT  62.676 4.311 62.796 45.369 ;
        RECT  58.356 4.311 58.476 45.369 ;
        RECT  54.036 4.311 54.156 45.369 ;
        RECT  49.716 4.311 49.836 45.369 ;
        RECT  45.396 4.311 45.516 45.369 ;
        RECT  41.076 4.311 41.196 45.369 ;
        RECT  36.756 4.311 36.876 45.369 ;
        RECT  32.436 4.311 32.556 45.369 ;
        RECT  28.116 4.311 28.236 45.369 ;
        RECT  23.796 4.311 23.916 45.369 ;
        RECT  19.476 4.311 19.596 45.369 ;
        RECT  15.156 4.311 15.276 45.369 ;
        RECT  10.836 4.311 10.956 45.369 ;
        RECT  6.516 4.311 6.636 45.369 ;
    END
  END VDD
  PIN VSS
    DIRECTION INOUT ;
    USE GROUND ;
    PORT
      LAYER M5 ;
        RECT  84.084 4.297 84.204 45.383 ;
        RECT  79.764 4.297 79.884 45.383 ;
        RECT  75.444 4.297 75.564 45.383 ;
        RECT  71.124 4.297 71.244 45.383 ;
        RECT  66.804 4.297 66.924 45.383 ;
        RECT  62.484 4.297 62.604 45.383 ;
        RECT  58.164 4.297 58.284 45.383 ;
        RECT  53.844 4.297 53.964 45.383 ;
        RECT  49.524 4.297 49.644 45.383 ;
        RECT  45.204 4.297 45.324 45.383 ;
        RECT  40.884 4.297 41.004 45.383 ;
        RECT  36.564 4.297 36.684 45.383 ;
        RECT  32.244 4.297 32.364 45.383 ;
        RECT  27.924 4.297 28.044 45.383 ;
        RECT  23.604 4.297 23.724 45.383 ;
        RECT  19.284 4.297 19.404 45.383 ;
        RECT  14.964 4.297 15.084 45.383 ;
        RECT  10.644 4.297 10.764 45.383 ;
        RECT  6.324 4.297 6.444 45.383 ;
    END
  END VSS
  OBS
    LAYER RVTN ;
     RECT  4.32 0 87.696 49.68 ;
    LAYER RVTP ;
     RECT  4.32 0 87.696 49.68 ;
    LAYER M1 ;
     RECT  4.32 0 87.696 49.68 ;
    LAYER M2 ;
     RECT  4.32 0 87.696 49.68 ;
    LAYER M3 ;
     RECT  4.32 0 87.696 49.68 ;
    LAYER M4 ;
     RECT  4.32 0 87.696 49.68 ;
    LAYER M5 ;
     RECT  4.32 0 87.696 49.68 ;
  END
END sle_cland_w537_s
END LIBRARY
